VERSION 5.8 ;
BUSBITCHARS "[]" ;
DIVIDERCHAR "/" ;
UNITS
    DATABASE MICRONS 1000 ;
END UNITS

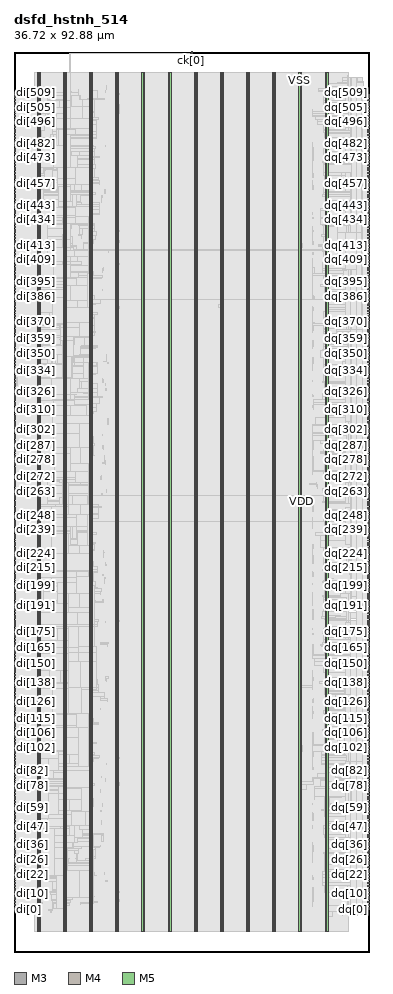
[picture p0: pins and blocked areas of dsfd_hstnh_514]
MACRO dsfd_hstnh_514
  FOREIGN dsfd_hstnh_514 0 0 ;
  CLASS BLOCK ;
  SIZE 36.72 BY 92.88 ;
  PIN ck[0]
    DIRECTION INPUT ;
    USE SIGNAL ;
    PORT
      LAYER M3 ;
        RECT  18.36 92.736 18.378 92.88 ;
    END
    PORT
      LAYER M3 ;
        RECT  18.18 92.713 18.378 92.748 ;
    END
  END ck[0]
  PIN di[0]
    DIRECTION INPUT ;
    USE SIGNAL ;
    PORT
      LAYER M4 ;
        RECT  0 4.416 0.192 4.44 ;
    END
  END di[0]
  PIN di[100]
    DIRECTION INPUT ;
    USE SIGNAL ;
    PORT
      LAYER M4 ;
        RECT  0 20.784 0.192 20.808 ;
    END
  END di[100]
  PIN di[101]
    DIRECTION INPUT ;
    USE SIGNAL ;
    PORT
      LAYER M4 ;
        RECT  0 20.976 0.192 21 ;
    END
  END di[101]
  PIN di[102]
    DIRECTION INPUT ;
    USE SIGNAL ;
    PORT
      LAYER M4 ;
        RECT  0 21.12 0.192 21.144 ;
    END
  END di[102]
  PIN di[103]
    DIRECTION INPUT ;
    USE SIGNAL ;
    PORT
      LAYER M4 ;
        RECT  0 21.312 0.192 21.336 ;
    END
  END di[103]
  PIN di[104]
    DIRECTION INPUT ;
    USE SIGNAL ;
    PORT
      LAYER M4 ;
        RECT  0 21.456 0.192 21.48 ;
    END
  END di[104]
  PIN di[105]
    DIRECTION INPUT ;
    USE SIGNAL ;
    PORT
      LAYER M4 ;
        RECT  0 21.6 0.192 21.624 ;
    END
  END di[105]
  PIN di[106]
    DIRECTION INPUT ;
    USE SIGNAL ;
    PORT
      LAYER M4 ;
        RECT  0 21.792 0.192 21.816 ;
    END
  END di[106]
  PIN di[107]
    DIRECTION INPUT ;
    USE SIGNAL ;
    PORT
      LAYER M4 ;
        RECT  0 21.936 0.192 21.96 ;
    END
  END di[107]
  PIN di[108]
    DIRECTION INPUT ;
    USE SIGNAL ;
    PORT
      LAYER M4 ;
        RECT  0 22.128 0.192 22.152 ;
    END
  END di[108]
  PIN di[109]
    DIRECTION INPUT ;
    USE SIGNAL ;
    PORT
      LAYER M4 ;
        RECT  0 22.272 0.192 22.296 ;
    END
  END di[109]
  PIN di[10]
    DIRECTION INPUT ;
    USE SIGNAL ;
    PORT
      LAYER M4 ;
        RECT  0 6.048 0.192 6.072 ;
    END
  END di[10]
  PIN di[110]
    DIRECTION INPUT ;
    USE SIGNAL ;
    PORT
      LAYER M4 ;
        RECT  0 22.464 0.192 22.488 ;
    END
  END di[110]
  PIN di[111]
    DIRECTION INPUT ;
    USE SIGNAL ;
    PORT
      LAYER M4 ;
        RECT  0 22.608 0.192 22.632 ;
    END
  END di[111]
  PIN di[112]
    DIRECTION INPUT ;
    USE SIGNAL ;
    PORT
      LAYER M4 ;
        RECT  0 22.752 0.192 22.776 ;
    END
  END di[112]
  PIN di[113]
    DIRECTION INPUT ;
    USE SIGNAL ;
    PORT
      LAYER M4 ;
        RECT  0 22.944 0.192 22.968 ;
    END
  END di[113]
  PIN di[114]
    DIRECTION INPUT ;
    USE SIGNAL ;
    PORT
      LAYER M4 ;
        RECT  0 23.088 0.192 23.112 ;
    END
  END di[114]
  PIN di[115]
    DIRECTION INPUT ;
    USE SIGNAL ;
    PORT
      LAYER M4 ;
        RECT  0 23.28 0.192 23.304 ;
    END
  END di[115]
  PIN di[116]
    DIRECTION INPUT ;
    USE SIGNAL ;
    PORT
      LAYER M4 ;
        RECT  0 23.424 0.192 23.448 ;
    END
  END di[116]
  PIN di[117]
    DIRECTION INPUT ;
    USE SIGNAL ;
    PORT
      LAYER M4 ;
        RECT  0 23.568 0.192 23.592 ;
    END
  END di[117]
  PIN di[118]
    DIRECTION INPUT ;
    USE SIGNAL ;
    PORT
      LAYER M4 ;
        RECT  0 23.76 0.192 23.784 ;
    END
  END di[118]
  PIN di[119]
    DIRECTION INPUT ;
    USE SIGNAL ;
    PORT
      LAYER M4 ;
        RECT  0 23.904 0.192 23.928 ;
    END
  END di[119]
  PIN di[11]
    DIRECTION INPUT ;
    USE SIGNAL ;
    PORT
      LAYER M4 ;
        RECT  0 6.24 0.192 6.264 ;
    END
  END di[11]
  PIN di[120]
    DIRECTION INPUT ;
    USE SIGNAL ;
    PORT
      LAYER M4 ;
        RECT  0 24.096 0.192 24.12 ;
    END
  END di[120]
  PIN di[121]
    DIRECTION INPUT ;
    USE SIGNAL ;
    PORT
      LAYER M4 ;
        RECT  0 24.24 0.192 24.264 ;
    END
  END di[121]
  PIN di[122]
    DIRECTION INPUT ;
    USE SIGNAL ;
    PORT
      LAYER M4 ;
        RECT  0 24.432 0.192 24.456 ;
    END
  END di[122]
  PIN di[123]
    DIRECTION INPUT ;
    USE SIGNAL ;
    PORT
      LAYER M4 ;
        RECT  0 24.576 0.192 24.6 ;
    END
  END di[123]
  PIN di[124]
    DIRECTION INPUT ;
    USE SIGNAL ;
    PORT
      LAYER M4 ;
        RECT  0 24.72 0.192 24.744 ;
    END
  END di[124]
  PIN di[125]
    DIRECTION INPUT ;
    USE SIGNAL ;
    PORT
      LAYER M4 ;
        RECT  0 24.912 0.192 24.936 ;
    END
  END di[125]
  PIN di[126]
    DIRECTION INPUT ;
    USE SIGNAL ;
    PORT
      LAYER M4 ;
        RECT  0 25.056 0.192 25.08 ;
    END
  END di[126]
  PIN di[127]
    DIRECTION INPUT ;
    USE SIGNAL ;
    PORT
      LAYER M4 ;
        RECT  0 25.248 0.192 25.272 ;
    END
  END di[127]
  PIN di[128]
    DIRECTION INPUT ;
    USE SIGNAL ;
    PORT
      LAYER M4 ;
        RECT  0 25.392 0.192 25.416 ;
    END
  END di[128]
  PIN di[129]
    DIRECTION INPUT ;
    USE SIGNAL ;
    PORT
      LAYER M4 ;
        RECT  0 25.536 0.192 25.56 ;
    END
  END di[129]
  PIN di[12]
    DIRECTION INPUT ;
    USE SIGNAL ;
    PORT
      LAYER M4 ;
        RECT  0 6.384 0.192 6.408 ;
    END
  END di[12]
  PIN di[130]
    DIRECTION INPUT ;
    USE SIGNAL ;
    PORT
      LAYER M4 ;
        RECT  0 25.728 0.192 25.752 ;
    END
  END di[130]
  PIN di[131]
    DIRECTION INPUT ;
    USE SIGNAL ;
    PORT
      LAYER M4 ;
        RECT  0 25.872 0.192 25.896 ;
    END
  END di[131]
  PIN di[132]
    DIRECTION INPUT ;
    USE SIGNAL ;
    PORT
      LAYER M4 ;
        RECT  0 26.064 0.192 26.088 ;
    END
  END di[132]
  PIN di[133]
    DIRECTION INPUT ;
    USE SIGNAL ;
    PORT
      LAYER M4 ;
        RECT  0 26.208 0.192 26.232 ;
    END
  END di[133]
  PIN di[134]
    DIRECTION INPUT ;
    USE SIGNAL ;
    PORT
      LAYER M4 ;
        RECT  0 26.352 0.192 26.376 ;
    END
  END di[134]
  PIN di[135]
    DIRECTION INPUT ;
    USE SIGNAL ;
    PORT
      LAYER M4 ;
        RECT  0 26.544 0.192 26.568 ;
    END
  END di[135]
  PIN di[136]
    DIRECTION INPUT ;
    USE SIGNAL ;
    PORT
      LAYER M4 ;
        RECT  0 26.688 0.192 26.712 ;
    END
  END di[136]
  PIN di[137]
    DIRECTION INPUT ;
    USE SIGNAL ;
    PORT
      LAYER M4 ;
        RECT  0 26.88 0.192 26.904 ;
    END
  END di[137]
  PIN di[138]
    DIRECTION INPUT ;
    USE SIGNAL ;
    PORT
      LAYER M4 ;
        RECT  0 27.024 0.192 27.048 ;
    END
  END di[138]
  PIN di[139]
    DIRECTION INPUT ;
    USE SIGNAL ;
    PORT
      LAYER M4 ;
        RECT  0 27.216 0.192 27.24 ;
    END
  END di[139]
  PIN di[13]
    DIRECTION INPUT ;
    USE SIGNAL ;
    PORT
      LAYER M4 ;
        RECT  0 6.528 0.192 6.552 ;
    END
  END di[13]
  PIN di[140]
    DIRECTION INPUT ;
    USE SIGNAL ;
    PORT
      LAYER M4 ;
        RECT  0 27.36 0.192 27.384 ;
    END
  END di[140]
  PIN di[141]
    DIRECTION INPUT ;
    USE SIGNAL ;
    PORT
      LAYER M4 ;
        RECT  0 27.504 0.192 27.528 ;
    END
  END di[141]
  PIN di[142]
    DIRECTION INPUT ;
    USE SIGNAL ;
    PORT
      LAYER M4 ;
        RECT  0 27.696 0.192 27.72 ;
    END
  END di[142]
  PIN di[143]
    DIRECTION INPUT ;
    USE SIGNAL ;
    PORT
      LAYER M4 ;
        RECT  0 27.84 0.192 27.864 ;
    END
  END di[143]
  PIN di[144]
    DIRECTION INPUT ;
    USE SIGNAL ;
    PORT
      LAYER M4 ;
        RECT  0 28.032 0.192 28.056 ;
    END
  END di[144]
  PIN di[145]
    DIRECTION INPUT ;
    USE SIGNAL ;
    PORT
      LAYER M4 ;
        RECT  0 28.176 0.192 28.2 ;
    END
  END di[145]
  PIN di[146]
    DIRECTION INPUT ;
    USE SIGNAL ;
    PORT
      LAYER M4 ;
        RECT  0 28.32 0.192 28.344 ;
    END
  END di[146]
  PIN di[147]
    DIRECTION INPUT ;
    USE SIGNAL ;
    PORT
      LAYER M4 ;
        RECT  0 28.512 0.192 28.536 ;
    END
  END di[147]
  PIN di[148]
    DIRECTION INPUT ;
    USE SIGNAL ;
    PORT
      LAYER M4 ;
        RECT  0 28.656 0.192 28.68 ;
    END
  END di[148]
  PIN di[149]
    DIRECTION INPUT ;
    USE SIGNAL ;
    PORT
      LAYER M4 ;
        RECT  0 28.848 0.192 28.872 ;
    END
  END di[149]
  PIN di[14]
    DIRECTION INPUT ;
    USE SIGNAL ;
    PORT
      LAYER M4 ;
        RECT  0 6.72 0.192 6.744 ;
    END
  END di[14]
  PIN di[150]
    DIRECTION INPUT ;
    USE SIGNAL ;
    PORT
      LAYER M4 ;
        RECT  0 28.992 0.192 29.016 ;
    END
  END di[150]
  PIN di[151]
    DIRECTION INPUT ;
    USE SIGNAL ;
    PORT
      LAYER M4 ;
        RECT  0 29.184 0.192 29.208 ;
    END
  END di[151]
  PIN di[152]
    DIRECTION INPUT ;
    USE SIGNAL ;
    PORT
      LAYER M4 ;
        RECT  0 29.328 0.192 29.352 ;
    END
  END di[152]
  PIN di[153]
    DIRECTION INPUT ;
    USE SIGNAL ;
    PORT
      LAYER M4 ;
        RECT  0 29.472 0.192 29.496 ;
    END
  END di[153]
  PIN di[154]
    DIRECTION INPUT ;
    USE SIGNAL ;
    PORT
      LAYER M4 ;
        RECT  0 29.664 0.192 29.688 ;
    END
  END di[154]
  PIN di[155]
    DIRECTION INPUT ;
    USE SIGNAL ;
    PORT
      LAYER M4 ;
        RECT  0 29.808 0.192 29.832 ;
    END
  END di[155]
  PIN di[156]
    DIRECTION INPUT ;
    USE SIGNAL ;
    PORT
      LAYER M4 ;
        RECT  0 30 0.192 30.024 ;
    END
  END di[156]
  PIN di[157]
    DIRECTION INPUT ;
    USE SIGNAL ;
    PORT
      LAYER M4 ;
        RECT  0 30.144 0.192 30.168 ;
    END
  END di[157]
  PIN di[158]
    DIRECTION INPUT ;
    USE SIGNAL ;
    PORT
      LAYER M4 ;
        RECT  0 30.288 0.192 30.312 ;
    END
  END di[158]
  PIN di[159]
    DIRECTION INPUT ;
    USE SIGNAL ;
    PORT
      LAYER M4 ;
        RECT  0 30.48 0.192 30.504 ;
    END
  END di[159]
  PIN di[15]
    DIRECTION INPUT ;
    USE SIGNAL ;
    PORT
      LAYER M4 ;
        RECT  0 6.864 0.192 6.888 ;
    END
  END di[15]
  PIN di[160]
    DIRECTION INPUT ;
    USE SIGNAL ;
    PORT
      LAYER M4 ;
        RECT  0 30.624 0.192 30.648 ;
    END
  END di[160]
  PIN di[161]
    DIRECTION INPUT ;
    USE SIGNAL ;
    PORT
      LAYER M4 ;
        RECT  0 30.816 0.192 30.84 ;
    END
  END di[161]
  PIN di[162]
    DIRECTION INPUT ;
    USE SIGNAL ;
    PORT
      LAYER M4 ;
        RECT  0 30.96 0.192 30.984 ;
    END
  END di[162]
  PIN di[163]
    DIRECTION INPUT ;
    USE SIGNAL ;
    PORT
      LAYER M4 ;
        RECT  0 31.152 0.192 31.176 ;
    END
  END di[163]
  PIN di[164]
    DIRECTION INPUT ;
    USE SIGNAL ;
    PORT
      LAYER M4 ;
        RECT  0 31.296 0.192 31.32 ;
    END
  END di[164]
  PIN di[165]
    DIRECTION INPUT ;
    USE SIGNAL ;
    PORT
      LAYER M4 ;
        RECT  0 31.44 0.192 31.464 ;
    END
  END di[165]
  PIN di[166]
    DIRECTION INPUT ;
    USE SIGNAL ;
    PORT
      LAYER M4 ;
        RECT  0 31.632 0.192 31.656 ;
    END
  END di[166]
  PIN di[167]
    DIRECTION INPUT ;
    USE SIGNAL ;
    PORT
      LAYER M4 ;
        RECT  0 31.776 0.192 31.8 ;
    END
  END di[167]
  PIN di[168]
    DIRECTION INPUT ;
    USE SIGNAL ;
    PORT
      LAYER M4 ;
        RECT  0 31.968 0.192 31.992 ;
    END
  END di[168]
  PIN di[169]
    DIRECTION INPUT ;
    USE SIGNAL ;
    PORT
      LAYER M4 ;
        RECT  0 32.112 0.192 32.136 ;
    END
  END di[169]
  PIN di[16]
    DIRECTION INPUT ;
    USE SIGNAL ;
    PORT
      LAYER M4 ;
        RECT  0 7.056 0.192 7.08 ;
    END
  END di[16]
  PIN di[170]
    DIRECTION INPUT ;
    USE SIGNAL ;
    PORT
      LAYER M4 ;
        RECT  0 32.256 0.192 32.28 ;
    END
  END di[170]
  PIN di[171]
    DIRECTION INPUT ;
    USE SIGNAL ;
    PORT
      LAYER M4 ;
        RECT  0 32.448 0.192 32.472 ;
    END
  END di[171]
  PIN di[172]
    DIRECTION INPUT ;
    USE SIGNAL ;
    PORT
      LAYER M4 ;
        RECT  0 32.592 0.192 32.616 ;
    END
  END di[172]
  PIN di[173]
    DIRECTION INPUT ;
    USE SIGNAL ;
    PORT
      LAYER M4 ;
        RECT  0 32.784 0.192 32.808 ;
    END
  END di[173]
  PIN di[174]
    DIRECTION INPUT ;
    USE SIGNAL ;
    PORT
      LAYER M4 ;
        RECT  0 32.928 0.192 32.952 ;
    END
  END di[174]
  PIN di[175]
    DIRECTION INPUT ;
    USE SIGNAL ;
    PORT
      LAYER M4 ;
        RECT  0 33.072 0.192 33.096 ;
    END
  END di[175]
  PIN di[176]
    DIRECTION INPUT ;
    USE SIGNAL ;
    PORT
      LAYER M4 ;
        RECT  0 33.264 0.192 33.288 ;
    END
  END di[176]
  PIN di[177]
    DIRECTION INPUT ;
    USE SIGNAL ;
    PORT
      LAYER M4 ;
        RECT  0 33.408 0.192 33.432 ;
    END
  END di[177]
  PIN di[178]
    DIRECTION INPUT ;
    USE SIGNAL ;
    PORT
      LAYER M4 ;
        RECT  0 33.6 0.192 33.624 ;
    END
  END di[178]
  PIN di[179]
    DIRECTION INPUT ;
    USE SIGNAL ;
    PORT
      LAYER M4 ;
        RECT  0 33.744 0.192 33.768 ;
    END
  END di[179]
  PIN di[17]
    DIRECTION INPUT ;
    USE SIGNAL ;
    PORT
      LAYER M4 ;
        RECT  0 7.2 0.192 7.224 ;
    END
  END di[17]
  PIN di[180]
    DIRECTION INPUT ;
    USE SIGNAL ;
    PORT
      LAYER M4 ;
        RECT  0 33.936 0.192 33.96 ;
    END
  END di[180]
  PIN di[181]
    DIRECTION INPUT ;
    USE SIGNAL ;
    PORT
      LAYER M4 ;
        RECT  0 34.08 0.192 34.104 ;
    END
  END di[181]
  PIN di[182]
    DIRECTION INPUT ;
    USE SIGNAL ;
    PORT
      LAYER M4 ;
        RECT  0 34.224 0.192 34.248 ;
    END
  END di[182]
  PIN di[183]
    DIRECTION INPUT ;
    USE SIGNAL ;
    PORT
      LAYER M4 ;
        RECT  0 34.416 0.192 34.44 ;
    END
  END di[183]
  PIN di[184]
    DIRECTION INPUT ;
    USE SIGNAL ;
    PORT
      LAYER M4 ;
        RECT  0 34.56 0.192 34.584 ;
    END
  END di[184]
  PIN di[185]
    DIRECTION INPUT ;
    USE SIGNAL ;
    PORT
      LAYER M4 ;
        RECT  0 34.752 0.192 34.776 ;
    END
  END di[185]
  PIN di[186]
    DIRECTION INPUT ;
    USE SIGNAL ;
    PORT
      LAYER M4 ;
        RECT  0 34.896 0.192 34.92 ;
    END
  END di[186]
  PIN di[187]
    DIRECTION INPUT ;
    USE SIGNAL ;
    PORT
      LAYER M4 ;
        RECT  0 35.04 0.192 35.064 ;
    END
  END di[187]
  PIN di[188]
    DIRECTION INPUT ;
    USE SIGNAL ;
    PORT
      LAYER M4 ;
        RECT  0 35.232 0.192 35.256 ;
    END
  END di[188]
  PIN di[189]
    DIRECTION INPUT ;
    USE SIGNAL ;
    PORT
      LAYER M4 ;
        RECT  0 35.376 0.192 35.4 ;
    END
  END di[189]
  PIN di[18]
    DIRECTION INPUT ;
    USE SIGNAL ;
    PORT
      LAYER M4 ;
        RECT  0 7.344 0.192 7.368 ;
    END
  END di[18]
  PIN di[190]
    DIRECTION INPUT ;
    USE SIGNAL ;
    PORT
      LAYER M4 ;
        RECT  0 35.568 0.192 35.592 ;
    END
  END di[190]
  PIN di[191]
    DIRECTION INPUT ;
    USE SIGNAL ;
    PORT
      LAYER M4 ;
        RECT  0 35.712 0.192 35.736 ;
    END
  END di[191]
  PIN di[192]
    DIRECTION INPUT ;
    USE SIGNAL ;
    PORT
      LAYER M4 ;
        RECT  0 35.904 0.192 35.928 ;
    END
  END di[192]
  PIN di[193]
    DIRECTION INPUT ;
    USE SIGNAL ;
    PORT
      LAYER M4 ;
        RECT  0 36.048 0.192 36.072 ;
    END
  END di[193]
  PIN di[194]
    DIRECTION INPUT ;
    USE SIGNAL ;
    PORT
      LAYER M4 ;
        RECT  0 36.192 0.192 36.216 ;
    END
  END di[194]
  PIN di[195]
    DIRECTION INPUT ;
    USE SIGNAL ;
    PORT
      LAYER M4 ;
        RECT  0 36.384 0.192 36.408 ;
    END
  END di[195]
  PIN di[196]
    DIRECTION INPUT ;
    USE SIGNAL ;
    PORT
      LAYER M4 ;
        RECT  0 36.528 0.192 36.552 ;
    END
  END di[196]
  PIN di[197]
    DIRECTION INPUT ;
    USE SIGNAL ;
    PORT
      LAYER M4 ;
        RECT  0 36.72 0.192 36.744 ;
    END
  END di[197]
  PIN di[198]
    DIRECTION INPUT ;
    USE SIGNAL ;
    PORT
      LAYER M4 ;
        RECT  0 36.864 0.192 36.888 ;
    END
  END di[198]
  PIN di[199]
    DIRECTION INPUT ;
    USE SIGNAL ;
    PORT
      LAYER M4 ;
        RECT  0 37.008 0.192 37.032 ;
    END
  END di[199]
  PIN di[19]
    DIRECTION INPUT ;
    USE SIGNAL ;
    PORT
      LAYER M4 ;
        RECT  0 7.536 0.192 7.56 ;
    END
  END di[19]
  PIN di[1]
    DIRECTION INPUT ;
    USE SIGNAL ;
    PORT
      LAYER M4 ;
        RECT  0 4.56 0.192 4.584 ;
    END
  END di[1]
  PIN di[200]
    DIRECTION INPUT ;
    USE SIGNAL ;
    PORT
      LAYER M4 ;
        RECT  0 37.2 0.192 37.224 ;
    END
  END di[200]
  PIN di[201]
    DIRECTION INPUT ;
    USE SIGNAL ;
    PORT
      LAYER M4 ;
        RECT  0 37.344 0.192 37.368 ;
    END
  END di[201]
  PIN di[202]
    DIRECTION INPUT ;
    USE SIGNAL ;
    PORT
      LAYER M4 ;
        RECT  0 37.536 0.192 37.56 ;
    END
  END di[202]
  PIN di[203]
    DIRECTION INPUT ;
    USE SIGNAL ;
    PORT
      LAYER M4 ;
        RECT  0 37.68 0.192 37.704 ;
    END
  END di[203]
  PIN di[204]
    DIRECTION INPUT ;
    USE SIGNAL ;
    PORT
      LAYER M4 ;
        RECT  0 37.824 0.192 37.848 ;
    END
  END di[204]
  PIN di[205]
    DIRECTION INPUT ;
    USE SIGNAL ;
    PORT
      LAYER M4 ;
        RECT  0 38.016 0.192 38.04 ;
    END
  END di[205]
  PIN di[206]
    DIRECTION INPUT ;
    USE SIGNAL ;
    PORT
      LAYER M4 ;
        RECT  0 38.16 0.192 38.184 ;
    END
  END di[206]
  PIN di[207]
    DIRECTION INPUT ;
    USE SIGNAL ;
    PORT
      LAYER M4 ;
        RECT  0 38.352 0.192 38.376 ;
    END
  END di[207]
  PIN di[208]
    DIRECTION INPUT ;
    USE SIGNAL ;
    PORT
      LAYER M4 ;
        RECT  0 38.496 0.192 38.52 ;
    END
  END di[208]
  PIN di[209]
    DIRECTION INPUT ;
    USE SIGNAL ;
    PORT
      LAYER M4 ;
        RECT  0 38.688 0.192 38.712 ;
    END
  END di[209]
  PIN di[20]
    DIRECTION INPUT ;
    USE SIGNAL ;
    PORT
      LAYER M4 ;
        RECT  0 7.68 0.192 7.704 ;
    END
  END di[20]
  PIN di[210]
    DIRECTION INPUT ;
    USE SIGNAL ;
    PORT
      LAYER M4 ;
        RECT  0 38.832 0.192 38.856 ;
    END
  END di[210]
  PIN di[211]
    DIRECTION INPUT ;
    USE SIGNAL ;
    PORT
      LAYER M4 ;
        RECT  0 38.976 0.192 39 ;
    END
  END di[211]
  PIN di[212]
    DIRECTION INPUT ;
    USE SIGNAL ;
    PORT
      LAYER M4 ;
        RECT  0 39.168 0.192 39.192 ;
    END
  END di[212]
  PIN di[213]
    DIRECTION INPUT ;
    USE SIGNAL ;
    PORT
      LAYER M4 ;
        RECT  0 39.312 0.192 39.336 ;
    END
  END di[213]
  PIN di[214]
    DIRECTION INPUT ;
    USE SIGNAL ;
    PORT
      LAYER M4 ;
        RECT  0 39.504 0.192 39.528 ;
    END
  END di[214]
  PIN di[215]
    DIRECTION INPUT ;
    USE SIGNAL ;
    PORT
      LAYER M4 ;
        RECT  0 39.648 0.192 39.672 ;
    END
  END di[215]
  PIN di[216]
    DIRECTION INPUT ;
    USE SIGNAL ;
    PORT
      LAYER M4 ;
        RECT  0 39.792 0.192 39.816 ;
    END
  END di[216]
  PIN di[217]
    DIRECTION INPUT ;
    USE SIGNAL ;
    PORT
      LAYER M4 ;
        RECT  0 39.984 0.192 40.008 ;
    END
  END di[217]
  PIN di[218]
    DIRECTION INPUT ;
    USE SIGNAL ;
    PORT
      LAYER M4 ;
        RECT  0 40.128 0.192 40.152 ;
    END
  END di[218]
  PIN di[219]
    DIRECTION INPUT ;
    USE SIGNAL ;
    PORT
      LAYER M4 ;
        RECT  0 40.32 0.192 40.344 ;
    END
  END di[219]
  PIN di[21]
    DIRECTION INPUT ;
    USE SIGNAL ;
    PORT
      LAYER M4 ;
        RECT  0 7.872 0.192 7.896 ;
    END
  END di[21]
  PIN di[220]
    DIRECTION INPUT ;
    USE SIGNAL ;
    PORT
      LAYER M4 ;
        RECT  0 40.464 0.192 40.488 ;
    END
  END di[220]
  PIN di[221]
    DIRECTION INPUT ;
    USE SIGNAL ;
    PORT
      LAYER M4 ;
        RECT  0 40.656 0.192 40.68 ;
    END
  END di[221]
  PIN di[222]
    DIRECTION INPUT ;
    USE SIGNAL ;
    PORT
      LAYER M4 ;
        RECT  0 40.8 0.192 40.824 ;
    END
  END di[222]
  PIN di[223]
    DIRECTION INPUT ;
    USE SIGNAL ;
    PORT
      LAYER M4 ;
        RECT  0 40.944 0.192 40.968 ;
    END
  END di[223]
  PIN di[224]
    DIRECTION INPUT ;
    USE SIGNAL ;
    PORT
      LAYER M4 ;
        RECT  0 41.136 0.192 41.16 ;
    END
  END di[224]
  PIN di[225]
    DIRECTION INPUT ;
    USE SIGNAL ;
    PORT
      LAYER M4 ;
        RECT  0 41.28 0.192 41.304 ;
    END
  END di[225]
  PIN di[226]
    DIRECTION INPUT ;
    USE SIGNAL ;
    PORT
      LAYER M4 ;
        RECT  0 41.472 0.192 41.496 ;
    END
  END di[226]
  PIN di[227]
    DIRECTION INPUT ;
    USE SIGNAL ;
    PORT
      LAYER M4 ;
        RECT  0 41.616 0.192 41.64 ;
    END
  END di[227]
  PIN di[228]
    DIRECTION INPUT ;
    USE SIGNAL ;
    PORT
      LAYER M4 ;
        RECT  0 41.76 0.192 41.784 ;
    END
  END di[228]
  PIN di[229]
    DIRECTION INPUT ;
    USE SIGNAL ;
    PORT
      LAYER M4 ;
        RECT  0 41.952 0.192 41.976 ;
    END
  END di[229]
  PIN di[22]
    DIRECTION INPUT ;
    USE SIGNAL ;
    PORT
      LAYER M4 ;
        RECT  0 8.016 0.192 8.04 ;
    END
  END di[22]
  PIN di[230]
    DIRECTION INPUT ;
    USE SIGNAL ;
    PORT
      LAYER M4 ;
        RECT  0 42.096 0.192 42.12 ;
    END
  END di[230]
  PIN di[231]
    DIRECTION INPUT ;
    USE SIGNAL ;
    PORT
      LAYER M4 ;
        RECT  0 42.288 0.192 42.312 ;
    END
  END di[231]
  PIN di[232]
    DIRECTION INPUT ;
    USE SIGNAL ;
    PORT
      LAYER M4 ;
        RECT  0 42.432 0.192 42.456 ;
    END
  END di[232]
  PIN di[233]
    DIRECTION INPUT ;
    USE SIGNAL ;
    PORT
      LAYER M4 ;
        RECT  0 42.624 0.192 42.648 ;
    END
  END di[233]
  PIN di[234]
    DIRECTION INPUT ;
    USE SIGNAL ;
    PORT
      LAYER M4 ;
        RECT  0 42.768 0.192 42.792 ;
    END
  END di[234]
  PIN di[235]
    DIRECTION INPUT ;
    USE SIGNAL ;
    PORT
      LAYER M4 ;
        RECT  0 42.912 0.192 42.936 ;
    END
  END di[235]
  PIN di[236]
    DIRECTION INPUT ;
    USE SIGNAL ;
    PORT
      LAYER M4 ;
        RECT  0 43.104 0.192 43.128 ;
    END
  END di[236]
  PIN di[237]
    DIRECTION INPUT ;
    USE SIGNAL ;
    PORT
      LAYER M4 ;
        RECT  0 43.248 0.192 43.272 ;
    END
  END di[237]
  PIN di[238]
    DIRECTION INPUT ;
    USE SIGNAL ;
    PORT
      LAYER M4 ;
        RECT  0 43.44 0.192 43.464 ;
    END
  END di[238]
  PIN di[239]
    DIRECTION INPUT ;
    USE SIGNAL ;
    PORT
      LAYER M4 ;
        RECT  0 43.584 0.192 43.608 ;
    END
  END di[239]
  PIN di[23]
    DIRECTION INPUT ;
    USE SIGNAL ;
    PORT
      LAYER M4 ;
        RECT  0 8.16 0.192 8.184 ;
    END
  END di[23]
  PIN di[240]
    DIRECTION INPUT ;
    USE SIGNAL ;
    PORT
      LAYER M4 ;
        RECT  0 43.728 0.192 43.752 ;
    END
  END di[240]
  PIN di[241]
    DIRECTION INPUT ;
    USE SIGNAL ;
    PORT
      LAYER M4 ;
        RECT  0 43.92 0.192 43.944 ;
    END
  END di[241]
  PIN di[242]
    DIRECTION INPUT ;
    USE SIGNAL ;
    PORT
      LAYER M4 ;
        RECT  0 44.064 0.192 44.088 ;
    END
  END di[242]
  PIN di[243]
    DIRECTION INPUT ;
    USE SIGNAL ;
    PORT
      LAYER M4 ;
        RECT  0 44.256 0.192 44.28 ;
    END
  END di[243]
  PIN di[244]
    DIRECTION INPUT ;
    USE SIGNAL ;
    PORT
      LAYER M4 ;
        RECT  0 44.4 0.192 44.424 ;
    END
  END di[244]
  PIN di[245]
    DIRECTION INPUT ;
    USE SIGNAL ;
    PORT
      LAYER M4 ;
        RECT  0 44.544 0.192 44.568 ;
    END
  END di[245]
  PIN di[246]
    DIRECTION INPUT ;
    USE SIGNAL ;
    PORT
      LAYER M4 ;
        RECT  0 44.736 0.192 44.76 ;
    END
  END di[246]
  PIN di[247]
    DIRECTION INPUT ;
    USE SIGNAL ;
    PORT
      LAYER M4 ;
        RECT  0 44.88 0.192 44.904 ;
    END
  END di[247]
  PIN di[248]
    DIRECTION INPUT ;
    USE SIGNAL ;
    PORT
      LAYER M4 ;
        RECT  0 45.072 0.192 45.096 ;
    END
  END di[248]
  PIN di[249]
    DIRECTION INPUT ;
    USE SIGNAL ;
    PORT
      LAYER M4 ;
        RECT  0 45.216 0.192 45.24 ;
    END
  END di[249]
  PIN di[24]
    DIRECTION INPUT ;
    USE SIGNAL ;
    PORT
      LAYER M4 ;
        RECT  0 8.352 0.192 8.376 ;
    END
  END di[24]
  PIN di[250]
    DIRECTION INPUT ;
    USE SIGNAL ;
    PORT
      LAYER M4 ;
        RECT  0 45.408 0.192 45.432 ;
    END
  END di[250]
  PIN di[251]
    DIRECTION INPUT ;
    USE SIGNAL ;
    PORT
      LAYER M4 ;
        RECT  0 45.552 0.192 45.576 ;
    END
  END di[251]
  PIN di[252]
    DIRECTION INPUT ;
    USE SIGNAL ;
    PORT
      LAYER M4 ;
        RECT  0 45.696 0.192 45.72 ;
    END
  END di[252]
  PIN di[253]
    DIRECTION INPUT ;
    USE SIGNAL ;
    PORT
      LAYER M4 ;
        RECT  0 45.888 0.192 45.912 ;
    END
  END di[253]
  PIN di[254]
    DIRECTION INPUT ;
    USE SIGNAL ;
    PORT
      LAYER M4 ;
        RECT  0 46.032 0.192 46.056 ;
    END
  END di[254]
  PIN di[255]
    DIRECTION INPUT ;
    USE SIGNAL ;
    PORT
      LAYER M4 ;
        RECT  0 46.224 0.192 46.248 ;
    END
  END di[255]
  PIN di[256]
    DIRECTION INPUT ;
    USE SIGNAL ;
    PORT
      LAYER M4 ;
        RECT  0 46.368 0.192 46.392 ;
    END
  END di[256]
  PIN di[257]
    DIRECTION INPUT ;
    USE SIGNAL ;
    PORT
      LAYER M4 ;
        RECT  0 46.512 0.192 46.536 ;
    END
  END di[257]
  PIN di[258]
    DIRECTION INPUT ;
    USE SIGNAL ;
    PORT
      LAYER M4 ;
        RECT  0 46.704 0.192 46.728 ;
    END
  END di[258]
  PIN di[259]
    DIRECTION INPUT ;
    USE SIGNAL ;
    PORT
      LAYER M4 ;
        RECT  0 46.848 0.192 46.872 ;
    END
  END di[259]
  PIN di[25]
    DIRECTION INPUT ;
    USE SIGNAL ;
    PORT
      LAYER M4 ;
        RECT  0 8.496 0.192 8.52 ;
    END
  END di[25]
  PIN di[260]
    DIRECTION INPUT ;
    USE SIGNAL ;
    PORT
      LAYER M4 ;
        RECT  0 47.04 0.192 47.064 ;
    END
  END di[260]
  PIN di[261]
    DIRECTION INPUT ;
    USE SIGNAL ;
    PORT
      LAYER M4 ;
        RECT  0 47.184 0.192 47.208 ;
    END
  END di[261]
  PIN di[262]
    DIRECTION INPUT ;
    USE SIGNAL ;
    PORT
      LAYER M4 ;
        RECT  0 47.376 0.192 47.4 ;
    END
  END di[262]
  PIN di[263]
    DIRECTION INPUT ;
    USE SIGNAL ;
    PORT
      LAYER M4 ;
        RECT  0 47.52 0.192 47.544 ;
    END
  END di[263]
  PIN di[264]
    DIRECTION INPUT ;
    USE SIGNAL ;
    PORT
      LAYER M4 ;
        RECT  0 47.664 0.192 47.688 ;
    END
  END di[264]
  PIN di[265]
    DIRECTION INPUT ;
    USE SIGNAL ;
    PORT
      LAYER M4 ;
        RECT  0 47.856 0.192 47.88 ;
    END
  END di[265]
  PIN di[266]
    DIRECTION INPUT ;
    USE SIGNAL ;
    PORT
      LAYER M4 ;
        RECT  0 48 0.192 48.024 ;
    END
  END di[266]
  PIN di[267]
    DIRECTION INPUT ;
    USE SIGNAL ;
    PORT
      LAYER M4 ;
        RECT  0 48.192 0.192 48.216 ;
    END
  END di[267]
  PIN di[268]
    DIRECTION INPUT ;
    USE SIGNAL ;
    PORT
      LAYER M4 ;
        RECT  0 48.336 0.192 48.36 ;
    END
  END di[268]
  PIN di[269]
    DIRECTION INPUT ;
    USE SIGNAL ;
    PORT
      LAYER M4 ;
        RECT  0 48.48 0.192 48.504 ;
    END
  END di[269]
  PIN di[26]
    DIRECTION INPUT ;
    USE SIGNAL ;
    PORT
      LAYER M4 ;
        RECT  0 8.688 0.192 8.712 ;
    END
  END di[26]
  PIN di[270]
    DIRECTION INPUT ;
    USE SIGNAL ;
    PORT
      LAYER M4 ;
        RECT  0 48.672 0.192 48.696 ;
    END
  END di[270]
  PIN di[271]
    DIRECTION INPUT ;
    USE SIGNAL ;
    PORT
      LAYER M4 ;
        RECT  0 48.816 0.192 48.84 ;
    END
  END di[271]
  PIN di[272]
    DIRECTION INPUT ;
    USE SIGNAL ;
    PORT
      LAYER M4 ;
        RECT  0 49.008 0.192 49.032 ;
    END
  END di[272]
  PIN di[273]
    DIRECTION INPUT ;
    USE SIGNAL ;
    PORT
      LAYER M4 ;
        RECT  0 49.152 0.192 49.176 ;
    END
  END di[273]
  PIN di[274]
    DIRECTION INPUT ;
    USE SIGNAL ;
    PORT
      LAYER M4 ;
        RECT  0 49.344 0.192 49.368 ;
    END
  END di[274]
  PIN di[275]
    DIRECTION INPUT ;
    USE SIGNAL ;
    PORT
      LAYER M4 ;
        RECT  0 49.488 0.192 49.512 ;
    END
  END di[275]
  PIN di[276]
    DIRECTION INPUT ;
    USE SIGNAL ;
    PORT
      LAYER M4 ;
        RECT  0 49.632 0.192 49.656 ;
    END
  END di[276]
  PIN di[277]
    DIRECTION INPUT ;
    USE SIGNAL ;
    PORT
      LAYER M4 ;
        RECT  0 49.824 0.192 49.848 ;
    END
  END di[277]
  PIN di[278]
    DIRECTION INPUT ;
    USE SIGNAL ;
    PORT
      LAYER M4 ;
        RECT  0 49.968 0.192 49.992 ;
    END
  END di[278]
  PIN di[279]
    DIRECTION INPUT ;
    USE SIGNAL ;
    PORT
      LAYER M4 ;
        RECT  0 50.16 0.192 50.184 ;
    END
  END di[279]
  PIN di[27]
    DIRECTION INPUT ;
    USE SIGNAL ;
    PORT
      LAYER M4 ;
        RECT  0 8.832 0.192 8.856 ;
    END
  END di[27]
  PIN di[280]
    DIRECTION INPUT ;
    USE SIGNAL ;
    PORT
      LAYER M4 ;
        RECT  0 50.304 0.192 50.328 ;
    END
  END di[280]
  PIN di[281]
    DIRECTION INPUT ;
    USE SIGNAL ;
    PORT
      LAYER M4 ;
        RECT  0 50.448 0.192 50.472 ;
    END
  END di[281]
  PIN di[282]
    DIRECTION INPUT ;
    USE SIGNAL ;
    PORT
      LAYER M4 ;
        RECT  0 50.64 0.192 50.664 ;
    END
  END di[282]
  PIN di[283]
    DIRECTION INPUT ;
    USE SIGNAL ;
    PORT
      LAYER M4 ;
        RECT  0 50.784 0.192 50.808 ;
    END
  END di[283]
  PIN di[284]
    DIRECTION INPUT ;
    USE SIGNAL ;
    PORT
      LAYER M4 ;
        RECT  0 50.976 0.192 51 ;
    END
  END di[284]
  PIN di[285]
    DIRECTION INPUT ;
    USE SIGNAL ;
    PORT
      LAYER M4 ;
        RECT  0 51.12 0.192 51.144 ;
    END
  END di[285]
  PIN di[286]
    DIRECTION INPUT ;
    USE SIGNAL ;
    PORT
      LAYER M4 ;
        RECT  0 51.264 0.192 51.288 ;
    END
  END di[286]
  PIN di[287]
    DIRECTION INPUT ;
    USE SIGNAL ;
    PORT
      LAYER M4 ;
        RECT  0 51.456 0.192 51.48 ;
    END
  END di[287]
  PIN di[288]
    DIRECTION INPUT ;
    USE SIGNAL ;
    PORT
      LAYER M4 ;
        RECT  0 51.6 0.192 51.624 ;
    END
  END di[288]
  PIN di[289]
    DIRECTION INPUT ;
    USE SIGNAL ;
    PORT
      LAYER M4 ;
        RECT  0 51.792 0.192 51.816 ;
    END
  END di[289]
  PIN di[28]
    DIRECTION INPUT ;
    USE SIGNAL ;
    PORT
      LAYER M4 ;
        RECT  0 9.024 0.192 9.048 ;
    END
  END di[28]
  PIN di[290]
    DIRECTION INPUT ;
    USE SIGNAL ;
    PORT
      LAYER M4 ;
        RECT  0 51.936 0.192 51.96 ;
    END
  END di[290]
  PIN di[291]
    DIRECTION INPUT ;
    USE SIGNAL ;
    PORT
      LAYER M4 ;
        RECT  0 52.128 0.192 52.152 ;
    END
  END di[291]
  PIN di[292]
    DIRECTION INPUT ;
    USE SIGNAL ;
    PORT
      LAYER M4 ;
        RECT  0 52.272 0.192 52.296 ;
    END
  END di[292]
  PIN di[293]
    DIRECTION INPUT ;
    USE SIGNAL ;
    PORT
      LAYER M4 ;
        RECT  0 52.416 0.192 52.44 ;
    END
  END di[293]
  PIN di[294]
    DIRECTION INPUT ;
    USE SIGNAL ;
    PORT
      LAYER M4 ;
        RECT  0 52.608 0.192 52.632 ;
    END
  END di[294]
  PIN di[295]
    DIRECTION INPUT ;
    USE SIGNAL ;
    PORT
      LAYER M4 ;
        RECT  0 52.752 0.192 52.776 ;
    END
  END di[295]
  PIN di[296]
    DIRECTION INPUT ;
    USE SIGNAL ;
    PORT
      LAYER M4 ;
        RECT  0 52.944 0.192 52.968 ;
    END
  END di[296]
  PIN di[297]
    DIRECTION INPUT ;
    USE SIGNAL ;
    PORT
      LAYER M4 ;
        RECT  0 53.088 0.192 53.112 ;
    END
  END di[297]
  PIN di[298]
    DIRECTION INPUT ;
    USE SIGNAL ;
    PORT
      LAYER M4 ;
        RECT  0 53.232 0.192 53.256 ;
    END
  END di[298]
  PIN di[299]
    DIRECTION INPUT ;
    USE SIGNAL ;
    PORT
      LAYER M4 ;
        RECT  0 53.424 0.192 53.448 ;
    END
  END di[299]
  PIN di[29]
    DIRECTION INPUT ;
    USE SIGNAL ;
    PORT
      LAYER M4 ;
        RECT  0 9.168 0.192 9.192 ;
    END
  END di[29]
  PIN di[2]
    DIRECTION INPUT ;
    USE SIGNAL ;
    PORT
      LAYER M4 ;
        RECT  0 4.752 0.192 4.776 ;
    END
  END di[2]
  PIN di[300]
    DIRECTION INPUT ;
    USE SIGNAL ;
    PORT
      LAYER M4 ;
        RECT  0 53.568 0.192 53.592 ;
    END
  END di[300]
  PIN di[301]
    DIRECTION INPUT ;
    USE SIGNAL ;
    PORT
      LAYER M4 ;
        RECT  0 53.76 0.192 53.784 ;
    END
  END di[301]
  PIN di[302]
    DIRECTION INPUT ;
    USE SIGNAL ;
    PORT
      LAYER M4 ;
        RECT  0 53.904 0.192 53.928 ;
    END
  END di[302]
  PIN di[303]
    DIRECTION INPUT ;
    USE SIGNAL ;
    PORT
      LAYER M4 ;
        RECT  0 54.096 0.192 54.12 ;
    END
  END di[303]
  PIN di[304]
    DIRECTION INPUT ;
    USE SIGNAL ;
    PORT
      LAYER M4 ;
        RECT  0 54.24 0.192 54.264 ;
    END
  END di[304]
  PIN di[305]
    DIRECTION INPUT ;
    USE SIGNAL ;
    PORT
      LAYER M4 ;
        RECT  0 54.384 0.192 54.408 ;
    END
  END di[305]
  PIN di[306]
    DIRECTION INPUT ;
    USE SIGNAL ;
    PORT
      LAYER M4 ;
        RECT  0 54.576 0.192 54.6 ;
    END
  END di[306]
  PIN di[307]
    DIRECTION INPUT ;
    USE SIGNAL ;
    PORT
      LAYER M4 ;
        RECT  0 54.72 0.192 54.744 ;
    END
  END di[307]
  PIN di[308]
    DIRECTION INPUT ;
    USE SIGNAL ;
    PORT
      LAYER M4 ;
        RECT  0 54.912 0.192 54.936 ;
    END
  END di[308]
  PIN di[309]
    DIRECTION INPUT ;
    USE SIGNAL ;
    PORT
      LAYER M4 ;
        RECT  0 55.056 0.192 55.08 ;
    END
  END di[309]
  PIN di[30]
    DIRECTION INPUT ;
    USE SIGNAL ;
    PORT
      LAYER M4 ;
        RECT  0 9.312 0.192 9.336 ;
    END
  END di[30]
  PIN di[310]
    DIRECTION INPUT ;
    USE SIGNAL ;
    PORT
      LAYER M4 ;
        RECT  0 55.2 0.192 55.224 ;
    END
  END di[310]
  PIN di[311]
    DIRECTION INPUT ;
    USE SIGNAL ;
    PORT
      LAYER M4 ;
        RECT  0 55.392 0.192 55.416 ;
    END
  END di[311]
  PIN di[312]
    DIRECTION INPUT ;
    USE SIGNAL ;
    PORT
      LAYER M4 ;
        RECT  0 55.536 0.192 55.56 ;
    END
  END di[312]
  PIN di[313]
    DIRECTION INPUT ;
    USE SIGNAL ;
    PORT
      LAYER M4 ;
        RECT  0 55.728 0.192 55.752 ;
    END
  END di[313]
  PIN di[314]
    DIRECTION INPUT ;
    USE SIGNAL ;
    PORT
      LAYER M4 ;
        RECT  0 55.872 0.192 55.896 ;
    END
  END di[314]
  PIN di[315]
    DIRECTION INPUT ;
    USE SIGNAL ;
    PORT
      LAYER M4 ;
        RECT  0 56.016 0.192 56.04 ;
    END
  END di[315]
  PIN di[316]
    DIRECTION INPUT ;
    USE SIGNAL ;
    PORT
      LAYER M4 ;
        RECT  0 56.208 0.192 56.232 ;
    END
  END di[316]
  PIN di[317]
    DIRECTION INPUT ;
    USE SIGNAL ;
    PORT
      LAYER M4 ;
        RECT  0 56.352 0.192 56.376 ;
    END
  END di[317]
  PIN di[318]
    DIRECTION INPUT ;
    USE SIGNAL ;
    PORT
      LAYER M4 ;
        RECT  0 56.544 0.192 56.568 ;
    END
  END di[318]
  PIN di[319]
    DIRECTION INPUT ;
    USE SIGNAL ;
    PORT
      LAYER M4 ;
        RECT  0 56.688 0.192 56.712 ;
    END
  END di[319]
  PIN di[31]
    DIRECTION INPUT ;
    USE SIGNAL ;
    PORT
      LAYER M4 ;
        RECT  0 9.504 0.192 9.528 ;
    END
  END di[31]
  PIN di[320]
    DIRECTION INPUT ;
    USE SIGNAL ;
    PORT
      LAYER M4 ;
        RECT  0 56.88 0.192 56.904 ;
    END
  END di[320]
  PIN di[321]
    DIRECTION INPUT ;
    USE SIGNAL ;
    PORT
      LAYER M4 ;
        RECT  0 57.024 0.192 57.048 ;
    END
  END di[321]
  PIN di[322]
    DIRECTION INPUT ;
    USE SIGNAL ;
    PORT
      LAYER M4 ;
        RECT  0 57.168 0.192 57.192 ;
    END
  END di[322]
  PIN di[323]
    DIRECTION INPUT ;
    USE SIGNAL ;
    PORT
      LAYER M4 ;
        RECT  0 57.36 0.192 57.384 ;
    END
  END di[323]
  PIN di[324]
    DIRECTION INPUT ;
    USE SIGNAL ;
    PORT
      LAYER M4 ;
        RECT  0 57.504 0.192 57.528 ;
    END
  END di[324]
  PIN di[325]
    DIRECTION INPUT ;
    USE SIGNAL ;
    PORT
      LAYER M4 ;
        RECT  0 57.696 0.192 57.72 ;
    END
  END di[325]
  PIN di[326]
    DIRECTION INPUT ;
    USE SIGNAL ;
    PORT
      LAYER M4 ;
        RECT  0 57.84 0.192 57.864 ;
    END
  END di[326]
  PIN di[327]
    DIRECTION INPUT ;
    USE SIGNAL ;
    PORT
      LAYER M4 ;
        RECT  0 57.984 0.192 58.008 ;
    END
  END di[327]
  PIN di[328]
    DIRECTION INPUT ;
    USE SIGNAL ;
    PORT
      LAYER M4 ;
        RECT  0 58.176 0.192 58.2 ;
    END
  END di[328]
  PIN di[329]
    DIRECTION INPUT ;
    USE SIGNAL ;
    PORT
      LAYER M4 ;
        RECT  0 58.32 0.192 58.344 ;
    END
  END di[329]
  PIN di[32]
    DIRECTION INPUT ;
    USE SIGNAL ;
    PORT
      LAYER M4 ;
        RECT  0 9.648 0.192 9.672 ;
    END
  END di[32]
  PIN di[330]
    DIRECTION INPUT ;
    USE SIGNAL ;
    PORT
      LAYER M4 ;
        RECT  0 58.512 0.192 58.536 ;
    END
  END di[330]
  PIN di[331]
    DIRECTION INPUT ;
    USE SIGNAL ;
    PORT
      LAYER M4 ;
        RECT  0 58.656 0.192 58.68 ;
    END
  END di[331]
  PIN di[332]
    DIRECTION INPUT ;
    USE SIGNAL ;
    PORT
      LAYER M4 ;
        RECT  0 58.848 0.192 58.872 ;
    END
  END di[332]
  PIN di[333]
    DIRECTION INPUT ;
    USE SIGNAL ;
    PORT
      LAYER M4 ;
        RECT  0 58.992 0.192 59.016 ;
    END
  END di[333]
  PIN di[334]
    DIRECTION INPUT ;
    USE SIGNAL ;
    PORT
      LAYER M4 ;
        RECT  0 59.136 0.192 59.16 ;
    END
  END di[334]
  PIN di[335]
    DIRECTION INPUT ;
    USE SIGNAL ;
    PORT
      LAYER M4 ;
        RECT  0 59.328 0.192 59.352 ;
    END
  END di[335]
  PIN di[336]
    DIRECTION INPUT ;
    USE SIGNAL ;
    PORT
      LAYER M4 ;
        RECT  0 59.472 0.192 59.496 ;
    END
  END di[336]
  PIN di[337]
    DIRECTION INPUT ;
    USE SIGNAL ;
    PORT
      LAYER M4 ;
        RECT  0 59.664 0.192 59.688 ;
    END
  END di[337]
  PIN di[338]
    DIRECTION INPUT ;
    USE SIGNAL ;
    PORT
      LAYER M4 ;
        RECT  0 59.808 0.192 59.832 ;
    END
  END di[338]
  PIN di[339]
    DIRECTION INPUT ;
    USE SIGNAL ;
    PORT
      LAYER M4 ;
        RECT  0 59.952 0.192 59.976 ;
    END
  END di[339]
  PIN di[33]
    DIRECTION INPUT ;
    USE SIGNAL ;
    PORT
      LAYER M4 ;
        RECT  0 9.84 0.192 9.864 ;
    END
  END di[33]
  PIN di[340]
    DIRECTION INPUT ;
    USE SIGNAL ;
    PORT
      LAYER M4 ;
        RECT  0 60.144 0.192 60.168 ;
    END
  END di[340]
  PIN di[341]
    DIRECTION INPUT ;
    USE SIGNAL ;
    PORT
      LAYER M4 ;
        RECT  0 60.288 0.192 60.312 ;
    END
  END di[341]
  PIN di[342]
    DIRECTION INPUT ;
    USE SIGNAL ;
    PORT
      LAYER M4 ;
        RECT  0 60.48 0.192 60.504 ;
    END
  END di[342]
  PIN di[343]
    DIRECTION INPUT ;
    USE SIGNAL ;
    PORT
      LAYER M4 ;
        RECT  0 60.624 0.192 60.648 ;
    END
  END di[343]
  PIN di[344]
    DIRECTION INPUT ;
    USE SIGNAL ;
    PORT
      LAYER M4 ;
        RECT  0 60.816 0.192 60.84 ;
    END
  END di[344]
  PIN di[345]
    DIRECTION INPUT ;
    USE SIGNAL ;
    PORT
      LAYER M4 ;
        RECT  0 60.96 0.192 60.984 ;
    END
  END di[345]
  PIN di[346]
    DIRECTION INPUT ;
    USE SIGNAL ;
    PORT
      LAYER M4 ;
        RECT  0 61.104 0.192 61.128 ;
    END
  END di[346]
  PIN di[347]
    DIRECTION INPUT ;
    USE SIGNAL ;
    PORT
      LAYER M4 ;
        RECT  0 61.296 0.192 61.32 ;
    END
  END di[347]
  PIN di[348]
    DIRECTION INPUT ;
    USE SIGNAL ;
    PORT
      LAYER M4 ;
        RECT  0 61.44 0.192 61.464 ;
    END
  END di[348]
  PIN di[349]
    DIRECTION INPUT ;
    USE SIGNAL ;
    PORT
      LAYER M4 ;
        RECT  0 61.632 0.192 61.656 ;
    END
  END di[349]
  PIN di[34]
    DIRECTION INPUT ;
    USE SIGNAL ;
    PORT
      LAYER M4 ;
        RECT  0 9.984 0.192 10.008 ;
    END
  END di[34]
  PIN di[350]
    DIRECTION INPUT ;
    USE SIGNAL ;
    PORT
      LAYER M4 ;
        RECT  0 61.776 0.192 61.8 ;
    END
  END di[350]
  PIN di[351]
    DIRECTION INPUT ;
    USE SIGNAL ;
    PORT
      LAYER M4 ;
        RECT  0 61.92 0.192 61.944 ;
    END
  END di[351]
  PIN di[352]
    DIRECTION INPUT ;
    USE SIGNAL ;
    PORT
      LAYER M4 ;
        RECT  0 62.112 0.192 62.136 ;
    END
  END di[352]
  PIN di[353]
    DIRECTION INPUT ;
    USE SIGNAL ;
    PORT
      LAYER M4 ;
        RECT  0 62.256 0.192 62.28 ;
    END
  END di[353]
  PIN di[354]
    DIRECTION INPUT ;
    USE SIGNAL ;
    PORT
      LAYER M4 ;
        RECT  0 62.448 0.192 62.472 ;
    END
  END di[354]
  PIN di[355]
    DIRECTION INPUT ;
    USE SIGNAL ;
    PORT
      LAYER M4 ;
        RECT  0 62.592 0.192 62.616 ;
    END
  END di[355]
  PIN di[356]
    DIRECTION INPUT ;
    USE SIGNAL ;
    PORT
      LAYER M4 ;
        RECT  0 62.736 0.192 62.76 ;
    END
  END di[356]
  PIN di[357]
    DIRECTION INPUT ;
    USE SIGNAL ;
    PORT
      LAYER M4 ;
        RECT  0 62.928 0.192 62.952 ;
    END
  END di[357]
  PIN di[358]
    DIRECTION INPUT ;
    USE SIGNAL ;
    PORT
      LAYER M4 ;
        RECT  0 63.072 0.192 63.096 ;
    END
  END di[358]
  PIN di[359]
    DIRECTION INPUT ;
    USE SIGNAL ;
    PORT
      LAYER M4 ;
        RECT  0 63.264 0.192 63.288 ;
    END
  END di[359]
  PIN di[35]
    DIRECTION INPUT ;
    USE SIGNAL ;
    PORT
      LAYER M4 ;
        RECT  0 10.128 0.192 10.152 ;
    END
  END di[35]
  PIN di[360]
    DIRECTION INPUT ;
    USE SIGNAL ;
    PORT
      LAYER M4 ;
        RECT  0 63.408 0.192 63.432 ;
    END
  END di[360]
  PIN di[361]
    DIRECTION INPUT ;
    USE SIGNAL ;
    PORT
      LAYER M4 ;
        RECT  0 63.6 0.192 63.624 ;
    END
  END di[361]
  PIN di[362]
    DIRECTION INPUT ;
    USE SIGNAL ;
    PORT
      LAYER M4 ;
        RECT  0 63.744 0.192 63.768 ;
    END
  END di[362]
  PIN di[363]
    DIRECTION INPUT ;
    USE SIGNAL ;
    PORT
      LAYER M4 ;
        RECT  0 63.888 0.192 63.912 ;
    END
  END di[363]
  PIN di[364]
    DIRECTION INPUT ;
    USE SIGNAL ;
    PORT
      LAYER M4 ;
        RECT  0 64.08 0.192 64.104 ;
    END
  END di[364]
  PIN di[365]
    DIRECTION INPUT ;
    USE SIGNAL ;
    PORT
      LAYER M4 ;
        RECT  0 64.224 0.192 64.248 ;
    END
  END di[365]
  PIN di[366]
    DIRECTION INPUT ;
    USE SIGNAL ;
    PORT
      LAYER M4 ;
        RECT  0 64.416 0.192 64.44 ;
    END
  END di[366]
  PIN di[367]
    DIRECTION INPUT ;
    USE SIGNAL ;
    PORT
      LAYER M4 ;
        RECT  0 64.56 0.192 64.584 ;
    END
  END di[367]
  PIN di[368]
    DIRECTION INPUT ;
    USE SIGNAL ;
    PORT
      LAYER M4 ;
        RECT  0 64.704 0.192 64.728 ;
    END
  END di[368]
  PIN di[369]
    DIRECTION INPUT ;
    USE SIGNAL ;
    PORT
      LAYER M4 ;
        RECT  0 64.896 0.192 64.92 ;
    END
  END di[369]
  PIN di[36]
    DIRECTION INPUT ;
    USE SIGNAL ;
    PORT
      LAYER M4 ;
        RECT  0 10.32 0.192 10.344 ;
    END
  END di[36]
  PIN di[370]
    DIRECTION INPUT ;
    USE SIGNAL ;
    PORT
      LAYER M4 ;
        RECT  0 65.04 0.192 65.064 ;
    END
  END di[370]
  PIN di[371]
    DIRECTION INPUT ;
    USE SIGNAL ;
    PORT
      LAYER M4 ;
        RECT  0 65.232 0.192 65.256 ;
    END
  END di[371]
  PIN di[372]
    DIRECTION INPUT ;
    USE SIGNAL ;
    PORT
      LAYER M4 ;
        RECT  0 65.376 0.192 65.4 ;
    END
  END di[372]
  PIN di[373]
    DIRECTION INPUT ;
    USE SIGNAL ;
    PORT
      LAYER M4 ;
        RECT  0 65.568 0.192 65.592 ;
    END
  END di[373]
  PIN di[374]
    DIRECTION INPUT ;
    USE SIGNAL ;
    PORT
      LAYER M4 ;
        RECT  0 65.712 0.192 65.736 ;
    END
  END di[374]
  PIN di[375]
    DIRECTION INPUT ;
    USE SIGNAL ;
    PORT
      LAYER M4 ;
        RECT  0 65.856 0.192 65.88 ;
    END
  END di[375]
  PIN di[376]
    DIRECTION INPUT ;
    USE SIGNAL ;
    PORT
      LAYER M4 ;
        RECT  0 66.048 0.192 66.072 ;
    END
  END di[376]
  PIN di[377]
    DIRECTION INPUT ;
    USE SIGNAL ;
    PORT
      LAYER M4 ;
        RECT  0 66.192 0.192 66.216 ;
    END
  END di[377]
  PIN di[378]
    DIRECTION INPUT ;
    USE SIGNAL ;
    PORT
      LAYER M4 ;
        RECT  0 66.384 0.192 66.408 ;
    END
  END di[378]
  PIN di[379]
    DIRECTION INPUT ;
    USE SIGNAL ;
    PORT
      LAYER M4 ;
        RECT  0 66.528 0.192 66.552 ;
    END
  END di[379]
  PIN di[37]
    DIRECTION INPUT ;
    USE SIGNAL ;
    PORT
      LAYER M4 ;
        RECT  0 10.464 0.192 10.488 ;
    END
  END di[37]
  PIN di[380]
    DIRECTION INPUT ;
    USE SIGNAL ;
    PORT
      LAYER M4 ;
        RECT  0 66.672 0.192 66.696 ;
    END
  END di[380]
  PIN di[381]
    DIRECTION INPUT ;
    USE SIGNAL ;
    PORT
      LAYER M4 ;
        RECT  0 66.864 0.192 66.888 ;
    END
  END di[381]
  PIN di[382]
    DIRECTION INPUT ;
    USE SIGNAL ;
    PORT
      LAYER M4 ;
        RECT  0 67.008 0.192 67.032 ;
    END
  END di[382]
  PIN di[383]
    DIRECTION INPUT ;
    USE SIGNAL ;
    PORT
      LAYER M4 ;
        RECT  0 67.2 0.192 67.224 ;
    END
  END di[383]
  PIN di[384]
    DIRECTION INPUT ;
    USE SIGNAL ;
    PORT
      LAYER M4 ;
        RECT  0 67.344 0.192 67.368 ;
    END
  END di[384]
  PIN di[385]
    DIRECTION INPUT ;
    USE SIGNAL ;
    PORT
      LAYER M4 ;
        RECT  0 67.536 0.192 67.56 ;
    END
  END di[385]
  PIN di[386]
    DIRECTION INPUT ;
    USE SIGNAL ;
    PORT
      LAYER M4 ;
        RECT  0 67.68 0.192 67.704 ;
    END
  END di[386]
  PIN di[387]
    DIRECTION INPUT ;
    USE SIGNAL ;
    PORT
      LAYER M4 ;
        RECT  0 67.824 0.192 67.848 ;
    END
  END di[387]
  PIN di[388]
    DIRECTION INPUT ;
    USE SIGNAL ;
    PORT
      LAYER M4 ;
        RECT  0 68.016 0.192 68.04 ;
    END
  END di[388]
  PIN di[389]
    DIRECTION INPUT ;
    USE SIGNAL ;
    PORT
      LAYER M4 ;
        RECT  0 68.16 0.192 68.184 ;
    END
  END di[389]
  PIN di[38]
    DIRECTION INPUT ;
    USE SIGNAL ;
    PORT
      LAYER M4 ;
        RECT  0 10.656 0.192 10.68 ;
    END
  END di[38]
  PIN di[390]
    DIRECTION INPUT ;
    USE SIGNAL ;
    PORT
      LAYER M4 ;
        RECT  0 68.352 0.192 68.376 ;
    END
  END di[390]
  PIN di[391]
    DIRECTION INPUT ;
    USE SIGNAL ;
    PORT
      LAYER M4 ;
        RECT  0 68.496 0.192 68.52 ;
    END
  END di[391]
  PIN di[392]
    DIRECTION INPUT ;
    USE SIGNAL ;
    PORT
      LAYER M4 ;
        RECT  0 68.64 0.192 68.664 ;
    END
  END di[392]
  PIN di[393]
    DIRECTION INPUT ;
    USE SIGNAL ;
    PORT
      LAYER M4 ;
        RECT  0 68.832 0.192 68.856 ;
    END
  END di[393]
  PIN di[394]
    DIRECTION INPUT ;
    USE SIGNAL ;
    PORT
      LAYER M4 ;
        RECT  0 68.976 0.192 69 ;
    END
  END di[394]
  PIN di[395]
    DIRECTION INPUT ;
    USE SIGNAL ;
    PORT
      LAYER M4 ;
        RECT  0 69.168 0.192 69.192 ;
    END
  END di[395]
  PIN di[396]
    DIRECTION INPUT ;
    USE SIGNAL ;
    PORT
      LAYER M4 ;
        RECT  0 69.312 0.192 69.336 ;
    END
  END di[396]
  PIN di[397]
    DIRECTION INPUT ;
    USE SIGNAL ;
    PORT
      LAYER M4 ;
        RECT  0 69.456 0.192 69.48 ;
    END
  END di[397]
  PIN di[398]
    DIRECTION INPUT ;
    USE SIGNAL ;
    PORT
      LAYER M4 ;
        RECT  0 69.648 0.192 69.672 ;
    END
  END di[398]
  PIN di[399]
    DIRECTION INPUT ;
    USE SIGNAL ;
    PORT
      LAYER M4 ;
        RECT  0 69.792 0.192 69.816 ;
    END
  END di[399]
  PIN di[39]
    DIRECTION INPUT ;
    USE SIGNAL ;
    PORT
      LAYER M4 ;
        RECT  0 10.8 0.192 10.824 ;
    END
  END di[39]
  PIN di[3]
    DIRECTION INPUT ;
    USE SIGNAL ;
    PORT
      LAYER M4 ;
        RECT  0 4.896 0.192 4.92 ;
    END
  END di[3]
  PIN di[400]
    DIRECTION INPUT ;
    USE SIGNAL ;
    PORT
      LAYER M4 ;
        RECT  0 69.984 0.192 70.008 ;
    END
  END di[400]
  PIN di[401]
    DIRECTION INPUT ;
    USE SIGNAL ;
    PORT
      LAYER M4 ;
        RECT  0 70.128 0.192 70.152 ;
    END
  END di[401]
  PIN di[402]
    DIRECTION INPUT ;
    USE SIGNAL ;
    PORT
      LAYER M4 ;
        RECT  0 70.32 0.192 70.344 ;
    END
  END di[402]
  PIN di[403]
    DIRECTION INPUT ;
    USE SIGNAL ;
    PORT
      LAYER M4 ;
        RECT  0 70.464 0.192 70.488 ;
    END
  END di[403]
  PIN di[404]
    DIRECTION INPUT ;
    USE SIGNAL ;
    PORT
      LAYER M4 ;
        RECT  0 70.608 0.192 70.632 ;
    END
  END di[404]
  PIN di[405]
    DIRECTION INPUT ;
    USE SIGNAL ;
    PORT
      LAYER M4 ;
        RECT  0 70.8 0.192 70.824 ;
    END
  END di[405]
  PIN di[406]
    DIRECTION INPUT ;
    USE SIGNAL ;
    PORT
      LAYER M4 ;
        RECT  0 70.944 0.192 70.968 ;
    END
  END di[406]
  PIN di[407]
    DIRECTION INPUT ;
    USE SIGNAL ;
    PORT
      LAYER M4 ;
        RECT  0 71.136 0.192 71.16 ;
    END
  END di[407]
  PIN di[408]
    DIRECTION INPUT ;
    USE SIGNAL ;
    PORT
      LAYER M4 ;
        RECT  0 71.28 0.192 71.304 ;
    END
  END di[408]
  PIN di[409]
    DIRECTION INPUT ;
    USE SIGNAL ;
    PORT
      LAYER M4 ;
        RECT  0 71.424 0.192 71.448 ;
    END
  END di[409]
  PIN di[40]
    DIRECTION INPUT ;
    USE SIGNAL ;
    PORT
      LAYER M4 ;
        RECT  0 10.992 0.192 11.016 ;
    END
  END di[40]
  PIN di[410]
    DIRECTION INPUT ;
    USE SIGNAL ;
    PORT
      LAYER M4 ;
        RECT  0 71.616 0.192 71.64 ;
    END
  END di[410]
  PIN di[411]
    DIRECTION INPUT ;
    USE SIGNAL ;
    PORT
      LAYER M4 ;
        RECT  0 71.76 0.192 71.784 ;
    END
  END di[411]
  PIN di[412]
    DIRECTION INPUT ;
    USE SIGNAL ;
    PORT
      LAYER M4 ;
        RECT  0 71.952 0.192 71.976 ;
    END
  END di[412]
  PIN di[413]
    DIRECTION INPUT ;
    USE SIGNAL ;
    PORT
      LAYER M4 ;
        RECT  0 72.096 0.192 72.12 ;
    END
  END di[413]
  PIN di[414]
    DIRECTION INPUT ;
    USE SIGNAL ;
    PORT
      LAYER M4 ;
        RECT  0 72.288 0.192 72.312 ;
    END
  END di[414]
  PIN di[415]
    DIRECTION INPUT ;
    USE SIGNAL ;
    PORT
      LAYER M4 ;
        RECT  0 72.432 0.192 72.456 ;
    END
  END di[415]
  PIN di[416]
    DIRECTION INPUT ;
    USE SIGNAL ;
    PORT
      LAYER M4 ;
        RECT  0 72.576 0.192 72.6 ;
    END
  END di[416]
  PIN di[417]
    DIRECTION INPUT ;
    USE SIGNAL ;
    PORT
      LAYER M4 ;
        RECT  0 72.768 0.192 72.792 ;
    END
  END di[417]
  PIN di[418]
    DIRECTION INPUT ;
    USE SIGNAL ;
    PORT
      LAYER M4 ;
        RECT  0 72.912 0.192 72.936 ;
    END
  END di[418]
  PIN di[419]
    DIRECTION INPUT ;
    USE SIGNAL ;
    PORT
      LAYER M4 ;
        RECT  0 73.104 0.192 73.128 ;
    END
  END di[419]
  PIN di[41]
    DIRECTION INPUT ;
    USE SIGNAL ;
    PORT
      LAYER M4 ;
        RECT  0 11.136 0.192 11.16 ;
    END
  END di[41]
  PIN di[420]
    DIRECTION INPUT ;
    USE SIGNAL ;
    PORT
      LAYER M4 ;
        RECT  0 73.248 0.192 73.272 ;
    END
  END di[420]
  PIN di[421]
    DIRECTION INPUT ;
    USE SIGNAL ;
    PORT
      LAYER M4 ;
        RECT  0 73.392 0.192 73.416 ;
    END
  END di[421]
  PIN di[422]
    DIRECTION INPUT ;
    USE SIGNAL ;
    PORT
      LAYER M4 ;
        RECT  0 73.584 0.192 73.608 ;
    END
  END di[422]
  PIN di[423]
    DIRECTION INPUT ;
    USE SIGNAL ;
    PORT
      LAYER M4 ;
        RECT  0 73.728 0.192 73.752 ;
    END
  END di[423]
  PIN di[424]
    DIRECTION INPUT ;
    USE SIGNAL ;
    PORT
      LAYER M4 ;
        RECT  0 73.92 0.192 73.944 ;
    END
  END di[424]
  PIN di[425]
    DIRECTION INPUT ;
    USE SIGNAL ;
    PORT
      LAYER M4 ;
        RECT  0 74.064 0.192 74.088 ;
    END
  END di[425]
  PIN di[426]
    DIRECTION INPUT ;
    USE SIGNAL ;
    PORT
      LAYER M4 ;
        RECT  0 74.208 0.192 74.232 ;
    END
  END di[426]
  PIN di[427]
    DIRECTION INPUT ;
    USE SIGNAL ;
    PORT
      LAYER M4 ;
        RECT  0 74.4 0.192 74.424 ;
    END
  END di[427]
  PIN di[428]
    DIRECTION INPUT ;
    USE SIGNAL ;
    PORT
      LAYER M4 ;
        RECT  0 74.544 0.192 74.568 ;
    END
  END di[428]
  PIN di[429]
    DIRECTION INPUT ;
    USE SIGNAL ;
    PORT
      LAYER M4 ;
        RECT  0 74.736 0.192 74.76 ;
    END
  END di[429]
  PIN di[42]
    DIRECTION INPUT ;
    USE SIGNAL ;
    PORT
      LAYER M4 ;
        RECT  0 11.28 0.192 11.304 ;
    END
  END di[42]
  PIN di[430]
    DIRECTION INPUT ;
    USE SIGNAL ;
    PORT
      LAYER M4 ;
        RECT  0 74.88 0.192 74.904 ;
    END
  END di[430]
  PIN di[431]
    DIRECTION INPUT ;
    USE SIGNAL ;
    PORT
      LAYER M4 ;
        RECT  0 75.072 0.192 75.096 ;
    END
  END di[431]
  PIN di[432]
    DIRECTION INPUT ;
    USE SIGNAL ;
    PORT
      LAYER M4 ;
        RECT  0 75.216 0.192 75.24 ;
    END
  END di[432]
  PIN di[433]
    DIRECTION INPUT ;
    USE SIGNAL ;
    PORT
      LAYER M4 ;
        RECT  0 75.36 0.192 75.384 ;
    END
  END di[433]
  PIN di[434]
    DIRECTION INPUT ;
    USE SIGNAL ;
    PORT
      LAYER M4 ;
        RECT  0 75.552 0.192 75.576 ;
    END
  END di[434]
  PIN di[435]
    DIRECTION INPUT ;
    USE SIGNAL ;
    PORT
      LAYER M4 ;
        RECT  0 75.696 0.192 75.72 ;
    END
  END di[435]
  PIN di[436]
    DIRECTION INPUT ;
    USE SIGNAL ;
    PORT
      LAYER M4 ;
        RECT  0 75.888 0.192 75.912 ;
    END
  END di[436]
  PIN di[437]
    DIRECTION INPUT ;
    USE SIGNAL ;
    PORT
      LAYER M4 ;
        RECT  0 76.032 0.192 76.056 ;
    END
  END di[437]
  PIN di[438]
    DIRECTION INPUT ;
    USE SIGNAL ;
    PORT
      LAYER M4 ;
        RECT  0 76.176 0.192 76.2 ;
    END
  END di[438]
  PIN di[439]
    DIRECTION INPUT ;
    USE SIGNAL ;
    PORT
      LAYER M4 ;
        RECT  0 76.368 0.192 76.392 ;
    END
  END di[439]
  PIN di[43]
    DIRECTION INPUT ;
    USE SIGNAL ;
    PORT
      LAYER M4 ;
        RECT  0 11.472 0.192 11.496 ;
    END
  END di[43]
  PIN di[440]
    DIRECTION INPUT ;
    USE SIGNAL ;
    PORT
      LAYER M4 ;
        RECT  0 76.512 0.192 76.536 ;
    END
  END di[440]
  PIN di[441]
    DIRECTION INPUT ;
    USE SIGNAL ;
    PORT
      LAYER M4 ;
        RECT  0 76.704 0.192 76.728 ;
    END
  END di[441]
  PIN di[442]
    DIRECTION INPUT ;
    USE SIGNAL ;
    PORT
      LAYER M4 ;
        RECT  0 76.848 0.192 76.872 ;
    END
  END di[442]
  PIN di[443]
    DIRECTION INPUT ;
    USE SIGNAL ;
    PORT
      LAYER M4 ;
        RECT  0 77.04 0.192 77.064 ;
    END
  END di[443]
  PIN di[444]
    DIRECTION INPUT ;
    USE SIGNAL ;
    PORT
      LAYER M4 ;
        RECT  0 77.184 0.192 77.208 ;
    END
  END di[444]
  PIN di[445]
    DIRECTION INPUT ;
    USE SIGNAL ;
    PORT
      LAYER M4 ;
        RECT  0 77.328 0.192 77.352 ;
    END
  END di[445]
  PIN di[446]
    DIRECTION INPUT ;
    USE SIGNAL ;
    PORT
      LAYER M4 ;
        RECT  0 77.52 0.192 77.544 ;
    END
  END di[446]
  PIN di[447]
    DIRECTION INPUT ;
    USE SIGNAL ;
    PORT
      LAYER M4 ;
        RECT  0 77.664 0.192 77.688 ;
    END
  END di[447]
  PIN di[448]
    DIRECTION INPUT ;
    USE SIGNAL ;
    PORT
      LAYER M4 ;
        RECT  0 77.856 0.192 77.88 ;
    END
  END di[448]
  PIN di[449]
    DIRECTION INPUT ;
    USE SIGNAL ;
    PORT
      LAYER M4 ;
        RECT  0 78 0.192 78.024 ;
    END
  END di[449]
  PIN di[44]
    DIRECTION INPUT ;
    USE SIGNAL ;
    PORT
      LAYER M4 ;
        RECT  0 11.616 0.192 11.64 ;
    END
  END di[44]
  PIN di[450]
    DIRECTION INPUT ;
    USE SIGNAL ;
    PORT
      LAYER M4 ;
        RECT  0 78.144 0.192 78.168 ;
    END
  END di[450]
  PIN di[451]
    DIRECTION INPUT ;
    USE SIGNAL ;
    PORT
      LAYER M4 ;
        RECT  0 78.336 0.192 78.36 ;
    END
  END di[451]
  PIN di[452]
    DIRECTION INPUT ;
    USE SIGNAL ;
    PORT
      LAYER M4 ;
        RECT  0 78.48 0.192 78.504 ;
    END
  END di[452]
  PIN di[453]
    DIRECTION INPUT ;
    USE SIGNAL ;
    PORT
      LAYER M4 ;
        RECT  0 78.672 0.192 78.696 ;
    END
  END di[453]
  PIN di[454]
    DIRECTION INPUT ;
    USE SIGNAL ;
    PORT
      LAYER M4 ;
        RECT  0 78.816 0.192 78.84 ;
    END
  END di[454]
  PIN di[455]
    DIRECTION INPUT ;
    USE SIGNAL ;
    PORT
      LAYER M4 ;
        RECT  0 79.008 0.192 79.032 ;
    END
  END di[455]
  PIN di[456]
    DIRECTION INPUT ;
    USE SIGNAL ;
    PORT
      LAYER M4 ;
        RECT  0 79.152 0.192 79.176 ;
    END
  END di[456]
  PIN di[457]
    DIRECTION INPUT ;
    USE SIGNAL ;
    PORT
      LAYER M4 ;
        RECT  0 79.296 0.192 79.32 ;
    END
  END di[457]
  PIN di[458]
    DIRECTION INPUT ;
    USE SIGNAL ;
    PORT
      LAYER M4 ;
        RECT  0 79.488 0.192 79.512 ;
    END
  END di[458]
  PIN di[459]
    DIRECTION INPUT ;
    USE SIGNAL ;
    PORT
      LAYER M4 ;
        RECT  0 79.632 0.192 79.656 ;
    END
  END di[459]
  PIN di[45]
    DIRECTION INPUT ;
    USE SIGNAL ;
    PORT
      LAYER M4 ;
        RECT  0 11.808 0.192 11.832 ;
    END
  END di[45]
  PIN di[460]
    DIRECTION INPUT ;
    USE SIGNAL ;
    PORT
      LAYER M4 ;
        RECT  0 79.824 0.192 79.848 ;
    END
  END di[460]
  PIN di[461]
    DIRECTION INPUT ;
    USE SIGNAL ;
    PORT
      LAYER M4 ;
        RECT  0 79.968 0.192 79.992 ;
    END
  END di[461]
  PIN di[462]
    DIRECTION INPUT ;
    USE SIGNAL ;
    PORT
      LAYER M4 ;
        RECT  0 80.112 0.192 80.136 ;
    END
  END di[462]
  PIN di[463]
    DIRECTION INPUT ;
    USE SIGNAL ;
    PORT
      LAYER M4 ;
        RECT  0 80.304 0.192 80.328 ;
    END
  END di[463]
  PIN di[464]
    DIRECTION INPUT ;
    USE SIGNAL ;
    PORT
      LAYER M4 ;
        RECT  0 80.448 0.192 80.472 ;
    END
  END di[464]
  PIN di[465]
    DIRECTION INPUT ;
    USE SIGNAL ;
    PORT
      LAYER M4 ;
        RECT  0 80.64 0.192 80.664 ;
    END
  END di[465]
  PIN di[466]
    DIRECTION INPUT ;
    USE SIGNAL ;
    PORT
      LAYER M4 ;
        RECT  0 80.784 0.192 80.808 ;
    END
  END di[466]
  PIN di[467]
    DIRECTION INPUT ;
    USE SIGNAL ;
    PORT
      LAYER M4 ;
        RECT  0 80.928 0.192 80.952 ;
    END
  END di[467]
  PIN di[468]
    DIRECTION INPUT ;
    USE SIGNAL ;
    PORT
      LAYER M4 ;
        RECT  0 81.12 0.192 81.144 ;
    END
  END di[468]
  PIN di[469]
    DIRECTION INPUT ;
    USE SIGNAL ;
    PORT
      LAYER M4 ;
        RECT  0 81.264 0.192 81.288 ;
    END
  END di[469]
  PIN di[46]
    DIRECTION INPUT ;
    USE SIGNAL ;
    PORT
      LAYER M4 ;
        RECT  0 11.952 0.192 11.976 ;
    END
  END di[46]
  PIN di[470]
    DIRECTION INPUT ;
    USE SIGNAL ;
    PORT
      LAYER M4 ;
        RECT  0 81.456 0.192 81.48 ;
    END
  END di[470]
  PIN di[471]
    DIRECTION INPUT ;
    USE SIGNAL ;
    PORT
      LAYER M4 ;
        RECT  0 81.6 0.192 81.624 ;
    END
  END di[471]
  PIN di[472]
    DIRECTION INPUT ;
    USE SIGNAL ;
    PORT
      LAYER M4 ;
        RECT  0 81.792 0.192 81.816 ;
    END
  END di[472]
  PIN di[473]
    DIRECTION INPUT ;
    USE SIGNAL ;
    PORT
      LAYER M4 ;
        RECT  0 81.936 0.192 81.96 ;
    END
  END di[473]
  PIN di[474]
    DIRECTION INPUT ;
    USE SIGNAL ;
    PORT
      LAYER M4 ;
        RECT  0 82.08 0.192 82.104 ;
    END
  END di[474]
  PIN di[475]
    DIRECTION INPUT ;
    USE SIGNAL ;
    PORT
      LAYER M4 ;
        RECT  0 82.272 0.192 82.296 ;
    END
  END di[475]
  PIN di[476]
    DIRECTION INPUT ;
    USE SIGNAL ;
    PORT
      LAYER M4 ;
        RECT  0 82.416 0.192 82.44 ;
    END
  END di[476]
  PIN di[477]
    DIRECTION INPUT ;
    USE SIGNAL ;
    PORT
      LAYER M4 ;
        RECT  0 82.608 0.192 82.632 ;
    END
  END di[477]
  PIN di[478]
    DIRECTION INPUT ;
    USE SIGNAL ;
    PORT
      LAYER M4 ;
        RECT  0 82.752 0.192 82.776 ;
    END
  END di[478]
  PIN di[479]
    DIRECTION INPUT ;
    USE SIGNAL ;
    PORT
      LAYER M4 ;
        RECT  0 82.896 0.192 82.92 ;
    END
  END di[479]
  PIN di[47]
    DIRECTION INPUT ;
    USE SIGNAL ;
    PORT
      LAYER M4 ;
        RECT  0 12.096 0.192 12.12 ;
    END
  END di[47]
  PIN di[480]
    DIRECTION INPUT ;
    USE SIGNAL ;
    PORT
      LAYER M4 ;
        RECT  0 83.088 0.192 83.112 ;
    END
  END di[480]
  PIN di[481]
    DIRECTION INPUT ;
    USE SIGNAL ;
    PORT
      LAYER M4 ;
        RECT  0 83.232 0.192 83.256 ;
    END
  END di[481]
  PIN di[482]
    DIRECTION INPUT ;
    USE SIGNAL ;
    PORT
      LAYER M4 ;
        RECT  0 83.424 0.192 83.448 ;
    END
  END di[482]
  PIN di[483]
    DIRECTION INPUT ;
    USE SIGNAL ;
    PORT
      LAYER M4 ;
        RECT  0 83.568 0.192 83.592 ;
    END
  END di[483]
  PIN di[484]
    DIRECTION INPUT ;
    USE SIGNAL ;
    PORT
      LAYER M4 ;
        RECT  0 83.76 0.192 83.784 ;
    END
  END di[484]
  PIN di[485]
    DIRECTION INPUT ;
    USE SIGNAL ;
    PORT
      LAYER M4 ;
        RECT  0 83.904 0.192 83.928 ;
    END
  END di[485]
  PIN di[486]
    DIRECTION INPUT ;
    USE SIGNAL ;
    PORT
      LAYER M4 ;
        RECT  0 84.048 0.192 84.072 ;
    END
  END di[486]
  PIN di[487]
    DIRECTION INPUT ;
    USE SIGNAL ;
    PORT
      LAYER M4 ;
        RECT  0 84.24 0.192 84.264 ;
    END
  END di[487]
  PIN di[488]
    DIRECTION INPUT ;
    USE SIGNAL ;
    PORT
      LAYER M4 ;
        RECT  0 84.384 0.192 84.408 ;
    END
  END di[488]
  PIN di[489]
    DIRECTION INPUT ;
    USE SIGNAL ;
    PORT
      LAYER M4 ;
        RECT  0 84.576 0.192 84.6 ;
    END
  END di[489]
  PIN di[48]
    DIRECTION INPUT ;
    USE SIGNAL ;
    PORT
      LAYER M4 ;
        RECT  0 12.288 0.192 12.312 ;
    END
  END di[48]
  PIN di[490]
    DIRECTION INPUT ;
    USE SIGNAL ;
    PORT
      LAYER M4 ;
        RECT  0 84.72 0.192 84.744 ;
    END
  END di[490]
  PIN di[491]
    DIRECTION INPUT ;
    USE SIGNAL ;
    PORT
      LAYER M4 ;
        RECT  0 84.864 0.192 84.888 ;
    END
  END di[491]
  PIN di[492]
    DIRECTION INPUT ;
    USE SIGNAL ;
    PORT
      LAYER M4 ;
        RECT  0 85.056 0.192 85.08 ;
    END
  END di[492]
  PIN di[493]
    DIRECTION INPUT ;
    USE SIGNAL ;
    PORT
      LAYER M4 ;
        RECT  0 85.2 0.192 85.224 ;
    END
  END di[493]
  PIN di[494]
    DIRECTION INPUT ;
    USE SIGNAL ;
    PORT
      LAYER M4 ;
        RECT  0 85.392 0.192 85.416 ;
    END
  END di[494]
  PIN di[495]
    DIRECTION INPUT ;
    USE SIGNAL ;
    PORT
      LAYER M4 ;
        RECT  0 85.536 0.192 85.56 ;
    END
  END di[495]
  PIN di[496]
    DIRECTION INPUT ;
    USE SIGNAL ;
    PORT
      LAYER M4 ;
        RECT  0 85.68 0.192 85.704 ;
    END
  END di[496]
  PIN di[497]
    DIRECTION INPUT ;
    USE SIGNAL ;
    PORT
      LAYER M4 ;
        RECT  0 85.872 0.192 85.896 ;
    END
  END di[497]
  PIN di[498]
    DIRECTION INPUT ;
    USE SIGNAL ;
    PORT
      LAYER M4 ;
        RECT  0 86.016 0.192 86.04 ;
    END
  END di[498]
  PIN di[499]
    DIRECTION INPUT ;
    USE SIGNAL ;
    PORT
      LAYER M4 ;
        RECT  0 86.208 0.192 86.232 ;
    END
  END di[499]
  PIN di[49]
    DIRECTION INPUT ;
    USE SIGNAL ;
    PORT
      LAYER M4 ;
        RECT  0 12.432 0.192 12.456 ;
    END
  END di[49]
  PIN di[4]
    DIRECTION INPUT ;
    USE SIGNAL ;
    PORT
      LAYER M4 ;
        RECT  0 5.088 0.192 5.112 ;
    END
  END di[4]
  PIN di[500]
    DIRECTION INPUT ;
    USE SIGNAL ;
    PORT
      LAYER M4 ;
        RECT  0 86.352 0.192 86.376 ;
    END
  END di[500]
  PIN di[501]
    DIRECTION INPUT ;
    USE SIGNAL ;
    PORT
      LAYER M4 ;
        RECT  0 86.544 0.192 86.568 ;
    END
  END di[501]
  PIN di[502]
    DIRECTION INPUT ;
    USE SIGNAL ;
    PORT
      LAYER M4 ;
        RECT  0 86.688 0.192 86.712 ;
    END
  END di[502]
  PIN di[503]
    DIRECTION INPUT ;
    USE SIGNAL ;
    PORT
      LAYER M4 ;
        RECT  0 86.832 0.192 86.856 ;
    END
  END di[503]
  PIN di[504]
    DIRECTION INPUT ;
    USE SIGNAL ;
    PORT
      LAYER M4 ;
        RECT  0 87.024 0.192 87.048 ;
    END
  END di[504]
  PIN di[505]
    DIRECTION INPUT ;
    USE SIGNAL ;
    PORT
      LAYER M4 ;
        RECT  0 87.168 0.192 87.192 ;
    END
  END di[505]
  PIN di[506]
    DIRECTION INPUT ;
    USE SIGNAL ;
    PORT
      LAYER M4 ;
        RECT  0 87.36 0.192 87.384 ;
    END
  END di[506]
  PIN di[507]
    DIRECTION INPUT ;
    USE SIGNAL ;
    PORT
      LAYER M4 ;
        RECT  0 87.504 0.192 87.528 ;
    END
  END di[507]
  PIN di[508]
    DIRECTION INPUT ;
    USE SIGNAL ;
    PORT
      LAYER M4 ;
        RECT  0 87.648 0.192 87.672 ;
    END
  END di[508]
  PIN di[509]
    DIRECTION INPUT ;
    USE SIGNAL ;
    PORT
      LAYER M4 ;
        RECT  0 87.84 0.192 87.864 ;
    END
  END di[509]
  PIN di[50]
    DIRECTION INPUT ;
    USE SIGNAL ;
    PORT
      LAYER M4 ;
        RECT  0 12.624 0.192 12.648 ;
    END
  END di[50]
  PIN di[510]
    DIRECTION INPUT ;
    USE SIGNAL ;
    PORT
      LAYER M4 ;
        RECT  0 87.984 0.192 88.008 ;
    END
  END di[510]
  PIN di[511]
    DIRECTION INPUT ;
    USE SIGNAL ;
    PORT
      LAYER M4 ;
        RECT  0 88.176 0.192 88.2 ;
    END
  END di[511]
  PIN di[512]
    DIRECTION INPUT ;
    USE SIGNAL ;
    PORT
      LAYER M4 ;
        RECT  0 88.32 0.192 88.344 ;
    END
  END di[512]
  PIN di[513]
    DIRECTION INPUT ;
    USE SIGNAL ;
    PORT
      LAYER M4 ;
        RECT  0 88.512 0.192 88.536 ;
    END
  END di[513]
  PIN di[51]
    DIRECTION INPUT ;
    USE SIGNAL ;
    PORT
      LAYER M4 ;
        RECT  0 12.768 0.192 12.792 ;
    END
  END di[51]
  PIN di[52]
    DIRECTION INPUT ;
    USE SIGNAL ;
    PORT
      LAYER M4 ;
        RECT  0 12.96 0.192 12.984 ;
    END
  END di[52]
  PIN di[53]
    DIRECTION INPUT ;
    USE SIGNAL ;
    PORT
      LAYER M4 ;
        RECT  0 13.104 0.192 13.128 ;
    END
  END di[53]
  PIN di[54]
    DIRECTION INPUT ;
    USE SIGNAL ;
    PORT
      LAYER M4 ;
        RECT  0 13.248 0.192 13.272 ;
    END
  END di[54]
  PIN di[55]
    DIRECTION INPUT ;
    USE SIGNAL ;
    PORT
      LAYER M4 ;
        RECT  0 13.44 0.192 13.464 ;
    END
  END di[55]
  PIN di[56]
    DIRECTION INPUT ;
    USE SIGNAL ;
    PORT
      LAYER M4 ;
        RECT  0 13.584 0.192 13.608 ;
    END
  END di[56]
  PIN di[57]
    DIRECTION INPUT ;
    USE SIGNAL ;
    PORT
      LAYER M4 ;
        RECT  0 13.776 0.192 13.8 ;
    END
  END di[57]
  PIN di[58]
    DIRECTION INPUT ;
    USE SIGNAL ;
    PORT
      LAYER M4 ;
        RECT  0 13.92 0.192 13.944 ;
    END
  END di[58]
  PIN di[59]
    DIRECTION INPUT ;
    USE SIGNAL ;
    PORT
      LAYER M4 ;
        RECT  0 14.064 0.192 14.088 ;
    END
  END di[59]
  PIN di[5]
    DIRECTION INPUT ;
    USE SIGNAL ;
    PORT
      LAYER M4 ;
        RECT  0 5.232 0.192 5.256 ;
    END
  END di[5]
  PIN di[60]
    DIRECTION INPUT ;
    USE SIGNAL ;
    PORT
      LAYER M4 ;
        RECT  0 14.256 0.192 14.28 ;
    END
  END di[60]
  PIN di[61]
    DIRECTION INPUT ;
    USE SIGNAL ;
    PORT
      LAYER M4 ;
        RECT  0 14.4 0.192 14.424 ;
    END
  END di[61]
  PIN di[62]
    DIRECTION INPUT ;
    USE SIGNAL ;
    PORT
      LAYER M4 ;
        RECT  0 14.592 0.192 14.616 ;
    END
  END di[62]
  PIN di[63]
    DIRECTION INPUT ;
    USE SIGNAL ;
    PORT
      LAYER M4 ;
        RECT  0 14.736 0.192 14.76 ;
    END
  END di[63]
  PIN di[64]
    DIRECTION INPUT ;
    USE SIGNAL ;
    PORT
      LAYER M4 ;
        RECT  0 14.88 0.192 14.904 ;
    END
  END di[64]
  PIN di[65]
    DIRECTION INPUT ;
    USE SIGNAL ;
    PORT
      LAYER M4 ;
        RECT  0 15.072 0.192 15.096 ;
    END
  END di[65]
  PIN di[66]
    DIRECTION INPUT ;
    USE SIGNAL ;
    PORT
      LAYER M4 ;
        RECT  0 15.216 0.192 15.24 ;
    END
  END di[66]
  PIN di[67]
    DIRECTION INPUT ;
    USE SIGNAL ;
    PORT
      LAYER M4 ;
        RECT  0 15.408 0.192 15.432 ;
    END
  END di[67]
  PIN di[68]
    DIRECTION INPUT ;
    USE SIGNAL ;
    PORT
      LAYER M4 ;
        RECT  0 15.552 0.192 15.576 ;
    END
  END di[68]
  PIN di[69]
    DIRECTION INPUT ;
    USE SIGNAL ;
    PORT
      LAYER M4 ;
        RECT  0 15.744 0.192 15.768 ;
    END
  END di[69]
  PIN di[6]
    DIRECTION INPUT ;
    USE SIGNAL ;
    PORT
      LAYER M4 ;
        RECT  0 5.376 0.192 5.4 ;
    END
  END di[6]
  PIN di[70]
    DIRECTION INPUT ;
    USE SIGNAL ;
    PORT
      LAYER M4 ;
        RECT  0 15.888 0.192 15.912 ;
    END
  END di[70]
  PIN di[71]
    DIRECTION INPUT ;
    USE SIGNAL ;
    PORT
      LAYER M4 ;
        RECT  0 16.032 0.192 16.056 ;
    END
  END di[71]
  PIN di[72]
    DIRECTION INPUT ;
    USE SIGNAL ;
    PORT
      LAYER M4 ;
        RECT  0 16.224 0.192 16.248 ;
    END
  END di[72]
  PIN di[73]
    DIRECTION INPUT ;
    USE SIGNAL ;
    PORT
      LAYER M4 ;
        RECT  0 16.368 0.192 16.392 ;
    END
  END di[73]
  PIN di[74]
    DIRECTION INPUT ;
    USE SIGNAL ;
    PORT
      LAYER M4 ;
        RECT  0 16.56 0.192 16.584 ;
    END
  END di[74]
  PIN di[75]
    DIRECTION INPUT ;
    USE SIGNAL ;
    PORT
      LAYER M4 ;
        RECT  0 16.704 0.192 16.728 ;
    END
  END di[75]
  PIN di[76]
    DIRECTION INPUT ;
    USE SIGNAL ;
    PORT
      LAYER M4 ;
        RECT  0 16.848 0.192 16.872 ;
    END
  END di[76]
  PIN di[77]
    DIRECTION INPUT ;
    USE SIGNAL ;
    PORT
      LAYER M4 ;
        RECT  0 17.04 0.192 17.064 ;
    END
  END di[77]
  PIN di[78]
    DIRECTION INPUT ;
    USE SIGNAL ;
    PORT
      LAYER M4 ;
        RECT  0 17.184 0.192 17.208 ;
    END
  END di[78]
  PIN di[79]
    DIRECTION INPUT ;
    USE SIGNAL ;
    PORT
      LAYER M4 ;
        RECT  0 17.376 0.192 17.4 ;
    END
  END di[79]
  PIN di[7]
    DIRECTION INPUT ;
    USE SIGNAL ;
    PORT
      LAYER M4 ;
        RECT  0 5.568 0.192 5.592 ;
    END
  END di[7]
  PIN di[80]
    DIRECTION INPUT ;
    USE SIGNAL ;
    PORT
      LAYER M4 ;
        RECT  0 17.52 0.192 17.544 ;
    END
  END di[80]
  PIN di[81]
    DIRECTION INPUT ;
    USE SIGNAL ;
    PORT
      LAYER M4 ;
        RECT  0 17.712 0.192 17.736 ;
    END
  END di[81]
  PIN di[82]
    DIRECTION INPUT ;
    USE SIGNAL ;
    PORT
      LAYER M4 ;
        RECT  0 17.856 0.192 17.88 ;
    END
  END di[82]
  PIN di[83]
    DIRECTION INPUT ;
    USE SIGNAL ;
    PORT
      LAYER M4 ;
        RECT  0 18 0.192 18.024 ;
    END
  END di[83]
  PIN di[84]
    DIRECTION INPUT ;
    USE SIGNAL ;
    PORT
      LAYER M4 ;
        RECT  0 18.192 0.192 18.216 ;
    END
  END di[84]
  PIN di[85]
    DIRECTION INPUT ;
    USE SIGNAL ;
    PORT
      LAYER M4 ;
        RECT  0 18.336 0.192 18.36 ;
    END
  END di[85]
  PIN di[86]
    DIRECTION INPUT ;
    USE SIGNAL ;
    PORT
      LAYER M4 ;
        RECT  0 18.528 0.192 18.552 ;
    END
  END di[86]
  PIN di[87]
    DIRECTION INPUT ;
    USE SIGNAL ;
    PORT
      LAYER M4 ;
        RECT  0 18.672 0.192 18.696 ;
    END
  END di[87]
  PIN di[88]
    DIRECTION INPUT ;
    USE SIGNAL ;
    PORT
      LAYER M4 ;
        RECT  0 18.816 0.192 18.84 ;
    END
  END di[88]
  PIN di[89]
    DIRECTION INPUT ;
    USE SIGNAL ;
    PORT
      LAYER M4 ;
        RECT  0 19.008 0.192 19.032 ;
    END
  END di[89]
  PIN di[8]
    DIRECTION INPUT ;
    USE SIGNAL ;
    PORT
      LAYER M4 ;
        RECT  0 5.712 0.192 5.736 ;
    END
  END di[8]
  PIN di[90]
    DIRECTION INPUT ;
    USE SIGNAL ;
    PORT
      LAYER M4 ;
        RECT  0 19.152 0.192 19.176 ;
    END
  END di[90]
  PIN di[91]
    DIRECTION INPUT ;
    USE SIGNAL ;
    PORT
      LAYER M4 ;
        RECT  0 19.344 0.192 19.368 ;
    END
  END di[91]
  PIN di[92]
    DIRECTION INPUT ;
    USE SIGNAL ;
    PORT
      LAYER M4 ;
        RECT  0 19.488 0.192 19.512 ;
    END
  END di[92]
  PIN di[93]
    DIRECTION INPUT ;
    USE SIGNAL ;
    PORT
      LAYER M4 ;
        RECT  0 19.632 0.192 19.656 ;
    END
  END di[93]
  PIN di[94]
    DIRECTION INPUT ;
    USE SIGNAL ;
    PORT
      LAYER M4 ;
        RECT  0 19.824 0.192 19.848 ;
    END
  END di[94]
  PIN di[95]
    DIRECTION INPUT ;
    USE SIGNAL ;
    PORT
      LAYER M4 ;
        RECT  0 19.968 0.192 19.992 ;
    END
  END di[95]
  PIN di[96]
    DIRECTION INPUT ;
    USE SIGNAL ;
    PORT
      LAYER M4 ;
        RECT  0 20.16 0.192 20.184 ;
    END
  END di[96]
  PIN di[97]
    DIRECTION INPUT ;
    USE SIGNAL ;
    PORT
      LAYER M4 ;
        RECT  0 20.304 0.192 20.328 ;
    END
  END di[97]
  PIN di[98]
    DIRECTION INPUT ;
    USE SIGNAL ;
    PORT
      LAYER M4 ;
        RECT  0 20.496 0.192 20.52 ;
    END
  END di[98]
  PIN di[99]
    DIRECTION INPUT ;
    USE SIGNAL ;
    PORT
      LAYER M4 ;
        RECT  0 20.64 0.192 20.664 ;
    END
  END di[99]
  PIN di[9]
    DIRECTION INPUT ;
    USE SIGNAL ;
    PORT
      LAYER M4 ;
        RECT  0 5.904 0.192 5.928 ;
    END
  END di[9]
  PIN dq[0]
    DIRECTION OUTPUT ;
    USE SIGNAL ;
    PORT
      LAYER M4 ;
        RECT  36.528 4.416 36.72 4.44 ;
    END
  END dq[0]
  PIN dq[100]
    DIRECTION OUTPUT ;
    USE SIGNAL ;
    PORT
      LAYER M4 ;
        RECT  36.528 20.784 36.72 20.808 ;
    END
  END dq[100]
  PIN dq[101]
    DIRECTION OUTPUT ;
    USE SIGNAL ;
    PORT
      LAYER M4 ;
        RECT  36.528 20.976 36.72 21 ;
    END
  END dq[101]
  PIN dq[102]
    DIRECTION OUTPUT ;
    USE SIGNAL ;
    PORT
      LAYER M4 ;
        RECT  36.528 21.12 36.72 21.144 ;
    END
  END dq[102]
  PIN dq[103]
    DIRECTION OUTPUT ;
    USE SIGNAL ;
    PORT
      LAYER M4 ;
        RECT  36.528 21.312 36.72 21.336 ;
    END
  END dq[103]
  PIN dq[104]
    DIRECTION OUTPUT ;
    USE SIGNAL ;
    PORT
      LAYER M4 ;
        RECT  36.528 21.456 36.72 21.48 ;
    END
  END dq[104]
  PIN dq[105]
    DIRECTION OUTPUT ;
    USE SIGNAL ;
    PORT
      LAYER M4 ;
        RECT  36.528 21.6 36.72 21.624 ;
    END
  END dq[105]
  PIN dq[106]
    DIRECTION OUTPUT ;
    USE SIGNAL ;
    PORT
      LAYER M4 ;
        RECT  36.528 21.792 36.72 21.816 ;
    END
  END dq[106]
  PIN dq[107]
    DIRECTION OUTPUT ;
    USE SIGNAL ;
    PORT
      LAYER M4 ;
        RECT  36.528 21.936 36.72 21.96 ;
    END
  END dq[107]
  PIN dq[108]
    DIRECTION OUTPUT ;
    USE SIGNAL ;
    PORT
      LAYER M4 ;
        RECT  36.528 22.128 36.72 22.152 ;
    END
  END dq[108]
  PIN dq[109]
    DIRECTION OUTPUT ;
    USE SIGNAL ;
    PORT
      LAYER M4 ;
        RECT  36.528 22.272 36.72 22.296 ;
    END
  END dq[109]
  PIN dq[10]
    DIRECTION OUTPUT ;
    USE SIGNAL ;
    PORT
      LAYER M4 ;
        RECT  36.528 6.048 36.72 6.072 ;
    END
  END dq[10]
  PIN dq[110]
    DIRECTION OUTPUT ;
    USE SIGNAL ;
    PORT
      LAYER M4 ;
        RECT  36.528 22.464 36.72 22.488 ;
    END
  END dq[110]
  PIN dq[111]
    DIRECTION OUTPUT ;
    USE SIGNAL ;
    PORT
      LAYER M4 ;
        RECT  36.528 22.608 36.72 22.632 ;
    END
  END dq[111]
  PIN dq[112]
    DIRECTION OUTPUT ;
    USE SIGNAL ;
    PORT
      LAYER M4 ;
        RECT  36.528 22.752 36.72 22.776 ;
    END
  END dq[112]
  PIN dq[113]
    DIRECTION OUTPUT ;
    USE SIGNAL ;
    PORT
      LAYER M4 ;
        RECT  36.528 22.944 36.72 22.968 ;
    END
  END dq[113]
  PIN dq[114]
    DIRECTION OUTPUT ;
    USE SIGNAL ;
    PORT
      LAYER M4 ;
        RECT  36.528 23.088 36.72 23.112 ;
    END
  END dq[114]
  PIN dq[115]
    DIRECTION OUTPUT ;
    USE SIGNAL ;
    PORT
      LAYER M4 ;
        RECT  36.528 23.28 36.72 23.304 ;
    END
  END dq[115]
  PIN dq[116]
    DIRECTION OUTPUT ;
    USE SIGNAL ;
    PORT
      LAYER M4 ;
        RECT  36.528 23.424 36.72 23.448 ;
    END
  END dq[116]
  PIN dq[117]
    DIRECTION OUTPUT ;
    USE SIGNAL ;
    PORT
      LAYER M4 ;
        RECT  36.528 23.568 36.72 23.592 ;
    END
  END dq[117]
  PIN dq[118]
    DIRECTION OUTPUT ;
    USE SIGNAL ;
    PORT
      LAYER M4 ;
        RECT  36.528 23.76 36.72 23.784 ;
    END
  END dq[118]
  PIN dq[119]
    DIRECTION OUTPUT ;
    USE SIGNAL ;
    PORT
      LAYER M4 ;
        RECT  36.528 23.904 36.72 23.928 ;
    END
  END dq[119]
  PIN dq[11]
    DIRECTION OUTPUT ;
    USE SIGNAL ;
    PORT
      LAYER M4 ;
        RECT  36.528 6.24 36.72 6.264 ;
    END
  END dq[11]
  PIN dq[120]
    DIRECTION OUTPUT ;
    USE SIGNAL ;
    PORT
      LAYER M4 ;
        RECT  36.528 24.096 36.72 24.12 ;
    END
  END dq[120]
  PIN dq[121]
    DIRECTION OUTPUT ;
    USE SIGNAL ;
    PORT
      LAYER M4 ;
        RECT  36.528 24.24 36.72 24.264 ;
    END
  END dq[121]
  PIN dq[122]
    DIRECTION OUTPUT ;
    USE SIGNAL ;
    PORT
      LAYER M4 ;
        RECT  36.528 24.432 36.72 24.456 ;
    END
  END dq[122]
  PIN dq[123]
    DIRECTION OUTPUT ;
    USE SIGNAL ;
    PORT
      LAYER M4 ;
        RECT  36.528 24.576 36.72 24.6 ;
    END
  END dq[123]
  PIN dq[124]
    DIRECTION OUTPUT ;
    USE SIGNAL ;
    PORT
      LAYER M4 ;
        RECT  36.528 24.72 36.72 24.744 ;
    END
  END dq[124]
  PIN dq[125]
    DIRECTION OUTPUT ;
    USE SIGNAL ;
    PORT
      LAYER M4 ;
        RECT  36.528 24.912 36.72 24.936 ;
    END
  END dq[125]
  PIN dq[126]
    DIRECTION OUTPUT ;
    USE SIGNAL ;
    PORT
      LAYER M4 ;
        RECT  36.528 25.056 36.72 25.08 ;
    END
  END dq[126]
  PIN dq[127]
    DIRECTION OUTPUT ;
    USE SIGNAL ;
    PORT
      LAYER M4 ;
        RECT  36.528 25.248 36.72 25.272 ;
    END
  END dq[127]
  PIN dq[128]
    DIRECTION OUTPUT ;
    USE SIGNAL ;
    PORT
      LAYER M4 ;
        RECT  36.528 25.392 36.72 25.416 ;
    END
  END dq[128]
  PIN dq[129]
    DIRECTION OUTPUT ;
    USE SIGNAL ;
    PORT
      LAYER M4 ;
        RECT  36.528 25.536 36.72 25.56 ;
    END
  END dq[129]
  PIN dq[12]
    DIRECTION OUTPUT ;
    USE SIGNAL ;
    PORT
      LAYER M4 ;
        RECT  36.528 6.384 36.72 6.408 ;
    END
  END dq[12]
  PIN dq[130]
    DIRECTION OUTPUT ;
    USE SIGNAL ;
    PORT
      LAYER M4 ;
        RECT  36.528 25.728 36.72 25.752 ;
    END
  END dq[130]
  PIN dq[131]
    DIRECTION OUTPUT ;
    USE SIGNAL ;
    PORT
      LAYER M4 ;
        RECT  36.528 25.872 36.72 25.896 ;
    END
  END dq[131]
  PIN dq[132]
    DIRECTION OUTPUT ;
    USE SIGNAL ;
    PORT
      LAYER M4 ;
        RECT  36.528 26.064 36.72 26.088 ;
    END
  END dq[132]
  PIN dq[133]
    DIRECTION OUTPUT ;
    USE SIGNAL ;
    PORT
      LAYER M4 ;
        RECT  36.528 26.208 36.72 26.232 ;
    END
  END dq[133]
  PIN dq[134]
    DIRECTION OUTPUT ;
    USE SIGNAL ;
    PORT
      LAYER M4 ;
        RECT  36.528 26.352 36.72 26.376 ;
    END
  END dq[134]
  PIN dq[135]
    DIRECTION OUTPUT ;
    USE SIGNAL ;
    PORT
      LAYER M4 ;
        RECT  36.528 26.544 36.72 26.568 ;
    END
  END dq[135]
  PIN dq[136]
    DIRECTION OUTPUT ;
    USE SIGNAL ;
    PORT
      LAYER M4 ;
        RECT  36.528 26.688 36.72 26.712 ;
    END
  END dq[136]
  PIN dq[137]
    DIRECTION OUTPUT ;
    USE SIGNAL ;
    PORT
      LAYER M4 ;
        RECT  36.528 26.88 36.72 26.904 ;
    END
  END dq[137]
  PIN dq[138]
    DIRECTION OUTPUT ;
    USE SIGNAL ;
    PORT
      LAYER M4 ;
        RECT  36.528 27.024 36.72 27.048 ;
    END
  END dq[138]
  PIN dq[139]
    DIRECTION OUTPUT ;
    USE SIGNAL ;
    PORT
      LAYER M4 ;
        RECT  36.528 27.216 36.72 27.24 ;
    END
  END dq[139]
  PIN dq[13]
    DIRECTION OUTPUT ;
    USE SIGNAL ;
    PORT
      LAYER M4 ;
        RECT  36.528 6.528 36.72 6.552 ;
    END
  END dq[13]
  PIN dq[140]
    DIRECTION OUTPUT ;
    USE SIGNAL ;
    PORT
      LAYER M4 ;
        RECT  36.528 27.36 36.72 27.384 ;
    END
  END dq[140]
  PIN dq[141]
    DIRECTION OUTPUT ;
    USE SIGNAL ;
    PORT
      LAYER M4 ;
        RECT  36.528 27.504 36.72 27.528 ;
    END
  END dq[141]
  PIN dq[142]
    DIRECTION OUTPUT ;
    USE SIGNAL ;
    PORT
      LAYER M4 ;
        RECT  36.528 27.696 36.72 27.72 ;
    END
  END dq[142]
  PIN dq[143]
    DIRECTION OUTPUT ;
    USE SIGNAL ;
    PORT
      LAYER M4 ;
        RECT  36.528 27.84 36.72 27.864 ;
    END
  END dq[143]
  PIN dq[144]
    DIRECTION OUTPUT ;
    USE SIGNAL ;
    PORT
      LAYER M4 ;
        RECT  36.528 28.032 36.72 28.056 ;
    END
  END dq[144]
  PIN dq[145]
    DIRECTION OUTPUT ;
    USE SIGNAL ;
    PORT
      LAYER M4 ;
        RECT  36.528 28.176 36.72 28.2 ;
    END
  END dq[145]
  PIN dq[146]
    DIRECTION OUTPUT ;
    USE SIGNAL ;
    PORT
      LAYER M4 ;
        RECT  36.528 28.32 36.72 28.344 ;
    END
  END dq[146]
  PIN dq[147]
    DIRECTION OUTPUT ;
    USE SIGNAL ;
    PORT
      LAYER M4 ;
        RECT  36.528 28.512 36.72 28.536 ;
    END
  END dq[147]
  PIN dq[148]
    DIRECTION OUTPUT ;
    USE SIGNAL ;
    PORT
      LAYER M4 ;
        RECT  36.528 28.656 36.72 28.68 ;
    END
  END dq[148]
  PIN dq[149]
    DIRECTION OUTPUT ;
    USE SIGNAL ;
    PORT
      LAYER M4 ;
        RECT  36.528 28.848 36.72 28.872 ;
    END
  END dq[149]
  PIN dq[14]
    DIRECTION OUTPUT ;
    USE SIGNAL ;
    PORT
      LAYER M4 ;
        RECT  36.528 6.72 36.72 6.744 ;
    END
  END dq[14]
  PIN dq[150]
    DIRECTION OUTPUT ;
    USE SIGNAL ;
    PORT
      LAYER M4 ;
        RECT  36.528 28.992 36.72 29.016 ;
    END
  END dq[150]
  PIN dq[151]
    DIRECTION OUTPUT ;
    USE SIGNAL ;
    PORT
      LAYER M4 ;
        RECT  36.528 29.184 36.72 29.208 ;
    END
  END dq[151]
  PIN dq[152]
    DIRECTION OUTPUT ;
    USE SIGNAL ;
    PORT
      LAYER M4 ;
        RECT  36.528 29.328 36.72 29.352 ;
    END
  END dq[152]
  PIN dq[153]
    DIRECTION OUTPUT ;
    USE SIGNAL ;
    PORT
      LAYER M4 ;
        RECT  36.528 29.472 36.72 29.496 ;
    END
  END dq[153]
  PIN dq[154]
    DIRECTION OUTPUT ;
    USE SIGNAL ;
    PORT
      LAYER M4 ;
        RECT  36.528 29.664 36.72 29.688 ;
    END
  END dq[154]
  PIN dq[155]
    DIRECTION OUTPUT ;
    USE SIGNAL ;
    PORT
      LAYER M4 ;
        RECT  36.528 29.808 36.72 29.832 ;
    END
  END dq[155]
  PIN dq[156]
    DIRECTION OUTPUT ;
    USE SIGNAL ;
    PORT
      LAYER M4 ;
        RECT  36.528 30 36.72 30.024 ;
    END
  END dq[156]
  PIN dq[157]
    DIRECTION OUTPUT ;
    USE SIGNAL ;
    PORT
      LAYER M4 ;
        RECT  36.528 30.144 36.72 30.168 ;
    END
  END dq[157]
  PIN dq[158]
    DIRECTION OUTPUT ;
    USE SIGNAL ;
    PORT
      LAYER M4 ;
        RECT  36.528 30.288 36.72 30.312 ;
    END
  END dq[158]
  PIN dq[159]
    DIRECTION OUTPUT ;
    USE SIGNAL ;
    PORT
      LAYER M4 ;
        RECT  36.528 30.48 36.72 30.504 ;
    END
  END dq[159]
  PIN dq[15]
    DIRECTION OUTPUT ;
    USE SIGNAL ;
    PORT
      LAYER M4 ;
        RECT  36.528 6.864 36.72 6.888 ;
    END
  END dq[15]
  PIN dq[160]
    DIRECTION OUTPUT ;
    USE SIGNAL ;
    PORT
      LAYER M4 ;
        RECT  36.528 30.624 36.72 30.648 ;
    END
  END dq[160]
  PIN dq[161]
    DIRECTION OUTPUT ;
    USE SIGNAL ;
    PORT
      LAYER M4 ;
        RECT  36.528 30.816 36.72 30.84 ;
    END
  END dq[161]
  PIN dq[162]
    DIRECTION OUTPUT ;
    USE SIGNAL ;
    PORT
      LAYER M4 ;
        RECT  36.528 30.96 36.72 30.984 ;
    END
  END dq[162]
  PIN dq[163]
    DIRECTION OUTPUT ;
    USE SIGNAL ;
    PORT
      LAYER M4 ;
        RECT  36.528 31.152 36.72 31.176 ;
    END
  END dq[163]
  PIN dq[164]
    DIRECTION OUTPUT ;
    USE SIGNAL ;
    PORT
      LAYER M4 ;
        RECT  36.528 31.296 36.72 31.32 ;
    END
  END dq[164]
  PIN dq[165]
    DIRECTION OUTPUT ;
    USE SIGNAL ;
    PORT
      LAYER M4 ;
        RECT  36.528 31.44 36.72 31.464 ;
    END
  END dq[165]
  PIN dq[166]
    DIRECTION OUTPUT ;
    USE SIGNAL ;
    PORT
      LAYER M4 ;
        RECT  36.528 31.632 36.72 31.656 ;
    END
  END dq[166]
  PIN dq[167]
    DIRECTION OUTPUT ;
    USE SIGNAL ;
    PORT
      LAYER M4 ;
        RECT  36.528 31.776 36.72 31.8 ;
    END
  END dq[167]
  PIN dq[168]
    DIRECTION OUTPUT ;
    USE SIGNAL ;
    PORT
      LAYER M4 ;
        RECT  36.528 31.968 36.72 31.992 ;
    END
  END dq[168]
  PIN dq[169]
    DIRECTION OUTPUT ;
    USE SIGNAL ;
    PORT
      LAYER M4 ;
        RECT  36.528 32.112 36.72 32.136 ;
    END
  END dq[169]
  PIN dq[16]
    DIRECTION OUTPUT ;
    USE SIGNAL ;
    PORT
      LAYER M4 ;
        RECT  36.528 7.056 36.72 7.08 ;
    END
  END dq[16]
  PIN dq[170]
    DIRECTION OUTPUT ;
    USE SIGNAL ;
    PORT
      LAYER M4 ;
        RECT  36.528 32.256 36.72 32.28 ;
    END
  END dq[170]
  PIN dq[171]
    DIRECTION OUTPUT ;
    USE SIGNAL ;
    PORT
      LAYER M4 ;
        RECT  36.528 32.448 36.72 32.472 ;
    END
  END dq[171]
  PIN dq[172]
    DIRECTION OUTPUT ;
    USE SIGNAL ;
    PORT
      LAYER M4 ;
        RECT  36.528 32.592 36.72 32.616 ;
    END
  END dq[172]
  PIN dq[173]
    DIRECTION OUTPUT ;
    USE SIGNAL ;
    PORT
      LAYER M4 ;
        RECT  36.528 32.784 36.72 32.808 ;
    END
  END dq[173]
  PIN dq[174]
    DIRECTION OUTPUT ;
    USE SIGNAL ;
    PORT
      LAYER M4 ;
        RECT  36.528 32.928 36.72 32.952 ;
    END
  END dq[174]
  PIN dq[175]
    DIRECTION OUTPUT ;
    USE SIGNAL ;
    PORT
      LAYER M4 ;
        RECT  36.528 33.072 36.72 33.096 ;
    END
  END dq[175]
  PIN dq[176]
    DIRECTION OUTPUT ;
    USE SIGNAL ;
    PORT
      LAYER M4 ;
        RECT  36.528 33.264 36.72 33.288 ;
    END
  END dq[176]
  PIN dq[177]
    DIRECTION OUTPUT ;
    USE SIGNAL ;
    PORT
      LAYER M4 ;
        RECT  36.528 33.408 36.72 33.432 ;
    END
  END dq[177]
  PIN dq[178]
    DIRECTION OUTPUT ;
    USE SIGNAL ;
    PORT
      LAYER M4 ;
        RECT  36.528 33.6 36.72 33.624 ;
    END
  END dq[178]
  PIN dq[179]
    DIRECTION OUTPUT ;
    USE SIGNAL ;
    PORT
      LAYER M4 ;
        RECT  36.528 33.744 36.72 33.768 ;
    END
  END dq[179]
  PIN dq[17]
    DIRECTION OUTPUT ;
    USE SIGNAL ;
    PORT
      LAYER M4 ;
        RECT  36.528 7.2 36.72 7.224 ;
    END
  END dq[17]
  PIN dq[180]
    DIRECTION OUTPUT ;
    USE SIGNAL ;
    PORT
      LAYER M4 ;
        RECT  36.528 33.936 36.72 33.96 ;
    END
  END dq[180]
  PIN dq[181]
    DIRECTION OUTPUT ;
    USE SIGNAL ;
    PORT
      LAYER M4 ;
        RECT  36.528 34.08 36.72 34.104 ;
    END
  END dq[181]
  PIN dq[182]
    DIRECTION OUTPUT ;
    USE SIGNAL ;
    PORT
      LAYER M4 ;
        RECT  36.528 34.224 36.72 34.248 ;
    END
  END dq[182]
  PIN dq[183]
    DIRECTION OUTPUT ;
    USE SIGNAL ;
    PORT
      LAYER M4 ;
        RECT  36.528 34.416 36.72 34.44 ;
    END
  END dq[183]
  PIN dq[184]
    DIRECTION OUTPUT ;
    USE SIGNAL ;
    PORT
      LAYER M4 ;
        RECT  36.528 34.56 36.72 34.584 ;
    END
  END dq[184]
  PIN dq[185]
    DIRECTION OUTPUT ;
    USE SIGNAL ;
    PORT
      LAYER M4 ;
        RECT  36.528 34.752 36.72 34.776 ;
    END
  END dq[185]
  PIN dq[186]
    DIRECTION OUTPUT ;
    USE SIGNAL ;
    PORT
      LAYER M4 ;
        RECT  36.528 34.896 36.72 34.92 ;
    END
  END dq[186]
  PIN dq[187]
    DIRECTION OUTPUT ;
    USE SIGNAL ;
    PORT
      LAYER M4 ;
        RECT  36.528 35.04 36.72 35.064 ;
    END
  END dq[187]
  PIN dq[188]
    DIRECTION OUTPUT ;
    USE SIGNAL ;
    PORT
      LAYER M4 ;
        RECT  36.528 35.232 36.72 35.256 ;
    END
  END dq[188]
  PIN dq[189]
    DIRECTION OUTPUT ;
    USE SIGNAL ;
    PORT
      LAYER M4 ;
        RECT  36.528 35.376 36.72 35.4 ;
    END
  END dq[189]
  PIN dq[18]
    DIRECTION OUTPUT ;
    USE SIGNAL ;
    PORT
      LAYER M4 ;
        RECT  36.528 7.344 36.72 7.368 ;
    END
  END dq[18]
  PIN dq[190]
    DIRECTION OUTPUT ;
    USE SIGNAL ;
    PORT
      LAYER M4 ;
        RECT  36.528 35.568 36.72 35.592 ;
    END
  END dq[190]
  PIN dq[191]
    DIRECTION OUTPUT ;
    USE SIGNAL ;
    PORT
      LAYER M4 ;
        RECT  36.528 35.712 36.72 35.736 ;
    END
  END dq[191]
  PIN dq[192]
    DIRECTION OUTPUT ;
    USE SIGNAL ;
    PORT
      LAYER M4 ;
        RECT  36.528 35.904 36.72 35.928 ;
    END
  END dq[192]
  PIN dq[193]
    DIRECTION OUTPUT ;
    USE SIGNAL ;
    PORT
      LAYER M4 ;
        RECT  36.528 36.048 36.72 36.072 ;
    END
  END dq[193]
  PIN dq[194]
    DIRECTION OUTPUT ;
    USE SIGNAL ;
    PORT
      LAYER M4 ;
        RECT  36.528 36.192 36.72 36.216 ;
    END
  END dq[194]
  PIN dq[195]
    DIRECTION OUTPUT ;
    USE SIGNAL ;
    PORT
      LAYER M4 ;
        RECT  36.528 36.384 36.72 36.408 ;
    END
  END dq[195]
  PIN dq[196]
    DIRECTION OUTPUT ;
    USE SIGNAL ;
    PORT
      LAYER M4 ;
        RECT  36.528 36.528 36.72 36.552 ;
    END
  END dq[196]
  PIN dq[197]
    DIRECTION OUTPUT ;
    USE SIGNAL ;
    PORT
      LAYER M4 ;
        RECT  36.528 36.72 36.72 36.744 ;
    END
  END dq[197]
  PIN dq[198]
    DIRECTION OUTPUT ;
    USE SIGNAL ;
    PORT
      LAYER M4 ;
        RECT  36.528 36.864 36.72 36.888 ;
    END
  END dq[198]
  PIN dq[199]
    DIRECTION OUTPUT ;
    USE SIGNAL ;
    PORT
      LAYER M4 ;
        RECT  36.528 37.008 36.72 37.032 ;
    END
  END dq[199]
  PIN dq[19]
    DIRECTION OUTPUT ;
    USE SIGNAL ;
    PORT
      LAYER M4 ;
        RECT  36.528 7.536 36.72 7.56 ;
    END
  END dq[19]
  PIN dq[1]
    DIRECTION OUTPUT ;
    USE SIGNAL ;
    PORT
      LAYER M4 ;
        RECT  36.528 4.56 36.72 4.584 ;
    END
  END dq[1]
  PIN dq[200]
    DIRECTION OUTPUT ;
    USE SIGNAL ;
    PORT
      LAYER M4 ;
        RECT  36.528 37.2 36.72 37.224 ;
    END
  END dq[200]
  PIN dq[201]
    DIRECTION OUTPUT ;
    USE SIGNAL ;
    PORT
      LAYER M4 ;
        RECT  36.528 37.344 36.72 37.368 ;
    END
  END dq[201]
  PIN dq[202]
    DIRECTION OUTPUT ;
    USE SIGNAL ;
    PORT
      LAYER M4 ;
        RECT  36.528 37.536 36.72 37.56 ;
    END
  END dq[202]
  PIN dq[203]
    DIRECTION OUTPUT ;
    USE SIGNAL ;
    PORT
      LAYER M4 ;
        RECT  36.528 37.68 36.72 37.704 ;
    END
  END dq[203]
  PIN dq[204]
    DIRECTION OUTPUT ;
    USE SIGNAL ;
    PORT
      LAYER M4 ;
        RECT  36.528 37.824 36.72 37.848 ;
    END
  END dq[204]
  PIN dq[205]
    DIRECTION OUTPUT ;
    USE SIGNAL ;
    PORT
      LAYER M4 ;
        RECT  36.528 38.016 36.72 38.04 ;
    END
  END dq[205]
  PIN dq[206]
    DIRECTION OUTPUT ;
    USE SIGNAL ;
    PORT
      LAYER M4 ;
        RECT  36.528 38.16 36.72 38.184 ;
    END
  END dq[206]
  PIN dq[207]
    DIRECTION OUTPUT ;
    USE SIGNAL ;
    PORT
      LAYER M4 ;
        RECT  36.528 38.352 36.72 38.376 ;
    END
  END dq[207]
  PIN dq[208]
    DIRECTION OUTPUT ;
    USE SIGNAL ;
    PORT
      LAYER M4 ;
        RECT  36.528 38.496 36.72 38.52 ;
    END
  END dq[208]
  PIN dq[209]
    DIRECTION OUTPUT ;
    USE SIGNAL ;
    PORT
      LAYER M4 ;
        RECT  36.528 38.688 36.72 38.712 ;
    END
  END dq[209]
  PIN dq[20]
    DIRECTION OUTPUT ;
    USE SIGNAL ;
    PORT
      LAYER M4 ;
        RECT  36.528 7.68 36.72 7.704 ;
    END
  END dq[20]
  PIN dq[210]
    DIRECTION OUTPUT ;
    USE SIGNAL ;
    PORT
      LAYER M4 ;
        RECT  36.528 38.832 36.72 38.856 ;
    END
  END dq[210]
  PIN dq[211]
    DIRECTION OUTPUT ;
    USE SIGNAL ;
    PORT
      LAYER M4 ;
        RECT  36.528 38.976 36.72 39 ;
    END
  END dq[211]
  PIN dq[212]
    DIRECTION OUTPUT ;
    USE SIGNAL ;
    PORT
      LAYER M4 ;
        RECT  36.528 39.168 36.72 39.192 ;
    END
  END dq[212]
  PIN dq[213]
    DIRECTION OUTPUT ;
    USE SIGNAL ;
    PORT
      LAYER M4 ;
        RECT  36.528 39.312 36.72 39.336 ;
    END
  END dq[213]
  PIN dq[214]
    DIRECTION OUTPUT ;
    USE SIGNAL ;
    PORT
      LAYER M4 ;
        RECT  36.528 39.504 36.72 39.528 ;
    END
  END dq[214]
  PIN dq[215]
    DIRECTION OUTPUT ;
    USE SIGNAL ;
    PORT
      LAYER M4 ;
        RECT  36.528 39.648 36.72 39.672 ;
    END
  END dq[215]
  PIN dq[216]
    DIRECTION OUTPUT ;
    USE SIGNAL ;
    PORT
      LAYER M4 ;
        RECT  36.528 39.792 36.72 39.816 ;
    END
  END dq[216]
  PIN dq[217]
    DIRECTION OUTPUT ;
    USE SIGNAL ;
    PORT
      LAYER M4 ;
        RECT  36.528 39.984 36.72 40.008 ;
    END
  END dq[217]
  PIN dq[218]
    DIRECTION OUTPUT ;
    USE SIGNAL ;
    PORT
      LAYER M4 ;
        RECT  36.528 40.128 36.72 40.152 ;
    END
  END dq[218]
  PIN dq[219]
    DIRECTION OUTPUT ;
    USE SIGNAL ;
    PORT
      LAYER M4 ;
        RECT  36.528 40.32 36.72 40.344 ;
    END
  END dq[219]
  PIN dq[21]
    DIRECTION OUTPUT ;
    USE SIGNAL ;
    PORT
      LAYER M4 ;
        RECT  36.528 7.872 36.72 7.896 ;
    END
  END dq[21]
  PIN dq[220]
    DIRECTION OUTPUT ;
    USE SIGNAL ;
    PORT
      LAYER M4 ;
        RECT  36.528 40.464 36.72 40.488 ;
    END
  END dq[220]
  PIN dq[221]
    DIRECTION OUTPUT ;
    USE SIGNAL ;
    PORT
      LAYER M4 ;
        RECT  36.528 40.656 36.72 40.68 ;
    END
  END dq[221]
  PIN dq[222]
    DIRECTION OUTPUT ;
    USE SIGNAL ;
    PORT
      LAYER M4 ;
        RECT  36.528 40.8 36.72 40.824 ;
    END
  END dq[222]
  PIN dq[223]
    DIRECTION OUTPUT ;
    USE SIGNAL ;
    PORT
      LAYER M4 ;
        RECT  36.528 40.944 36.72 40.968 ;
    END
  END dq[223]
  PIN dq[224]
    DIRECTION OUTPUT ;
    USE SIGNAL ;
    PORT
      LAYER M4 ;
        RECT  36.528 41.136 36.72 41.16 ;
    END
  END dq[224]
  PIN dq[225]
    DIRECTION OUTPUT ;
    USE SIGNAL ;
    PORT
      LAYER M4 ;
        RECT  36.528 41.28 36.72 41.304 ;
    END
  END dq[225]
  PIN dq[226]
    DIRECTION OUTPUT ;
    USE SIGNAL ;
    PORT
      LAYER M4 ;
        RECT  36.528 41.472 36.72 41.496 ;
    END
  END dq[226]
  PIN dq[227]
    DIRECTION OUTPUT ;
    USE SIGNAL ;
    PORT
      LAYER M4 ;
        RECT  36.528 41.616 36.72 41.64 ;
    END
  END dq[227]
  PIN dq[228]
    DIRECTION OUTPUT ;
    USE SIGNAL ;
    PORT
      LAYER M4 ;
        RECT  36.528 41.76 36.72 41.784 ;
    END
  END dq[228]
  PIN dq[229]
    DIRECTION OUTPUT ;
    USE SIGNAL ;
    PORT
      LAYER M4 ;
        RECT  36.528 41.952 36.72 41.976 ;
    END
  END dq[229]
  PIN dq[22]
    DIRECTION OUTPUT ;
    USE SIGNAL ;
    PORT
      LAYER M4 ;
        RECT  36.528 8.016 36.72 8.04 ;
    END
  END dq[22]
  PIN dq[230]
    DIRECTION OUTPUT ;
    USE SIGNAL ;
    PORT
      LAYER M4 ;
        RECT  36.528 42.096 36.72 42.12 ;
    END
  END dq[230]
  PIN dq[231]
    DIRECTION OUTPUT ;
    USE SIGNAL ;
    PORT
      LAYER M4 ;
        RECT  36.528 42.288 36.72 42.312 ;
    END
  END dq[231]
  PIN dq[232]
    DIRECTION OUTPUT ;
    USE SIGNAL ;
    PORT
      LAYER M4 ;
        RECT  36.528 42.432 36.72 42.456 ;
    END
  END dq[232]
  PIN dq[233]
    DIRECTION OUTPUT ;
    USE SIGNAL ;
    PORT
      LAYER M4 ;
        RECT  36.528 42.624 36.72 42.648 ;
    END
  END dq[233]
  PIN dq[234]
    DIRECTION OUTPUT ;
    USE SIGNAL ;
    PORT
      LAYER M4 ;
        RECT  36.528 42.768 36.72 42.792 ;
    END
  END dq[234]
  PIN dq[235]
    DIRECTION OUTPUT ;
    USE SIGNAL ;
    PORT
      LAYER M4 ;
        RECT  36.528 42.912 36.72 42.936 ;
    END
  END dq[235]
  PIN dq[236]
    DIRECTION OUTPUT ;
    USE SIGNAL ;
    PORT
      LAYER M4 ;
        RECT  36.528 43.104 36.72 43.128 ;
    END
  END dq[236]
  PIN dq[237]
    DIRECTION OUTPUT ;
    USE SIGNAL ;
    PORT
      LAYER M4 ;
        RECT  36.528 43.248 36.72 43.272 ;
    END
  END dq[237]
  PIN dq[238]
    DIRECTION OUTPUT ;
    USE SIGNAL ;
    PORT
      LAYER M4 ;
        RECT  36.528 43.44 36.72 43.464 ;
    END
  END dq[238]
  PIN dq[239]
    DIRECTION OUTPUT ;
    USE SIGNAL ;
    PORT
      LAYER M4 ;
        RECT  36.528 43.584 36.72 43.608 ;
    END
  END dq[239]
  PIN dq[23]
    DIRECTION OUTPUT ;
    USE SIGNAL ;
    PORT
      LAYER M4 ;
        RECT  36.528 8.16 36.72 8.184 ;
    END
  END dq[23]
  PIN dq[240]
    DIRECTION OUTPUT ;
    USE SIGNAL ;
    PORT
      LAYER M4 ;
        RECT  36.528 43.728 36.72 43.752 ;
    END
  END dq[240]
  PIN dq[241]
    DIRECTION OUTPUT ;
    USE SIGNAL ;
    PORT
      LAYER M4 ;
        RECT  36.528 43.92 36.72 43.944 ;
    END
  END dq[241]
  PIN dq[242]
    DIRECTION OUTPUT ;
    USE SIGNAL ;
    PORT
      LAYER M4 ;
        RECT  36.528 44.064 36.72 44.088 ;
    END
  END dq[242]
  PIN dq[243]
    DIRECTION OUTPUT ;
    USE SIGNAL ;
    PORT
      LAYER M4 ;
        RECT  36.528 44.256 36.72 44.28 ;
    END
  END dq[243]
  PIN dq[244]
    DIRECTION OUTPUT ;
    USE SIGNAL ;
    PORT
      LAYER M4 ;
        RECT  36.528 44.4 36.72 44.424 ;
    END
  END dq[244]
  PIN dq[245]
    DIRECTION OUTPUT ;
    USE SIGNAL ;
    PORT
      LAYER M4 ;
        RECT  36.528 44.544 36.72 44.568 ;
    END
  END dq[245]
  PIN dq[246]
    DIRECTION OUTPUT ;
    USE SIGNAL ;
    PORT
      LAYER M4 ;
        RECT  36.528 44.736 36.72 44.76 ;
    END
  END dq[246]
  PIN dq[247]
    DIRECTION OUTPUT ;
    USE SIGNAL ;
    PORT
      LAYER M4 ;
        RECT  36.528 44.88 36.72 44.904 ;
    END
  END dq[247]
  PIN dq[248]
    DIRECTION OUTPUT ;
    USE SIGNAL ;
    PORT
      LAYER M4 ;
        RECT  36.528 45.072 36.72 45.096 ;
    END
  END dq[248]
  PIN dq[249]
    DIRECTION OUTPUT ;
    USE SIGNAL ;
    PORT
      LAYER M4 ;
        RECT  36.528 45.216 36.72 45.24 ;
    END
  END dq[249]
  PIN dq[24]
    DIRECTION OUTPUT ;
    USE SIGNAL ;
    PORT
      LAYER M4 ;
        RECT  36.528 8.352 36.72 8.376 ;
    END
  END dq[24]
  PIN dq[250]
    DIRECTION OUTPUT ;
    USE SIGNAL ;
    PORT
      LAYER M4 ;
        RECT  36.528 45.408 36.72 45.432 ;
    END
  END dq[250]
  PIN dq[251]
    DIRECTION OUTPUT ;
    USE SIGNAL ;
    PORT
      LAYER M4 ;
        RECT  36.528 45.552 36.72 45.576 ;
    END
  END dq[251]
  PIN dq[252]
    DIRECTION OUTPUT ;
    USE SIGNAL ;
    PORT
      LAYER M4 ;
        RECT  36.528 45.696 36.72 45.72 ;
    END
  END dq[252]
  PIN dq[253]
    DIRECTION OUTPUT ;
    USE SIGNAL ;
    PORT
      LAYER M4 ;
        RECT  36.528 45.888 36.72 45.912 ;
    END
  END dq[253]
  PIN dq[254]
    DIRECTION OUTPUT ;
    USE SIGNAL ;
    PORT
      LAYER M4 ;
        RECT  36.528 46.032 36.72 46.056 ;
    END
  END dq[254]
  PIN dq[255]
    DIRECTION OUTPUT ;
    USE SIGNAL ;
    PORT
      LAYER M4 ;
        RECT  36.528 46.224 36.72 46.248 ;
    END
  END dq[255]
  PIN dq[256]
    DIRECTION OUTPUT ;
    USE SIGNAL ;
    PORT
      LAYER M4 ;
        RECT  36.528 46.368 36.72 46.392 ;
    END
  END dq[256]
  PIN dq[257]
    DIRECTION OUTPUT ;
    USE SIGNAL ;
    PORT
      LAYER M4 ;
        RECT  36.528 46.512 36.72 46.536 ;
    END
  END dq[257]
  PIN dq[258]
    DIRECTION OUTPUT ;
    USE SIGNAL ;
    PORT
      LAYER M4 ;
        RECT  36.528 46.704 36.72 46.728 ;
    END
  END dq[258]
  PIN dq[259]
    DIRECTION OUTPUT ;
    USE SIGNAL ;
    PORT
      LAYER M4 ;
        RECT  36.528 46.848 36.72 46.872 ;
    END
  END dq[259]
  PIN dq[25]
    DIRECTION OUTPUT ;
    USE SIGNAL ;
    PORT
      LAYER M4 ;
        RECT  36.528 8.496 36.72 8.52 ;
    END
  END dq[25]
  PIN dq[260]
    DIRECTION OUTPUT ;
    USE SIGNAL ;
    PORT
      LAYER M4 ;
        RECT  36.528 47.04 36.72 47.064 ;
    END
  END dq[260]
  PIN dq[261]
    DIRECTION OUTPUT ;
    USE SIGNAL ;
    PORT
      LAYER M4 ;
        RECT  36.528 47.184 36.72 47.208 ;
    END
  END dq[261]
  PIN dq[262]
    DIRECTION OUTPUT ;
    USE SIGNAL ;
    PORT
      LAYER M4 ;
        RECT  36.528 47.376 36.72 47.4 ;
    END
  END dq[262]
  PIN dq[263]
    DIRECTION OUTPUT ;
    USE SIGNAL ;
    PORT
      LAYER M4 ;
        RECT  36.528 47.52 36.72 47.544 ;
    END
  END dq[263]
  PIN dq[264]
    DIRECTION OUTPUT ;
    USE SIGNAL ;
    PORT
      LAYER M4 ;
        RECT  36.528 47.664 36.72 47.688 ;
    END
  END dq[264]
  PIN dq[265]
    DIRECTION OUTPUT ;
    USE SIGNAL ;
    PORT
      LAYER M4 ;
        RECT  36.528 47.856 36.72 47.88 ;
    END
  END dq[265]
  PIN dq[266]
    DIRECTION OUTPUT ;
    USE SIGNAL ;
    PORT
      LAYER M4 ;
        RECT  36.528 48 36.72 48.024 ;
    END
  END dq[266]
  PIN dq[267]
    DIRECTION OUTPUT ;
    USE SIGNAL ;
    PORT
      LAYER M4 ;
        RECT  36.528 48.192 36.72 48.216 ;
    END
  END dq[267]
  PIN dq[268]
    DIRECTION OUTPUT ;
    USE SIGNAL ;
    PORT
      LAYER M4 ;
        RECT  36.528 48.336 36.72 48.36 ;
    END
  END dq[268]
  PIN dq[269]
    DIRECTION OUTPUT ;
    USE SIGNAL ;
    PORT
      LAYER M4 ;
        RECT  36.528 48.48 36.72 48.504 ;
    END
  END dq[269]
  PIN dq[26]
    DIRECTION OUTPUT ;
    USE SIGNAL ;
    PORT
      LAYER M4 ;
        RECT  36.528 8.688 36.72 8.712 ;
    END
  END dq[26]
  PIN dq[270]
    DIRECTION OUTPUT ;
    USE SIGNAL ;
    PORT
      LAYER M4 ;
        RECT  36.528 48.672 36.72 48.696 ;
    END
  END dq[270]
  PIN dq[271]
    DIRECTION OUTPUT ;
    USE SIGNAL ;
    PORT
      LAYER M4 ;
        RECT  36.528 48.816 36.72 48.84 ;
    END
  END dq[271]
  PIN dq[272]
    DIRECTION OUTPUT ;
    USE SIGNAL ;
    PORT
      LAYER M4 ;
        RECT  36.528 49.008 36.72 49.032 ;
    END
  END dq[272]
  PIN dq[273]
    DIRECTION OUTPUT ;
    USE SIGNAL ;
    PORT
      LAYER M4 ;
        RECT  36.528 49.152 36.72 49.176 ;
    END
  END dq[273]
  PIN dq[274]
    DIRECTION OUTPUT ;
    USE SIGNAL ;
    PORT
      LAYER M4 ;
        RECT  36.528 49.344 36.72 49.368 ;
    END
  END dq[274]
  PIN dq[275]
    DIRECTION OUTPUT ;
    USE SIGNAL ;
    PORT
      LAYER M4 ;
        RECT  36.528 49.488 36.72 49.512 ;
    END
  END dq[275]
  PIN dq[276]
    DIRECTION OUTPUT ;
    USE SIGNAL ;
    PORT
      LAYER M4 ;
        RECT  36.528 49.632 36.72 49.656 ;
    END
  END dq[276]
  PIN dq[277]
    DIRECTION OUTPUT ;
    USE SIGNAL ;
    PORT
      LAYER M4 ;
        RECT  36.528 49.824 36.72 49.848 ;
    END
  END dq[277]
  PIN dq[278]
    DIRECTION OUTPUT ;
    USE SIGNAL ;
    PORT
      LAYER M4 ;
        RECT  36.528 49.968 36.72 49.992 ;
    END
  END dq[278]
  PIN dq[279]
    DIRECTION OUTPUT ;
    USE SIGNAL ;
    PORT
      LAYER M4 ;
        RECT  36.528 50.16 36.72 50.184 ;
    END
  END dq[279]
  PIN dq[27]
    DIRECTION OUTPUT ;
    USE SIGNAL ;
    PORT
      LAYER M4 ;
        RECT  36.528 8.832 36.72 8.856 ;
    END
  END dq[27]
  PIN dq[280]
    DIRECTION OUTPUT ;
    USE SIGNAL ;
    PORT
      LAYER M4 ;
        RECT  36.528 50.304 36.72 50.328 ;
    END
  END dq[280]
  PIN dq[281]
    DIRECTION OUTPUT ;
    USE SIGNAL ;
    PORT
      LAYER M4 ;
        RECT  36.528 50.448 36.72 50.472 ;
    END
  END dq[281]
  PIN dq[282]
    DIRECTION OUTPUT ;
    USE SIGNAL ;
    PORT
      LAYER M4 ;
        RECT  36.528 50.64 36.72 50.664 ;
    END
  END dq[282]
  PIN dq[283]
    DIRECTION OUTPUT ;
    USE SIGNAL ;
    PORT
      LAYER M4 ;
        RECT  36.528 50.784 36.72 50.808 ;
    END
  END dq[283]
  PIN dq[284]
    DIRECTION OUTPUT ;
    USE SIGNAL ;
    PORT
      LAYER M4 ;
        RECT  36.528 50.976 36.72 51 ;
    END
  END dq[284]
  PIN dq[285]
    DIRECTION OUTPUT ;
    USE SIGNAL ;
    PORT
      LAYER M4 ;
        RECT  36.528 51.12 36.72 51.144 ;
    END
  END dq[285]
  PIN dq[286]
    DIRECTION OUTPUT ;
    USE SIGNAL ;
    PORT
      LAYER M4 ;
        RECT  36.528 51.264 36.72 51.288 ;
    END
  END dq[286]
  PIN dq[287]
    DIRECTION OUTPUT ;
    USE SIGNAL ;
    PORT
      LAYER M4 ;
        RECT  36.528 51.456 36.72 51.48 ;
    END
  END dq[287]
  PIN dq[288]
    DIRECTION OUTPUT ;
    USE SIGNAL ;
    PORT
      LAYER M4 ;
        RECT  36.528 51.6 36.72 51.624 ;
    END
  END dq[288]
  PIN dq[289]
    DIRECTION OUTPUT ;
    USE SIGNAL ;
    PORT
      LAYER M4 ;
        RECT  36.528 51.792 36.72 51.816 ;
    END
  END dq[289]
  PIN dq[28]
    DIRECTION OUTPUT ;
    USE SIGNAL ;
    PORT
      LAYER M4 ;
        RECT  36.528 9.024 36.72 9.048 ;
    END
  END dq[28]
  PIN dq[290]
    DIRECTION OUTPUT ;
    USE SIGNAL ;
    PORT
      LAYER M4 ;
        RECT  36.528 51.936 36.72 51.96 ;
    END
  END dq[290]
  PIN dq[291]
    DIRECTION OUTPUT ;
    USE SIGNAL ;
    PORT
      LAYER M4 ;
        RECT  36.528 52.128 36.72 52.152 ;
    END
  END dq[291]
  PIN dq[292]
    DIRECTION OUTPUT ;
    USE SIGNAL ;
    PORT
      LAYER M4 ;
        RECT  36.528 52.272 36.72 52.296 ;
    END
  END dq[292]
  PIN dq[293]
    DIRECTION OUTPUT ;
    USE SIGNAL ;
    PORT
      LAYER M4 ;
        RECT  36.528 52.416 36.72 52.44 ;
    END
  END dq[293]
  PIN dq[294]
    DIRECTION OUTPUT ;
    USE SIGNAL ;
    PORT
      LAYER M4 ;
        RECT  36.528 52.608 36.72 52.632 ;
    END
  END dq[294]
  PIN dq[295]
    DIRECTION OUTPUT ;
    USE SIGNAL ;
    PORT
      LAYER M4 ;
        RECT  36.528 52.752 36.72 52.776 ;
    END
  END dq[295]
  PIN dq[296]
    DIRECTION OUTPUT ;
    USE SIGNAL ;
    PORT
      LAYER M4 ;
        RECT  36.528 52.944 36.72 52.968 ;
    END
  END dq[296]
  PIN dq[297]
    DIRECTION OUTPUT ;
    USE SIGNAL ;
    PORT
      LAYER M4 ;
        RECT  36.528 53.088 36.72 53.112 ;
    END
  END dq[297]
  PIN dq[298]
    DIRECTION OUTPUT ;
    USE SIGNAL ;
    PORT
      LAYER M4 ;
        RECT  36.528 53.232 36.72 53.256 ;
    END
  END dq[298]
  PIN dq[299]
    DIRECTION OUTPUT ;
    USE SIGNAL ;
    PORT
      LAYER M4 ;
        RECT  36.528 53.424 36.72 53.448 ;
    END
  END dq[299]
  PIN dq[29]
    DIRECTION OUTPUT ;
    USE SIGNAL ;
    PORT
      LAYER M4 ;
        RECT  36.528 9.168 36.72 9.192 ;
    END
  END dq[29]
  PIN dq[2]
    DIRECTION OUTPUT ;
    USE SIGNAL ;
    PORT
      LAYER M4 ;
        RECT  36.528 4.752 36.72 4.776 ;
    END
  END dq[2]
  PIN dq[300]
    DIRECTION OUTPUT ;
    USE SIGNAL ;
    PORT
      LAYER M4 ;
        RECT  36.528 53.568 36.72 53.592 ;
    END
  END dq[300]
  PIN dq[301]
    DIRECTION OUTPUT ;
    USE SIGNAL ;
    PORT
      LAYER M4 ;
        RECT  36.528 53.76 36.72 53.784 ;
    END
  END dq[301]
  PIN dq[302]
    DIRECTION OUTPUT ;
    USE SIGNAL ;
    PORT
      LAYER M4 ;
        RECT  36.528 53.904 36.72 53.928 ;
    END
  END dq[302]
  PIN dq[303]
    DIRECTION OUTPUT ;
    USE SIGNAL ;
    PORT
      LAYER M4 ;
        RECT  36.528 54.096 36.72 54.12 ;
    END
  END dq[303]
  PIN dq[304]
    DIRECTION OUTPUT ;
    USE SIGNAL ;
    PORT
      LAYER M4 ;
        RECT  36.528 54.24 36.72 54.264 ;
    END
  END dq[304]
  PIN dq[305]
    DIRECTION OUTPUT ;
    USE SIGNAL ;
    PORT
      LAYER M4 ;
        RECT  36.528 54.384 36.72 54.408 ;
    END
  END dq[305]
  PIN dq[306]
    DIRECTION OUTPUT ;
    USE SIGNAL ;
    PORT
      LAYER M4 ;
        RECT  36.528 54.576 36.72 54.6 ;
    END
  END dq[306]
  PIN dq[307]
    DIRECTION OUTPUT ;
    USE SIGNAL ;
    PORT
      LAYER M4 ;
        RECT  36.528 54.72 36.72 54.744 ;
    END
  END dq[307]
  PIN dq[308]
    DIRECTION OUTPUT ;
    USE SIGNAL ;
    PORT
      LAYER M4 ;
        RECT  36.528 54.912 36.72 54.936 ;
    END
  END dq[308]
  PIN dq[309]
    DIRECTION OUTPUT ;
    USE SIGNAL ;
    PORT
      LAYER M4 ;
        RECT  36.528 55.056 36.72 55.08 ;
    END
  END dq[309]
  PIN dq[30]
    DIRECTION OUTPUT ;
    USE SIGNAL ;
    PORT
      LAYER M4 ;
        RECT  36.528 9.312 36.72 9.336 ;
    END
  END dq[30]
  PIN dq[310]
    DIRECTION OUTPUT ;
    USE SIGNAL ;
    PORT
      LAYER M4 ;
        RECT  36.528 55.2 36.72 55.224 ;
    END
  END dq[310]
  PIN dq[311]
    DIRECTION OUTPUT ;
    USE SIGNAL ;
    PORT
      LAYER M4 ;
        RECT  36.528 55.392 36.72 55.416 ;
    END
  END dq[311]
  PIN dq[312]
    DIRECTION OUTPUT ;
    USE SIGNAL ;
    PORT
      LAYER M4 ;
        RECT  36.528 55.536 36.72 55.56 ;
    END
  END dq[312]
  PIN dq[313]
    DIRECTION OUTPUT ;
    USE SIGNAL ;
    PORT
      LAYER M4 ;
        RECT  36.528 55.728 36.72 55.752 ;
    END
  END dq[313]
  PIN dq[314]
    DIRECTION OUTPUT ;
    USE SIGNAL ;
    PORT
      LAYER M4 ;
        RECT  36.528 55.872 36.72 55.896 ;
    END
  END dq[314]
  PIN dq[315]
    DIRECTION OUTPUT ;
    USE SIGNAL ;
    PORT
      LAYER M4 ;
        RECT  36.528 56.016 36.72 56.04 ;
    END
  END dq[315]
  PIN dq[316]
    DIRECTION OUTPUT ;
    USE SIGNAL ;
    PORT
      LAYER M4 ;
        RECT  36.528 56.208 36.72 56.232 ;
    END
  END dq[316]
  PIN dq[317]
    DIRECTION OUTPUT ;
    USE SIGNAL ;
    PORT
      LAYER M4 ;
        RECT  36.528 56.352 36.72 56.376 ;
    END
  END dq[317]
  PIN dq[318]
    DIRECTION OUTPUT ;
    USE SIGNAL ;
    PORT
      LAYER M4 ;
        RECT  36.528 56.544 36.72 56.568 ;
    END
  END dq[318]
  PIN dq[319]
    DIRECTION OUTPUT ;
    USE SIGNAL ;
    PORT
      LAYER M4 ;
        RECT  36.528 56.688 36.72 56.712 ;
    END
  END dq[319]
  PIN dq[31]
    DIRECTION OUTPUT ;
    USE SIGNAL ;
    PORT
      LAYER M4 ;
        RECT  36.528 9.504 36.72 9.528 ;
    END
  END dq[31]
  PIN dq[320]
    DIRECTION OUTPUT ;
    USE SIGNAL ;
    PORT
      LAYER M4 ;
        RECT  36.528 56.88 36.72 56.904 ;
    END
  END dq[320]
  PIN dq[321]
    DIRECTION OUTPUT ;
    USE SIGNAL ;
    PORT
      LAYER M4 ;
        RECT  36.528 57.024 36.72 57.048 ;
    END
  END dq[321]
  PIN dq[322]
    DIRECTION OUTPUT ;
    USE SIGNAL ;
    PORT
      LAYER M4 ;
        RECT  36.528 57.168 36.72 57.192 ;
    END
  END dq[322]
  PIN dq[323]
    DIRECTION OUTPUT ;
    USE SIGNAL ;
    PORT
      LAYER M4 ;
        RECT  36.528 57.36 36.72 57.384 ;
    END
  END dq[323]
  PIN dq[324]
    DIRECTION OUTPUT ;
    USE SIGNAL ;
    PORT
      LAYER M4 ;
        RECT  36.528 57.504 36.72 57.528 ;
    END
  END dq[324]
  PIN dq[325]
    DIRECTION OUTPUT ;
    USE SIGNAL ;
    PORT
      LAYER M4 ;
        RECT  36.528 57.696 36.72 57.72 ;
    END
  END dq[325]
  PIN dq[326]
    DIRECTION OUTPUT ;
    USE SIGNAL ;
    PORT
      LAYER M4 ;
        RECT  36.528 57.84 36.72 57.864 ;
    END
  END dq[326]
  PIN dq[327]
    DIRECTION OUTPUT ;
    USE SIGNAL ;
    PORT
      LAYER M4 ;
        RECT  36.528 57.984 36.72 58.008 ;
    END
  END dq[327]
  PIN dq[328]
    DIRECTION OUTPUT ;
    USE SIGNAL ;
    PORT
      LAYER M4 ;
        RECT  36.528 58.176 36.72 58.2 ;
    END
  END dq[328]
  PIN dq[329]
    DIRECTION OUTPUT ;
    USE SIGNAL ;
    PORT
      LAYER M4 ;
        RECT  36.528 58.32 36.72 58.344 ;
    END
  END dq[329]
  PIN dq[32]
    DIRECTION OUTPUT ;
    USE SIGNAL ;
    PORT
      LAYER M4 ;
        RECT  36.528 9.648 36.72 9.672 ;
    END
  END dq[32]
  PIN dq[330]
    DIRECTION OUTPUT ;
    USE SIGNAL ;
    PORT
      LAYER M4 ;
        RECT  36.528 58.512 36.72 58.536 ;
    END
  END dq[330]
  PIN dq[331]
    DIRECTION OUTPUT ;
    USE SIGNAL ;
    PORT
      LAYER M4 ;
        RECT  36.528 58.656 36.72 58.68 ;
    END
  END dq[331]
  PIN dq[332]
    DIRECTION OUTPUT ;
    USE SIGNAL ;
    PORT
      LAYER M4 ;
        RECT  36.528 58.848 36.72 58.872 ;
    END
  END dq[332]
  PIN dq[333]
    DIRECTION OUTPUT ;
    USE SIGNAL ;
    PORT
      LAYER M4 ;
        RECT  36.528 58.992 36.72 59.016 ;
    END
  END dq[333]
  PIN dq[334]
    DIRECTION OUTPUT ;
    USE SIGNAL ;
    PORT
      LAYER M4 ;
        RECT  36.528 59.136 36.72 59.16 ;
    END
  END dq[334]
  PIN dq[335]
    DIRECTION OUTPUT ;
    USE SIGNAL ;
    PORT
      LAYER M4 ;
        RECT  36.528 59.328 36.72 59.352 ;
    END
  END dq[335]
  PIN dq[336]
    DIRECTION OUTPUT ;
    USE SIGNAL ;
    PORT
      LAYER M4 ;
        RECT  36.528 59.472 36.72 59.496 ;
    END
  END dq[336]
  PIN dq[337]
    DIRECTION OUTPUT ;
    USE SIGNAL ;
    PORT
      LAYER M4 ;
        RECT  36.528 59.664 36.72 59.688 ;
    END
  END dq[337]
  PIN dq[338]
    DIRECTION OUTPUT ;
    USE SIGNAL ;
    PORT
      LAYER M4 ;
        RECT  36.528 59.808 36.72 59.832 ;
    END
  END dq[338]
  PIN dq[339]
    DIRECTION OUTPUT ;
    USE SIGNAL ;
    PORT
      LAYER M4 ;
        RECT  36.528 59.952 36.72 59.976 ;
    END
  END dq[339]
  PIN dq[33]
    DIRECTION OUTPUT ;
    USE SIGNAL ;
    PORT
      LAYER M4 ;
        RECT  36.528 9.84 36.72 9.864 ;
    END
  END dq[33]
  PIN dq[340]
    DIRECTION OUTPUT ;
    USE SIGNAL ;
    PORT
      LAYER M4 ;
        RECT  36.528 60.144 36.72 60.168 ;
    END
  END dq[340]
  PIN dq[341]
    DIRECTION OUTPUT ;
    USE SIGNAL ;
    PORT
      LAYER M4 ;
        RECT  36.528 60.288 36.72 60.312 ;
    END
  END dq[341]
  PIN dq[342]
    DIRECTION OUTPUT ;
    USE SIGNAL ;
    PORT
      LAYER M4 ;
        RECT  36.528 60.48 36.72 60.504 ;
    END
  END dq[342]
  PIN dq[343]
    DIRECTION OUTPUT ;
    USE SIGNAL ;
    PORT
      LAYER M4 ;
        RECT  36.528 60.624 36.72 60.648 ;
    END
  END dq[343]
  PIN dq[344]
    DIRECTION OUTPUT ;
    USE SIGNAL ;
    PORT
      LAYER M4 ;
        RECT  36.528 60.816 36.72 60.84 ;
    END
  END dq[344]
  PIN dq[345]
    DIRECTION OUTPUT ;
    USE SIGNAL ;
    PORT
      LAYER M4 ;
        RECT  36.528 60.96 36.72 60.984 ;
    END
  END dq[345]
  PIN dq[346]
    DIRECTION OUTPUT ;
    USE SIGNAL ;
    PORT
      LAYER M4 ;
        RECT  36.528 61.104 36.72 61.128 ;
    END
  END dq[346]
  PIN dq[347]
    DIRECTION OUTPUT ;
    USE SIGNAL ;
    PORT
      LAYER M4 ;
        RECT  36.528 61.296 36.72 61.32 ;
    END
  END dq[347]
  PIN dq[348]
    DIRECTION OUTPUT ;
    USE SIGNAL ;
    PORT
      LAYER M4 ;
        RECT  36.528 61.44 36.72 61.464 ;
    END
  END dq[348]
  PIN dq[349]
    DIRECTION OUTPUT ;
    USE SIGNAL ;
    PORT
      LAYER M4 ;
        RECT  36.528 61.632 36.72 61.656 ;
    END
  END dq[349]
  PIN dq[34]
    DIRECTION OUTPUT ;
    USE SIGNAL ;
    PORT
      LAYER M4 ;
        RECT  36.528 9.984 36.72 10.008 ;
    END
  END dq[34]
  PIN dq[350]
    DIRECTION OUTPUT ;
    USE SIGNAL ;
    PORT
      LAYER M4 ;
        RECT  36.528 61.776 36.72 61.8 ;
    END
  END dq[350]
  PIN dq[351]
    DIRECTION OUTPUT ;
    USE SIGNAL ;
    PORT
      LAYER M4 ;
        RECT  36.528 61.92 36.72 61.944 ;
    END
  END dq[351]
  PIN dq[352]
    DIRECTION OUTPUT ;
    USE SIGNAL ;
    PORT
      LAYER M4 ;
        RECT  36.528 62.112 36.72 62.136 ;
    END
  END dq[352]
  PIN dq[353]
    DIRECTION OUTPUT ;
    USE SIGNAL ;
    PORT
      LAYER M4 ;
        RECT  36.528 62.256 36.72 62.28 ;
    END
  END dq[353]
  PIN dq[354]
    DIRECTION OUTPUT ;
    USE SIGNAL ;
    PORT
      LAYER M4 ;
        RECT  36.528 62.448 36.72 62.472 ;
    END
  END dq[354]
  PIN dq[355]
    DIRECTION OUTPUT ;
    USE SIGNAL ;
    PORT
      LAYER M4 ;
        RECT  36.528 62.592 36.72 62.616 ;
    END
  END dq[355]
  PIN dq[356]
    DIRECTION OUTPUT ;
    USE SIGNAL ;
    PORT
      LAYER M4 ;
        RECT  36.528 62.736 36.72 62.76 ;
    END
  END dq[356]
  PIN dq[357]
    DIRECTION OUTPUT ;
    USE SIGNAL ;
    PORT
      LAYER M4 ;
        RECT  36.528 62.928 36.72 62.952 ;
    END
  END dq[357]
  PIN dq[358]
    DIRECTION OUTPUT ;
    USE SIGNAL ;
    PORT
      LAYER M4 ;
        RECT  36.528 63.072 36.72 63.096 ;
    END
  END dq[358]
  PIN dq[359]
    DIRECTION OUTPUT ;
    USE SIGNAL ;
    PORT
      LAYER M4 ;
        RECT  36.528 63.264 36.72 63.288 ;
    END
  END dq[359]
  PIN dq[35]
    DIRECTION OUTPUT ;
    USE SIGNAL ;
    PORT
      LAYER M4 ;
        RECT  36.528 10.128 36.72 10.152 ;
    END
  END dq[35]
  PIN dq[360]
    DIRECTION OUTPUT ;
    USE SIGNAL ;
    PORT
      LAYER M4 ;
        RECT  36.528 63.408 36.72 63.432 ;
    END
  END dq[360]
  PIN dq[361]
    DIRECTION OUTPUT ;
    USE SIGNAL ;
    PORT
      LAYER M4 ;
        RECT  36.528 63.6 36.72 63.624 ;
    END
  END dq[361]
  PIN dq[362]
    DIRECTION OUTPUT ;
    USE SIGNAL ;
    PORT
      LAYER M4 ;
        RECT  36.528 63.744 36.72 63.768 ;
    END
  END dq[362]
  PIN dq[363]
    DIRECTION OUTPUT ;
    USE SIGNAL ;
    PORT
      LAYER M4 ;
        RECT  36.528 63.888 36.72 63.912 ;
    END
  END dq[363]
  PIN dq[364]
    DIRECTION OUTPUT ;
    USE SIGNAL ;
    PORT
      LAYER M4 ;
        RECT  36.528 64.08 36.72 64.104 ;
    END
  END dq[364]
  PIN dq[365]
    DIRECTION OUTPUT ;
    USE SIGNAL ;
    PORT
      LAYER M4 ;
        RECT  36.528 64.224 36.72 64.248 ;
    END
  END dq[365]
  PIN dq[366]
    DIRECTION OUTPUT ;
    USE SIGNAL ;
    PORT
      LAYER M4 ;
        RECT  36.528 64.416 36.72 64.44 ;
    END
  END dq[366]
  PIN dq[367]
    DIRECTION OUTPUT ;
    USE SIGNAL ;
    PORT
      LAYER M4 ;
        RECT  36.528 64.56 36.72 64.584 ;
    END
  END dq[367]
  PIN dq[368]
    DIRECTION OUTPUT ;
    USE SIGNAL ;
    PORT
      LAYER M4 ;
        RECT  36.528 64.704 36.72 64.728 ;
    END
  END dq[368]
  PIN dq[369]
    DIRECTION OUTPUT ;
    USE SIGNAL ;
    PORT
      LAYER M4 ;
        RECT  36.528 64.896 36.72 64.92 ;
    END
  END dq[369]
  PIN dq[36]
    DIRECTION OUTPUT ;
    USE SIGNAL ;
    PORT
      LAYER M4 ;
        RECT  36.528 10.32 36.72 10.344 ;
    END
  END dq[36]
  PIN dq[370]
    DIRECTION OUTPUT ;
    USE SIGNAL ;
    PORT
      LAYER M4 ;
        RECT  36.528 65.04 36.72 65.064 ;
    END
  END dq[370]
  PIN dq[371]
    DIRECTION OUTPUT ;
    USE SIGNAL ;
    PORT
      LAYER M4 ;
        RECT  36.528 65.232 36.72 65.256 ;
    END
  END dq[371]
  PIN dq[372]
    DIRECTION OUTPUT ;
    USE SIGNAL ;
    PORT
      LAYER M4 ;
        RECT  36.528 65.376 36.72 65.4 ;
    END
  END dq[372]
  PIN dq[373]
    DIRECTION OUTPUT ;
    USE SIGNAL ;
    PORT
      LAYER M4 ;
        RECT  36.528 65.568 36.72 65.592 ;
    END
  END dq[373]
  PIN dq[374]
    DIRECTION OUTPUT ;
    USE SIGNAL ;
    PORT
      LAYER M4 ;
        RECT  36.528 65.712 36.72 65.736 ;
    END
  END dq[374]
  PIN dq[375]
    DIRECTION OUTPUT ;
    USE SIGNAL ;
    PORT
      LAYER M4 ;
        RECT  36.528 65.856 36.72 65.88 ;
    END
  END dq[375]
  PIN dq[376]
    DIRECTION OUTPUT ;
    USE SIGNAL ;
    PORT
      LAYER M4 ;
        RECT  36.528 66.048 36.72 66.072 ;
    END
  END dq[376]
  PIN dq[377]
    DIRECTION OUTPUT ;
    USE SIGNAL ;
    PORT
      LAYER M4 ;
        RECT  36.528 66.192 36.72 66.216 ;
    END
  END dq[377]
  PIN dq[378]
    DIRECTION OUTPUT ;
    USE SIGNAL ;
    PORT
      LAYER M4 ;
        RECT  36.528 66.384 36.72 66.408 ;
    END
  END dq[378]
  PIN dq[379]
    DIRECTION OUTPUT ;
    USE SIGNAL ;
    PORT
      LAYER M4 ;
        RECT  36.528 66.528 36.72 66.552 ;
    END
  END dq[379]
  PIN dq[37]
    DIRECTION OUTPUT ;
    USE SIGNAL ;
    PORT
      LAYER M4 ;
        RECT  36.528 10.464 36.72 10.488 ;
    END
  END dq[37]
  PIN dq[380]
    DIRECTION OUTPUT ;
    USE SIGNAL ;
    PORT
      LAYER M4 ;
        RECT  36.528 66.672 36.72 66.696 ;
    END
  END dq[380]
  PIN dq[381]
    DIRECTION OUTPUT ;
    USE SIGNAL ;
    PORT
      LAYER M4 ;
        RECT  36.528 66.864 36.72 66.888 ;
    END
  END dq[381]
  PIN dq[382]
    DIRECTION OUTPUT ;
    USE SIGNAL ;
    PORT
      LAYER M4 ;
        RECT  36.528 67.008 36.72 67.032 ;
    END
  END dq[382]
  PIN dq[383]
    DIRECTION OUTPUT ;
    USE SIGNAL ;
    PORT
      LAYER M4 ;
        RECT  36.528 67.2 36.72 67.224 ;
    END
  END dq[383]
  PIN dq[384]
    DIRECTION OUTPUT ;
    USE SIGNAL ;
    PORT
      LAYER M4 ;
        RECT  36.528 67.344 36.72 67.368 ;
    END
  END dq[384]
  PIN dq[385]
    DIRECTION OUTPUT ;
    USE SIGNAL ;
    PORT
      LAYER M4 ;
        RECT  36.528 67.536 36.72 67.56 ;
    END
  END dq[385]
  PIN dq[386]
    DIRECTION OUTPUT ;
    USE SIGNAL ;
    PORT
      LAYER M4 ;
        RECT  36.528 67.68 36.72 67.704 ;
    END
  END dq[386]
  PIN dq[387]
    DIRECTION OUTPUT ;
    USE SIGNAL ;
    PORT
      LAYER M4 ;
        RECT  36.528 67.824 36.72 67.848 ;
    END
  END dq[387]
  PIN dq[388]
    DIRECTION OUTPUT ;
    USE SIGNAL ;
    PORT
      LAYER M4 ;
        RECT  36.528 68.016 36.72 68.04 ;
    END
  END dq[388]
  PIN dq[389]
    DIRECTION OUTPUT ;
    USE SIGNAL ;
    PORT
      LAYER M4 ;
        RECT  36.528 68.16 36.72 68.184 ;
    END
  END dq[389]
  PIN dq[38]
    DIRECTION OUTPUT ;
    USE SIGNAL ;
    PORT
      LAYER M4 ;
        RECT  36.528 10.656 36.72 10.68 ;
    END
  END dq[38]
  PIN dq[390]
    DIRECTION OUTPUT ;
    USE SIGNAL ;
    PORT
      LAYER M4 ;
        RECT  36.528 68.352 36.72 68.376 ;
    END
  END dq[390]
  PIN dq[391]
    DIRECTION OUTPUT ;
    USE SIGNAL ;
    PORT
      LAYER M4 ;
        RECT  36.528 68.496 36.72 68.52 ;
    END
  END dq[391]
  PIN dq[392]
    DIRECTION OUTPUT ;
    USE SIGNAL ;
    PORT
      LAYER M4 ;
        RECT  36.528 68.64 36.72 68.664 ;
    END
  END dq[392]
  PIN dq[393]
    DIRECTION OUTPUT ;
    USE SIGNAL ;
    PORT
      LAYER M4 ;
        RECT  36.528 68.832 36.72 68.856 ;
    END
  END dq[393]
  PIN dq[394]
    DIRECTION OUTPUT ;
    USE SIGNAL ;
    PORT
      LAYER M4 ;
        RECT  36.528 68.976 36.72 69 ;
    END
  END dq[394]
  PIN dq[395]
    DIRECTION OUTPUT ;
    USE SIGNAL ;
    PORT
      LAYER M4 ;
        RECT  36.528 69.168 36.72 69.192 ;
    END
  END dq[395]
  PIN dq[396]
    DIRECTION OUTPUT ;
    USE SIGNAL ;
    PORT
      LAYER M4 ;
        RECT  36.528 69.312 36.72 69.336 ;
    END
  END dq[396]
  PIN dq[397]
    DIRECTION OUTPUT ;
    USE SIGNAL ;
    PORT
      LAYER M4 ;
        RECT  36.528 69.456 36.72 69.48 ;
    END
  END dq[397]
  PIN dq[398]
    DIRECTION OUTPUT ;
    USE SIGNAL ;
    PORT
      LAYER M4 ;
        RECT  36.528 69.648 36.72 69.672 ;
    END
  END dq[398]
  PIN dq[399]
    DIRECTION OUTPUT ;
    USE SIGNAL ;
    PORT
      LAYER M4 ;
        RECT  36.528 69.792 36.72 69.816 ;
    END
  END dq[399]
  PIN dq[39]
    DIRECTION OUTPUT ;
    USE SIGNAL ;
    PORT
      LAYER M4 ;
        RECT  36.528 10.8 36.72 10.824 ;
    END
  END dq[39]
  PIN dq[3]
    DIRECTION OUTPUT ;
    USE SIGNAL ;
    PORT
      LAYER M4 ;
        RECT  36.528 4.896 36.72 4.92 ;
    END
  END dq[3]
  PIN dq[400]
    DIRECTION OUTPUT ;
    USE SIGNAL ;
    PORT
      LAYER M4 ;
        RECT  36.528 69.984 36.72 70.008 ;
    END
  END dq[400]
  PIN dq[401]
    DIRECTION OUTPUT ;
    USE SIGNAL ;
    PORT
      LAYER M4 ;
        RECT  36.528 70.128 36.72 70.152 ;
    END
  END dq[401]
  PIN dq[402]
    DIRECTION OUTPUT ;
    USE SIGNAL ;
    PORT
      LAYER M4 ;
        RECT  36.528 70.32 36.72 70.344 ;
    END
  END dq[402]
  PIN dq[403]
    DIRECTION OUTPUT ;
    USE SIGNAL ;
    PORT
      LAYER M4 ;
        RECT  36.528 70.464 36.72 70.488 ;
    END
  END dq[403]
  PIN dq[404]
    DIRECTION OUTPUT ;
    USE SIGNAL ;
    PORT
      LAYER M4 ;
        RECT  36.528 70.608 36.72 70.632 ;
    END
  END dq[404]
  PIN dq[405]
    DIRECTION OUTPUT ;
    USE SIGNAL ;
    PORT
      LAYER M4 ;
        RECT  36.528 70.8 36.72 70.824 ;
    END
  END dq[405]
  PIN dq[406]
    DIRECTION OUTPUT ;
    USE SIGNAL ;
    PORT
      LAYER M4 ;
        RECT  36.528 70.944 36.72 70.968 ;
    END
  END dq[406]
  PIN dq[407]
    DIRECTION OUTPUT ;
    USE SIGNAL ;
    PORT
      LAYER M4 ;
        RECT  36.528 71.136 36.72 71.16 ;
    END
  END dq[407]
  PIN dq[408]
    DIRECTION OUTPUT ;
    USE SIGNAL ;
    PORT
      LAYER M4 ;
        RECT  36.528 71.28 36.72 71.304 ;
    END
  END dq[408]
  PIN dq[409]
    DIRECTION OUTPUT ;
    USE SIGNAL ;
    PORT
      LAYER M4 ;
        RECT  36.528 71.424 36.72 71.448 ;
    END
  END dq[409]
  PIN dq[40]
    DIRECTION OUTPUT ;
    USE SIGNAL ;
    PORT
      LAYER M4 ;
        RECT  36.528 10.992 36.72 11.016 ;
    END
  END dq[40]
  PIN dq[410]
    DIRECTION OUTPUT ;
    USE SIGNAL ;
    PORT
      LAYER M4 ;
        RECT  36.528 71.616 36.72 71.64 ;
    END
  END dq[410]
  PIN dq[411]
    DIRECTION OUTPUT ;
    USE SIGNAL ;
    PORT
      LAYER M4 ;
        RECT  36.528 71.76 36.72 71.784 ;
    END
  END dq[411]
  PIN dq[412]
    DIRECTION OUTPUT ;
    USE SIGNAL ;
    PORT
      LAYER M4 ;
        RECT  36.528 71.952 36.72 71.976 ;
    END
  END dq[412]
  PIN dq[413]
    DIRECTION OUTPUT ;
    USE SIGNAL ;
    PORT
      LAYER M4 ;
        RECT  36.528 72.096 36.72 72.12 ;
    END
  END dq[413]
  PIN dq[414]
    DIRECTION OUTPUT ;
    USE SIGNAL ;
    PORT
      LAYER M4 ;
        RECT  36.528 72.288 36.72 72.312 ;
    END
  END dq[414]
  PIN dq[415]
    DIRECTION OUTPUT ;
    USE SIGNAL ;
    PORT
      LAYER M4 ;
        RECT  36.528 72.432 36.72 72.456 ;
    END
  END dq[415]
  PIN dq[416]
    DIRECTION OUTPUT ;
    USE SIGNAL ;
    PORT
      LAYER M4 ;
        RECT  36.528 72.576 36.72 72.6 ;
    END
  END dq[416]
  PIN dq[417]
    DIRECTION OUTPUT ;
    USE SIGNAL ;
    PORT
      LAYER M4 ;
        RECT  36.528 72.768 36.72 72.792 ;
    END
  END dq[417]
  PIN dq[418]
    DIRECTION OUTPUT ;
    USE SIGNAL ;
    PORT
      LAYER M4 ;
        RECT  36.528 72.912 36.72 72.936 ;
    END
  END dq[418]
  PIN dq[419]
    DIRECTION OUTPUT ;
    USE SIGNAL ;
    PORT
      LAYER M4 ;
        RECT  36.528 73.104 36.72 73.128 ;
    END
  END dq[419]
  PIN dq[41]
    DIRECTION OUTPUT ;
    USE SIGNAL ;
    PORT
      LAYER M4 ;
        RECT  36.528 11.136 36.72 11.16 ;
    END
  END dq[41]
  PIN dq[420]
    DIRECTION OUTPUT ;
    USE SIGNAL ;
    PORT
      LAYER M4 ;
        RECT  36.528 73.248 36.72 73.272 ;
    END
  END dq[420]
  PIN dq[421]
    DIRECTION OUTPUT ;
    USE SIGNAL ;
    PORT
      LAYER M4 ;
        RECT  36.528 73.392 36.72 73.416 ;
    END
  END dq[421]
  PIN dq[422]
    DIRECTION OUTPUT ;
    USE SIGNAL ;
    PORT
      LAYER M4 ;
        RECT  36.528 73.584 36.72 73.608 ;
    END
  END dq[422]
  PIN dq[423]
    DIRECTION OUTPUT ;
    USE SIGNAL ;
    PORT
      LAYER M4 ;
        RECT  36.528 73.728 36.72 73.752 ;
    END
  END dq[423]
  PIN dq[424]
    DIRECTION OUTPUT ;
    USE SIGNAL ;
    PORT
      LAYER M4 ;
        RECT  36.528 73.92 36.72 73.944 ;
    END
  END dq[424]
  PIN dq[425]
    DIRECTION OUTPUT ;
    USE SIGNAL ;
    PORT
      LAYER M4 ;
        RECT  36.528 74.064 36.72 74.088 ;
    END
  END dq[425]
  PIN dq[426]
    DIRECTION OUTPUT ;
    USE SIGNAL ;
    PORT
      LAYER M4 ;
        RECT  36.528 74.208 36.72 74.232 ;
    END
  END dq[426]
  PIN dq[427]
    DIRECTION OUTPUT ;
    USE SIGNAL ;
    PORT
      LAYER M4 ;
        RECT  36.528 74.4 36.72 74.424 ;
    END
  END dq[427]
  PIN dq[428]
    DIRECTION OUTPUT ;
    USE SIGNAL ;
    PORT
      LAYER M4 ;
        RECT  36.528 74.544 36.72 74.568 ;
    END
  END dq[428]
  PIN dq[429]
    DIRECTION OUTPUT ;
    USE SIGNAL ;
    PORT
      LAYER M4 ;
        RECT  36.528 74.736 36.72 74.76 ;
    END
  END dq[429]
  PIN dq[42]
    DIRECTION OUTPUT ;
    USE SIGNAL ;
    PORT
      LAYER M4 ;
        RECT  36.528 11.28 36.72 11.304 ;
    END
  END dq[42]
  PIN dq[430]
    DIRECTION OUTPUT ;
    USE SIGNAL ;
    PORT
      LAYER M4 ;
        RECT  36.528 74.88 36.72 74.904 ;
    END
  END dq[430]
  PIN dq[431]
    DIRECTION OUTPUT ;
    USE SIGNAL ;
    PORT
      LAYER M4 ;
        RECT  36.528 75.072 36.72 75.096 ;
    END
  END dq[431]
  PIN dq[432]
    DIRECTION OUTPUT ;
    USE SIGNAL ;
    PORT
      LAYER M4 ;
        RECT  36.528 75.216 36.72 75.24 ;
    END
  END dq[432]
  PIN dq[433]
    DIRECTION OUTPUT ;
    USE SIGNAL ;
    PORT
      LAYER M4 ;
        RECT  36.528 75.36 36.72 75.384 ;
    END
  END dq[433]
  PIN dq[434]
    DIRECTION OUTPUT ;
    USE SIGNAL ;
    PORT
      LAYER M4 ;
        RECT  36.528 75.552 36.72 75.576 ;
    END
  END dq[434]
  PIN dq[435]
    DIRECTION OUTPUT ;
    USE SIGNAL ;
    PORT
      LAYER M4 ;
        RECT  36.528 75.696 36.72 75.72 ;
    END
  END dq[435]
  PIN dq[436]
    DIRECTION OUTPUT ;
    USE SIGNAL ;
    PORT
      LAYER M4 ;
        RECT  36.528 75.888 36.72 75.912 ;
    END
  END dq[436]
  PIN dq[437]
    DIRECTION OUTPUT ;
    USE SIGNAL ;
    PORT
      LAYER M4 ;
        RECT  36.528 76.032 36.72 76.056 ;
    END
  END dq[437]
  PIN dq[438]
    DIRECTION OUTPUT ;
    USE SIGNAL ;
    PORT
      LAYER M4 ;
        RECT  36.528 76.176 36.72 76.2 ;
    END
  END dq[438]
  PIN dq[439]
    DIRECTION OUTPUT ;
    USE SIGNAL ;
    PORT
      LAYER M4 ;
        RECT  36.528 76.368 36.72 76.392 ;
    END
  END dq[439]
  PIN dq[43]
    DIRECTION OUTPUT ;
    USE SIGNAL ;
    PORT
      LAYER M4 ;
        RECT  36.528 11.472 36.72 11.496 ;
    END
  END dq[43]
  PIN dq[440]
    DIRECTION OUTPUT ;
    USE SIGNAL ;
    PORT
      LAYER M4 ;
        RECT  36.528 76.512 36.72 76.536 ;
    END
  END dq[440]
  PIN dq[441]
    DIRECTION OUTPUT ;
    USE SIGNAL ;
    PORT
      LAYER M4 ;
        RECT  36.528 76.704 36.72 76.728 ;
    END
  END dq[441]
  PIN dq[442]
    DIRECTION OUTPUT ;
    USE SIGNAL ;
    PORT
      LAYER M4 ;
        RECT  36.528 76.848 36.72 76.872 ;
    END
  END dq[442]
  PIN dq[443]
    DIRECTION OUTPUT ;
    USE SIGNAL ;
    PORT
      LAYER M4 ;
        RECT  36.528 77.04 36.72 77.064 ;
    END
  END dq[443]
  PIN dq[444]
    DIRECTION OUTPUT ;
    USE SIGNAL ;
    PORT
      LAYER M4 ;
        RECT  36.528 77.184 36.72 77.208 ;
    END
  END dq[444]
  PIN dq[445]
    DIRECTION OUTPUT ;
    USE SIGNAL ;
    PORT
      LAYER M4 ;
        RECT  36.528 77.328 36.72 77.352 ;
    END
  END dq[445]
  PIN dq[446]
    DIRECTION OUTPUT ;
    USE SIGNAL ;
    PORT
      LAYER M4 ;
        RECT  36.528 77.52 36.72 77.544 ;
    END
  END dq[446]
  PIN dq[447]
    DIRECTION OUTPUT ;
    USE SIGNAL ;
    PORT
      LAYER M4 ;
        RECT  36.528 77.664 36.72 77.688 ;
    END
  END dq[447]
  PIN dq[448]
    DIRECTION OUTPUT ;
    USE SIGNAL ;
    PORT
      LAYER M4 ;
        RECT  36.528 77.856 36.72 77.88 ;
    END
  END dq[448]
  PIN dq[449]
    DIRECTION OUTPUT ;
    USE SIGNAL ;
    PORT
      LAYER M4 ;
        RECT  36.528 78 36.72 78.024 ;
    END
  END dq[449]
  PIN dq[44]
    DIRECTION OUTPUT ;
    USE SIGNAL ;
    PORT
      LAYER M4 ;
        RECT  36.528 11.616 36.72 11.64 ;
    END
  END dq[44]
  PIN dq[450]
    DIRECTION OUTPUT ;
    USE SIGNAL ;
    PORT
      LAYER M4 ;
        RECT  36.528 78.144 36.72 78.168 ;
    END
  END dq[450]
  PIN dq[451]
    DIRECTION OUTPUT ;
    USE SIGNAL ;
    PORT
      LAYER M4 ;
        RECT  36.528 78.336 36.72 78.36 ;
    END
  END dq[451]
  PIN dq[452]
    DIRECTION OUTPUT ;
    USE SIGNAL ;
    PORT
      LAYER M4 ;
        RECT  36.528 78.48 36.72 78.504 ;
    END
  END dq[452]
  PIN dq[453]
    DIRECTION OUTPUT ;
    USE SIGNAL ;
    PORT
      LAYER M4 ;
        RECT  36.528 78.672 36.72 78.696 ;
    END
  END dq[453]
  PIN dq[454]
    DIRECTION OUTPUT ;
    USE SIGNAL ;
    PORT
      LAYER M4 ;
        RECT  36.528 78.816 36.72 78.84 ;
    END
  END dq[454]
  PIN dq[455]
    DIRECTION OUTPUT ;
    USE SIGNAL ;
    PORT
      LAYER M4 ;
        RECT  36.528 79.008 36.72 79.032 ;
    END
  END dq[455]
  PIN dq[456]
    DIRECTION OUTPUT ;
    USE SIGNAL ;
    PORT
      LAYER M4 ;
        RECT  36.528 79.152 36.72 79.176 ;
    END
  END dq[456]
  PIN dq[457]
    DIRECTION OUTPUT ;
    USE SIGNAL ;
    PORT
      LAYER M4 ;
        RECT  36.528 79.296 36.72 79.32 ;
    END
  END dq[457]
  PIN dq[458]
    DIRECTION OUTPUT ;
    USE SIGNAL ;
    PORT
      LAYER M4 ;
        RECT  36.528 79.488 36.72 79.512 ;
    END
  END dq[458]
  PIN dq[459]
    DIRECTION OUTPUT ;
    USE SIGNAL ;
    PORT
      LAYER M4 ;
        RECT  36.528 79.632 36.72 79.656 ;
    END
  END dq[459]
  PIN dq[45]
    DIRECTION OUTPUT ;
    USE SIGNAL ;
    PORT
      LAYER M4 ;
        RECT  36.528 11.808 36.72 11.832 ;
    END
  END dq[45]
  PIN dq[460]
    DIRECTION OUTPUT ;
    USE SIGNAL ;
    PORT
      LAYER M4 ;
        RECT  36.528 79.824 36.72 79.848 ;
    END
  END dq[460]
  PIN dq[461]
    DIRECTION OUTPUT ;
    USE SIGNAL ;
    PORT
      LAYER M4 ;
        RECT  36.528 79.968 36.72 79.992 ;
    END
  END dq[461]
  PIN dq[462]
    DIRECTION OUTPUT ;
    USE SIGNAL ;
    PORT
      LAYER M4 ;
        RECT  36.528 80.112 36.72 80.136 ;
    END
  END dq[462]
  PIN dq[463]
    DIRECTION OUTPUT ;
    USE SIGNAL ;
    PORT
      LAYER M4 ;
        RECT  36.528 80.304 36.72 80.328 ;
    END
  END dq[463]
  PIN dq[464]
    DIRECTION OUTPUT ;
    USE SIGNAL ;
    PORT
      LAYER M4 ;
        RECT  36.528 80.448 36.72 80.472 ;
    END
  END dq[464]
  PIN dq[465]
    DIRECTION OUTPUT ;
    USE SIGNAL ;
    PORT
      LAYER M4 ;
        RECT  36.528 80.64 36.72 80.664 ;
    END
  END dq[465]
  PIN dq[466]
    DIRECTION OUTPUT ;
    USE SIGNAL ;
    PORT
      LAYER M4 ;
        RECT  36.528 80.784 36.72 80.808 ;
    END
  END dq[466]
  PIN dq[467]
    DIRECTION OUTPUT ;
    USE SIGNAL ;
    PORT
      LAYER M4 ;
        RECT  36.528 80.928 36.72 80.952 ;
    END
  END dq[467]
  PIN dq[468]
    DIRECTION OUTPUT ;
    USE SIGNAL ;
    PORT
      LAYER M4 ;
        RECT  36.528 81.12 36.72 81.144 ;
    END
  END dq[468]
  PIN dq[469]
    DIRECTION OUTPUT ;
    USE SIGNAL ;
    PORT
      LAYER M4 ;
        RECT  36.528 81.264 36.72 81.288 ;
    END
  END dq[469]
  PIN dq[46]
    DIRECTION OUTPUT ;
    USE SIGNAL ;
    PORT
      LAYER M4 ;
        RECT  36.528 11.952 36.72 11.976 ;
    END
  END dq[46]
  PIN dq[470]
    DIRECTION OUTPUT ;
    USE SIGNAL ;
    PORT
      LAYER M4 ;
        RECT  36.528 81.456 36.72 81.48 ;
    END
  END dq[470]
  PIN dq[471]
    DIRECTION OUTPUT ;
    USE SIGNAL ;
    PORT
      LAYER M4 ;
        RECT  36.528 81.6 36.72 81.624 ;
    END
  END dq[471]
  PIN dq[472]
    DIRECTION OUTPUT ;
    USE SIGNAL ;
    PORT
      LAYER M4 ;
        RECT  36.528 81.792 36.72 81.816 ;
    END
  END dq[472]
  PIN dq[473]
    DIRECTION OUTPUT ;
    USE SIGNAL ;
    PORT
      LAYER M4 ;
        RECT  36.528 81.936 36.72 81.96 ;
    END
  END dq[473]
  PIN dq[474]
    DIRECTION OUTPUT ;
    USE SIGNAL ;
    PORT
      LAYER M4 ;
        RECT  36.528 82.08 36.72 82.104 ;
    END
  END dq[474]
  PIN dq[475]
    DIRECTION OUTPUT ;
    USE SIGNAL ;
    PORT
      LAYER M4 ;
        RECT  36.528 82.272 36.72 82.296 ;
    END
  END dq[475]
  PIN dq[476]
    DIRECTION OUTPUT ;
    USE SIGNAL ;
    PORT
      LAYER M4 ;
        RECT  36.528 82.416 36.72 82.44 ;
    END
  END dq[476]
  PIN dq[477]
    DIRECTION OUTPUT ;
    USE SIGNAL ;
    PORT
      LAYER M4 ;
        RECT  36.528 82.608 36.72 82.632 ;
    END
  END dq[477]
  PIN dq[478]
    DIRECTION OUTPUT ;
    USE SIGNAL ;
    PORT
      LAYER M4 ;
        RECT  36.528 82.752 36.72 82.776 ;
    END
  END dq[478]
  PIN dq[479]
    DIRECTION OUTPUT ;
    USE SIGNAL ;
    PORT
      LAYER M4 ;
        RECT  36.528 82.896 36.72 82.92 ;
    END
  END dq[479]
  PIN dq[47]
    DIRECTION OUTPUT ;
    USE SIGNAL ;
    PORT
      LAYER M4 ;
        RECT  36.528 12.096 36.72 12.12 ;
    END
  END dq[47]
  PIN dq[480]
    DIRECTION OUTPUT ;
    USE SIGNAL ;
    PORT
      LAYER M4 ;
        RECT  36.528 83.088 36.72 83.112 ;
    END
  END dq[480]
  PIN dq[481]
    DIRECTION OUTPUT ;
    USE SIGNAL ;
    PORT
      LAYER M4 ;
        RECT  36.528 83.232 36.72 83.256 ;
    END
  END dq[481]
  PIN dq[482]
    DIRECTION OUTPUT ;
    USE SIGNAL ;
    PORT
      LAYER M4 ;
        RECT  36.528 83.424 36.72 83.448 ;
    END
  END dq[482]
  PIN dq[483]
    DIRECTION OUTPUT ;
    USE SIGNAL ;
    PORT
      LAYER M4 ;
        RECT  36.528 83.568 36.72 83.592 ;
    END
  END dq[483]
  PIN dq[484]
    DIRECTION OUTPUT ;
    USE SIGNAL ;
    PORT
      LAYER M4 ;
        RECT  36.528 83.76 36.72 83.784 ;
    END
  END dq[484]
  PIN dq[485]
    DIRECTION OUTPUT ;
    USE SIGNAL ;
    PORT
      LAYER M4 ;
        RECT  36.528 83.904 36.72 83.928 ;
    END
  END dq[485]
  PIN dq[486]
    DIRECTION OUTPUT ;
    USE SIGNAL ;
    PORT
      LAYER M4 ;
        RECT  36.528 84.048 36.72 84.072 ;
    END
  END dq[486]
  PIN dq[487]
    DIRECTION OUTPUT ;
    USE SIGNAL ;
    PORT
      LAYER M4 ;
        RECT  36.528 84.24 36.72 84.264 ;
    END
  END dq[487]
  PIN dq[488]
    DIRECTION OUTPUT ;
    USE SIGNAL ;
    PORT
      LAYER M4 ;
        RECT  36.528 84.384 36.72 84.408 ;
    END
  END dq[488]
  PIN dq[489]
    DIRECTION OUTPUT ;
    USE SIGNAL ;
    PORT
      LAYER M4 ;
        RECT  36.528 84.576 36.72 84.6 ;
    END
  END dq[489]
  PIN dq[48]
    DIRECTION OUTPUT ;
    USE SIGNAL ;
    PORT
      LAYER M4 ;
        RECT  36.528 12.288 36.72 12.312 ;
    END
  END dq[48]
  PIN dq[490]
    DIRECTION OUTPUT ;
    USE SIGNAL ;
    PORT
      LAYER M4 ;
        RECT  36.528 84.72 36.72 84.744 ;
    END
  END dq[490]
  PIN dq[491]
    DIRECTION OUTPUT ;
    USE SIGNAL ;
    PORT
      LAYER M4 ;
        RECT  36.528 84.864 36.72 84.888 ;
    END
  END dq[491]
  PIN dq[492]
    DIRECTION OUTPUT ;
    USE SIGNAL ;
    PORT
      LAYER M4 ;
        RECT  36.528 85.056 36.72 85.08 ;
    END
  END dq[492]
  PIN dq[493]
    DIRECTION OUTPUT ;
    USE SIGNAL ;
    PORT
      LAYER M4 ;
        RECT  36.528 85.2 36.72 85.224 ;
    END
  END dq[493]
  PIN dq[494]
    DIRECTION OUTPUT ;
    USE SIGNAL ;
    PORT
      LAYER M4 ;
        RECT  36.528 85.392 36.72 85.416 ;
    END
  END dq[494]
  PIN dq[495]
    DIRECTION OUTPUT ;
    USE SIGNAL ;
    PORT
      LAYER M4 ;
        RECT  36.528 85.536 36.72 85.56 ;
    END
  END dq[495]
  PIN dq[496]
    DIRECTION OUTPUT ;
    USE SIGNAL ;
    PORT
      LAYER M4 ;
        RECT  36.528 85.68 36.72 85.704 ;
    END
  END dq[496]
  PIN dq[497]
    DIRECTION OUTPUT ;
    USE SIGNAL ;
    PORT
      LAYER M4 ;
        RECT  36.528 85.872 36.72 85.896 ;
    END
  END dq[497]
  PIN dq[498]
    DIRECTION OUTPUT ;
    USE SIGNAL ;
    PORT
      LAYER M4 ;
        RECT  36.528 86.016 36.72 86.04 ;
    END
  END dq[498]
  PIN dq[499]
    DIRECTION OUTPUT ;
    USE SIGNAL ;
    PORT
      LAYER M4 ;
        RECT  36.528 86.208 36.72 86.232 ;
    END
  END dq[499]
  PIN dq[49]
    DIRECTION OUTPUT ;
    USE SIGNAL ;
    PORT
      LAYER M4 ;
        RECT  36.528 12.432 36.72 12.456 ;
    END
  END dq[49]
  PIN dq[4]
    DIRECTION OUTPUT ;
    USE SIGNAL ;
    PORT
      LAYER M4 ;
        RECT  36.528 5.088 36.72 5.112 ;
    END
  END dq[4]
  PIN dq[500]
    DIRECTION OUTPUT ;
    USE SIGNAL ;
    PORT
      LAYER M4 ;
        RECT  36.528 86.352 36.72 86.376 ;
    END
  END dq[500]
  PIN dq[501]
    DIRECTION OUTPUT ;
    USE SIGNAL ;
    PORT
      LAYER M4 ;
        RECT  36.528 86.544 36.72 86.568 ;
    END
  END dq[501]
  PIN dq[502]
    DIRECTION OUTPUT ;
    USE SIGNAL ;
    PORT
      LAYER M4 ;
        RECT  36.528 86.688 36.72 86.712 ;
    END
  END dq[502]
  PIN dq[503]
    DIRECTION OUTPUT ;
    USE SIGNAL ;
    PORT
      LAYER M4 ;
        RECT  36.528 86.832 36.72 86.856 ;
    END
  END dq[503]
  PIN dq[504]
    DIRECTION OUTPUT ;
    USE SIGNAL ;
    PORT
      LAYER M4 ;
        RECT  36.528 87.024 36.72 87.048 ;
    END
  END dq[504]
  PIN dq[505]
    DIRECTION OUTPUT ;
    USE SIGNAL ;
    PORT
      LAYER M4 ;
        RECT  36.528 87.168 36.72 87.192 ;
    END
  END dq[505]
  PIN dq[506]
    DIRECTION OUTPUT ;
    USE SIGNAL ;
    PORT
      LAYER M4 ;
        RECT  36.528 87.36 36.72 87.384 ;
    END
  END dq[506]
  PIN dq[507]
    DIRECTION OUTPUT ;
    USE SIGNAL ;
    PORT
      LAYER M4 ;
        RECT  36.528 87.504 36.72 87.528 ;
    END
  END dq[507]
  PIN dq[508]
    DIRECTION OUTPUT ;
    USE SIGNAL ;
    PORT
      LAYER M4 ;
        RECT  36.528 87.648 36.72 87.672 ;
    END
  END dq[508]
  PIN dq[509]
    DIRECTION OUTPUT ;
    USE SIGNAL ;
    PORT
      LAYER M4 ;
        RECT  36.528 87.84 36.72 87.864 ;
    END
  END dq[509]
  PIN dq[50]
    DIRECTION OUTPUT ;
    USE SIGNAL ;
    PORT
      LAYER M4 ;
        RECT  36.528 12.624 36.72 12.648 ;
    END
  END dq[50]
  PIN dq[510]
    DIRECTION OUTPUT ;
    USE SIGNAL ;
    PORT
      LAYER M4 ;
        RECT  36.528 87.984 36.72 88.008 ;
    END
  END dq[510]
  PIN dq[511]
    DIRECTION OUTPUT ;
    USE SIGNAL ;
    PORT
      LAYER M4 ;
        RECT  36.528 88.176 36.72 88.2 ;
    END
  END dq[511]
  PIN dq[512]
    DIRECTION OUTPUT ;
    USE SIGNAL ;
    PORT
      LAYER M4 ;
        RECT  36.528 88.32 36.72 88.344 ;
    END
  END dq[512]
  PIN dq[513]
    DIRECTION OUTPUT ;
    USE SIGNAL ;
    PORT
      LAYER M4 ;
        RECT  36.528 88.512 36.72 88.536 ;
    END
  END dq[513]
  PIN dq[51]
    DIRECTION OUTPUT ;
    USE SIGNAL ;
    PORT
      LAYER M4 ;
        RECT  36.528 12.768 36.72 12.792 ;
    END
  END dq[51]
  PIN dq[52]
    DIRECTION OUTPUT ;
    USE SIGNAL ;
    PORT
      LAYER M4 ;
        RECT  36.528 12.96 36.72 12.984 ;
    END
  END dq[52]
  PIN dq[53]
    DIRECTION OUTPUT ;
    USE SIGNAL ;
    PORT
      LAYER M4 ;
        RECT  36.528 13.104 36.72 13.128 ;
    END
  END dq[53]
  PIN dq[54]
    DIRECTION OUTPUT ;
    USE SIGNAL ;
    PORT
      LAYER M4 ;
        RECT  36.528 13.248 36.72 13.272 ;
    END
  END dq[54]
  PIN dq[55]
    DIRECTION OUTPUT ;
    USE SIGNAL ;
    PORT
      LAYER M4 ;
        RECT  36.528 13.44 36.72 13.464 ;
    END
  END dq[55]
  PIN dq[56]
    DIRECTION OUTPUT ;
    USE SIGNAL ;
    PORT
      LAYER M4 ;
        RECT  36.528 13.584 36.72 13.608 ;
    END
  END dq[56]
  PIN dq[57]
    DIRECTION OUTPUT ;
    USE SIGNAL ;
    PORT
      LAYER M4 ;
        RECT  36.528 13.776 36.72 13.8 ;
    END
  END dq[57]
  PIN dq[58]
    DIRECTION OUTPUT ;
    USE SIGNAL ;
    PORT
      LAYER M4 ;
        RECT  36.528 13.92 36.72 13.944 ;
    END
  END dq[58]
  PIN dq[59]
    DIRECTION OUTPUT ;
    USE SIGNAL ;
    PORT
      LAYER M4 ;
        RECT  36.528 14.064 36.72 14.088 ;
    END
  END dq[59]
  PIN dq[5]
    DIRECTION OUTPUT ;
    USE SIGNAL ;
    PORT
      LAYER M4 ;
        RECT  36.528 5.232 36.72 5.256 ;
    END
  END dq[5]
  PIN dq[60]
    DIRECTION OUTPUT ;
    USE SIGNAL ;
    PORT
      LAYER M4 ;
        RECT  36.528 14.256 36.72 14.28 ;
    END
  END dq[60]
  PIN dq[61]
    DIRECTION OUTPUT ;
    USE SIGNAL ;
    PORT
      LAYER M4 ;
        RECT  36.528 14.4 36.72 14.424 ;
    END
  END dq[61]
  PIN dq[62]
    DIRECTION OUTPUT ;
    USE SIGNAL ;
    PORT
      LAYER M4 ;
        RECT  36.528 14.592 36.72 14.616 ;
    END
  END dq[62]
  PIN dq[63]
    DIRECTION OUTPUT ;
    USE SIGNAL ;
    PORT
      LAYER M4 ;
        RECT  36.528 14.736 36.72 14.76 ;
    END
  END dq[63]
  PIN dq[64]
    DIRECTION OUTPUT ;
    USE SIGNAL ;
    PORT
      LAYER M4 ;
        RECT  36.528 14.88 36.72 14.904 ;
    END
  END dq[64]
  PIN dq[65]
    DIRECTION OUTPUT ;
    USE SIGNAL ;
    PORT
      LAYER M4 ;
        RECT  36.528 15.072 36.72 15.096 ;
    END
  END dq[65]
  PIN dq[66]
    DIRECTION OUTPUT ;
    USE SIGNAL ;
    PORT
      LAYER M4 ;
        RECT  36.528 15.216 36.72 15.24 ;
    END
  END dq[66]
  PIN dq[67]
    DIRECTION OUTPUT ;
    USE SIGNAL ;
    PORT
      LAYER M4 ;
        RECT  36.528 15.408 36.72 15.432 ;
    END
  END dq[67]
  PIN dq[68]
    DIRECTION OUTPUT ;
    USE SIGNAL ;
    PORT
      LAYER M4 ;
        RECT  36.528 15.552 36.72 15.576 ;
    END
  END dq[68]
  PIN dq[69]
    DIRECTION OUTPUT ;
    USE SIGNAL ;
    PORT
      LAYER M4 ;
        RECT  36.528 15.744 36.72 15.768 ;
    END
  END dq[69]
  PIN dq[6]
    DIRECTION OUTPUT ;
    USE SIGNAL ;
    PORT
      LAYER M4 ;
        RECT  36.528 5.376 36.72 5.4 ;
    END
  END dq[6]
  PIN dq[70]
    DIRECTION OUTPUT ;
    USE SIGNAL ;
    PORT
      LAYER M4 ;
        RECT  36.528 15.888 36.72 15.912 ;
    END
  END dq[70]
  PIN dq[71]
    DIRECTION OUTPUT ;
    USE SIGNAL ;
    PORT
      LAYER M4 ;
        RECT  36.528 16.032 36.72 16.056 ;
    END
  END dq[71]
  PIN dq[72]
    DIRECTION OUTPUT ;
    USE SIGNAL ;
    PORT
      LAYER M4 ;
        RECT  36.528 16.224 36.72 16.248 ;
    END
  END dq[72]
  PIN dq[73]
    DIRECTION OUTPUT ;
    USE SIGNAL ;
    PORT
      LAYER M4 ;
        RECT  36.528 16.368 36.72 16.392 ;
    END
  END dq[73]
  PIN dq[74]
    DIRECTION OUTPUT ;
    USE SIGNAL ;
    PORT
      LAYER M4 ;
        RECT  36.528 16.56 36.72 16.584 ;
    END
  END dq[74]
  PIN dq[75]
    DIRECTION OUTPUT ;
    USE SIGNAL ;
    PORT
      LAYER M4 ;
        RECT  36.528 16.704 36.72 16.728 ;
    END
  END dq[75]
  PIN dq[76]
    DIRECTION OUTPUT ;
    USE SIGNAL ;
    PORT
      LAYER M4 ;
        RECT  36.528 16.848 36.72 16.872 ;
    END
  END dq[76]
  PIN dq[77]
    DIRECTION OUTPUT ;
    USE SIGNAL ;
    PORT
      LAYER M4 ;
        RECT  36.528 17.04 36.72 17.064 ;
    END
  END dq[77]
  PIN dq[78]
    DIRECTION OUTPUT ;
    USE SIGNAL ;
    PORT
      LAYER M4 ;
        RECT  36.528 17.184 36.72 17.208 ;
    END
  END dq[78]
  PIN dq[79]
    DIRECTION OUTPUT ;
    USE SIGNAL ;
    PORT
      LAYER M4 ;
        RECT  36.528 17.376 36.72 17.4 ;
    END
  END dq[79]
  PIN dq[7]
    DIRECTION OUTPUT ;
    USE SIGNAL ;
    PORT
      LAYER M4 ;
        RECT  36.528 5.568 36.72 5.592 ;
    END
  END dq[7]
  PIN dq[80]
    DIRECTION OUTPUT ;
    USE SIGNAL ;
    PORT
      LAYER M4 ;
        RECT  36.528 17.52 36.72 17.544 ;
    END
  END dq[80]
  PIN dq[81]
    DIRECTION OUTPUT ;
    USE SIGNAL ;
    PORT
      LAYER M4 ;
        RECT  36.528 17.712 36.72 17.736 ;
    END
  END dq[81]
  PIN dq[82]
    DIRECTION OUTPUT ;
    USE SIGNAL ;
    PORT
      LAYER M4 ;
        RECT  36.528 17.856 36.72 17.88 ;
    END
  END dq[82]
  PIN dq[83]
    DIRECTION OUTPUT ;
    USE SIGNAL ;
    PORT
      LAYER M4 ;
        RECT  36.528 18 36.72 18.024 ;
    END
  END dq[83]
  PIN dq[84]
    DIRECTION OUTPUT ;
    USE SIGNAL ;
    PORT
      LAYER M4 ;
        RECT  36.528 18.192 36.72 18.216 ;
    END
  END dq[84]
  PIN dq[85]
    DIRECTION OUTPUT ;
    USE SIGNAL ;
    PORT
      LAYER M4 ;
        RECT  36.528 18.336 36.72 18.36 ;
    END
  END dq[85]
  PIN dq[86]
    DIRECTION OUTPUT ;
    USE SIGNAL ;
    PORT
      LAYER M4 ;
        RECT  36.528 18.528 36.72 18.552 ;
    END
  END dq[86]
  PIN dq[87]
    DIRECTION OUTPUT ;
    USE SIGNAL ;
    PORT
      LAYER M4 ;
        RECT  36.528 18.672 36.72 18.696 ;
    END
  END dq[87]
  PIN dq[88]
    DIRECTION OUTPUT ;
    USE SIGNAL ;
    PORT
      LAYER M4 ;
        RECT  36.528 18.816 36.72 18.84 ;
    END
  END dq[88]
  PIN dq[89]
    DIRECTION OUTPUT ;
    USE SIGNAL ;
    PORT
      LAYER M4 ;
        RECT  36.528 19.008 36.72 19.032 ;
    END
  END dq[89]
  PIN dq[8]
    DIRECTION OUTPUT ;
    USE SIGNAL ;
    PORT
      LAYER M4 ;
        RECT  36.528 5.712 36.72 5.736 ;
    END
  END dq[8]
  PIN dq[90]
    DIRECTION OUTPUT ;
    USE SIGNAL ;
    PORT
      LAYER M4 ;
        RECT  36.528 19.152 36.72 19.176 ;
    END
  END dq[90]
  PIN dq[91]
    DIRECTION OUTPUT ;
    USE SIGNAL ;
    PORT
      LAYER M4 ;
        RECT  36.528 19.344 36.72 19.368 ;
    END
  END dq[91]
  PIN dq[92]
    DIRECTION OUTPUT ;
    USE SIGNAL ;
    PORT
      LAYER M4 ;
        RECT  36.528 19.488 36.72 19.512 ;
    END
  END dq[92]
  PIN dq[93]
    DIRECTION OUTPUT ;
    USE SIGNAL ;
    PORT
      LAYER M4 ;
        RECT  36.528 19.632 36.72 19.656 ;
    END
  END dq[93]
  PIN dq[94]
    DIRECTION OUTPUT ;
    USE SIGNAL ;
    PORT
      LAYER M4 ;
        RECT  36.528 19.824 36.72 19.848 ;
    END
  END dq[94]
  PIN dq[95]
    DIRECTION OUTPUT ;
    USE SIGNAL ;
    PORT
      LAYER M4 ;
        RECT  36.528 19.968 36.72 19.992 ;
    END
  END dq[95]
  PIN dq[96]
    DIRECTION OUTPUT ;
    USE SIGNAL ;
    PORT
      LAYER M4 ;
        RECT  36.528 20.16 36.72 20.184 ;
    END
  END dq[96]
  PIN dq[97]
    DIRECTION OUTPUT ;
    USE SIGNAL ;
    PORT
      LAYER M4 ;
        RECT  36.528 20.304 36.72 20.328 ;
    END
  END dq[97]
  PIN dq[98]
    DIRECTION OUTPUT ;
    USE SIGNAL ;
    PORT
      LAYER M4 ;
        RECT  36.528 20.496 36.72 20.52 ;
    END
  END dq[98]
  PIN dq[99]
    DIRECTION OUTPUT ;
    USE SIGNAL ;
    PORT
      LAYER M4 ;
        RECT  36.528 20.64 36.72 20.664 ;
    END
  END dq[99]
  PIN dq[9]
    DIRECTION OUTPUT ;
    USE SIGNAL ;
    PORT
      LAYER M4 ;
        RECT  36.528 5.904 36.72 5.928 ;
    END
  END dq[9]
  PIN VDD
    DIRECTION INOUT ;
    USE POWER ;
    PORT
      LAYER M5 ;
        RECT  32.292 2.151 32.412 90.729 ;
        RECT  29.592 2.151 29.712 90.729 ;
        RECT  26.892 2.151 27.012 90.729 ;
        RECT  24.192 2.151 24.312 90.729 ;
        RECT  21.492 2.151 21.612 90.729 ;
        RECT  18.792 2.151 18.912 90.729 ;
        RECT  16.092 2.151 16.212 90.729 ;
        RECT  13.392 2.151 13.512 90.729 ;
        RECT  10.692 2.151 10.812 90.729 ;
        RECT  7.992 2.151 8.112 90.729 ;
        RECT  5.292 2.151 5.412 90.729 ;
        RECT  2.592 2.151 2.712 90.729 ;
    END
  END VDD
  PIN VSS
    DIRECTION INOUT ;
    USE GROUND ;
    PORT
      LAYER M5 ;
        RECT  32.1 2.137 32.22 90.743 ;
        RECT  29.4 2.137 29.52 90.743 ;
        RECT  26.7 2.137 26.82 90.743 ;
        RECT  24 2.137 24.12 90.743 ;
        RECT  21.3 2.137 21.42 90.743 ;
        RECT  18.6 2.137 18.72 90.743 ;
        RECT  15.9 2.137 16.02 90.743 ;
        RECT  13.2 2.137 13.32 90.743 ;
        RECT  10.5 2.137 10.62 90.743 ;
        RECT  7.8 2.137 7.92 90.743 ;
        RECT  5.1 2.137 5.22 90.743 ;
        RECT  2.4 2.137 2.52 90.743 ;
    END
  END VSS
  # OT_OBS_CLOSED layer=M5 d_um=1.536 added=98
  OBS
    LAYER RVTN ;
     RECT  2.16 2.16 34.56 2.295 ;
     RECT  2.16 2.565 34.56 2.835 ;
     RECT  2.16 3.105 34.56 3.375 ;
     RECT  2.16 3.645 34.56 3.915 ;
     RECT  2.16 4.185 34.56 4.455 ;
     RECT  2.16 4.725 34.56 4.995 ;
     RECT  2.16 5.265 34.56 5.535 ;
     RECT  2.16 5.805 34.56 6.075 ;
     RECT  2.16 6.345 34.56 6.615 ;
     RECT  2.16 6.885 34.56 7.155 ;
     RECT  2.16 7.425 34.56 7.695 ;
     RECT  2.16 7.965 34.56 8.235 ;
     RECT  2.16 8.505 34.56 8.775 ;
     RECT  2.16 9.045 34.56 9.315 ;
     RECT  2.16 9.585 34.56 9.855 ;
     RECT  2.16 10.125 34.56 10.395 ;
     RECT  2.16 10.665 34.56 10.935 ;
     RECT  2.16 11.205 34.56 11.475 ;
     RECT  2.16 11.745 34.56 12.015 ;
     RECT  2.16 12.285 34.56 12.555 ;
     RECT  2.16 12.825 34.56 13.095 ;
     RECT  2.16 13.365 34.56 13.635 ;
     RECT  2.16 13.905 34.56 14.175 ;
     RECT  2.16 14.445 34.56 14.715 ;
     RECT  2.16 14.985 34.56 15.255 ;
     RECT  2.16 15.525 34.56 15.795 ;
     RECT  2.16 16.065 34.56 16.335 ;
     RECT  2.16 16.605 34.56 16.875 ;
     RECT  2.16 17.145 34.56 17.415 ;
     RECT  2.16 17.685 34.56 17.955 ;
     RECT  2.16 18.225 34.56 18.495 ;
     RECT  2.16 18.765 34.56 19.035 ;
     RECT  2.16 19.305 34.56 19.575 ;
     RECT  2.16 19.845 34.56 20.115 ;
     RECT  2.16 20.385 34.56 20.655 ;
     RECT  2.16 20.925 34.56 21.195 ;
     RECT  2.16 21.465 34.56 21.735 ;
     RECT  2.16 22.005 34.56 22.275 ;
     RECT  2.16 22.545 34.56 22.815 ;
     RECT  2.16 23.085 34.56 23.355 ;
     RECT  2.16 23.625 34.56 23.895 ;
     RECT  2.16 24.165 34.56 24.435 ;
     RECT  2.16 24.705 34.56 24.975 ;
     RECT  2.16 25.245 34.56 25.515 ;
     RECT  2.16 25.785 34.56 26.055 ;
     RECT  2.16 26.325 34.56 26.595 ;
     RECT  2.16 26.865 34.56 27.135 ;
     RECT  2.16 27.405 34.56 27.675 ;
     RECT  2.16 27.945 34.56 28.215 ;
     RECT  2.16 28.485 34.56 28.755 ;
     RECT  2.16 29.025 34.56 29.295 ;
     RECT  2.16 29.565 34.56 29.835 ;
     RECT  2.16 30.105 34.56 30.375 ;
     RECT  2.16 30.645 34.56 30.915 ;
     RECT  2.16 31.185 34.56 31.455 ;
     RECT  2.16 31.725 34.56 31.995 ;
     RECT  2.16 32.265 34.56 32.535 ;
     RECT  2.16 32.805 34.56 33.075 ;
     RECT  2.16 33.345 34.56 33.615 ;
     RECT  2.16 33.885 34.56 34.155 ;
     RECT  2.16 34.425 34.56 34.695 ;
     RECT  2.16 34.965 34.56 35.235 ;
     RECT  2.16 35.505 34.56 35.775 ;
     RECT  2.16 36.045 34.56 36.315 ;
     RECT  2.16 36.585 34.56 36.855 ;
     RECT  2.16 37.125 34.56 37.395 ;
     RECT  2.16 37.665 34.56 37.935 ;
     RECT  2.16 38.205 34.56 38.475 ;
     RECT  2.16 38.745 34.56 39.015 ;
     RECT  2.16 39.285 34.56 39.555 ;
     RECT  2.16 39.825 34.56 40.095 ;
     RECT  2.16 40.365 34.56 40.635 ;
     RECT  2.16 40.905 34.56 41.175 ;
     RECT  2.16 41.445 34.56 41.715 ;
     RECT  2.16 41.985 34.56 42.255 ;
     RECT  2.16 42.525 34.56 42.795 ;
     RECT  2.16 43.065 34.56 43.335 ;
     RECT  2.16 43.605 34.56 43.875 ;
     RECT  2.16 44.145 34.56 44.415 ;
     RECT  2.16 44.685 34.56 44.955 ;
     RECT  2.16 45.225 34.56 45.495 ;
     RECT  2.16 45.765 34.56 46.035 ;
     RECT  2.16 46.305 34.56 46.575 ;
     RECT  2.16 46.845 34.56 47.115 ;
     RECT  2.16 47.385 34.56 47.655 ;
     RECT  2.16 47.925 34.56 48.195 ;
     RECT  2.16 48.465 34.56 48.735 ;
     RECT  2.16 49.005 34.56 49.275 ;
     RECT  2.16 49.545 34.56 49.815 ;
     RECT  2.16 50.085 34.56 50.355 ;
     RECT  2.16 50.625 34.56 50.895 ;
     RECT  2.16 51.165 34.56 51.435 ;
     RECT  2.16 51.705 34.56 51.975 ;
     RECT  2.16 52.245 34.56 52.515 ;
     RECT  2.16 52.785 34.56 53.055 ;
     RECT  2.16 53.325 34.56 53.595 ;
     RECT  2.16 53.865 34.56 54.135 ;
     RECT  2.16 54.405 34.56 54.675 ;
     RECT  2.16 54.945 34.56 55.215 ;
     RECT  2.16 55.485 34.56 55.755 ;
     RECT  2.16 56.025 34.56 56.295 ;
     RECT  2.16 56.565 34.56 56.835 ;
     RECT  2.16 57.105 34.56 57.375 ;
     RECT  2.16 57.645 34.56 57.915 ;
     RECT  2.16 58.185 34.56 58.455 ;
     RECT  2.16 58.725 34.56 58.995 ;
     RECT  2.16 59.265 34.56 59.535 ;
     RECT  2.16 59.805 34.56 60.075 ;
     RECT  2.16 60.345 34.56 60.615 ;
     RECT  2.16 60.885 34.56 61.155 ;
     RECT  2.16 61.425 34.56 61.695 ;
     RECT  2.16 61.965 34.56 62.235 ;
     RECT  2.16 62.505 34.56 62.775 ;
     RECT  2.16 63.045 34.56 63.315 ;
     RECT  2.16 63.585 34.56 63.855 ;
     RECT  2.16 64.125 34.56 64.395 ;
     RECT  2.16 64.665 34.56 64.935 ;
     RECT  2.16 65.205 34.56 65.475 ;
     RECT  2.16 65.745 34.56 66.015 ;
     RECT  2.16 66.285 34.56 66.555 ;
     RECT  2.16 66.825 34.56 67.095 ;
     RECT  2.16 67.365 34.56 67.635 ;
     RECT  2.16 67.905 34.56 68.175 ;
     RECT  2.16 68.445 34.56 68.715 ;
     RECT  2.16 68.985 34.56 69.255 ;
     RECT  2.16 69.525 34.56 69.795 ;
     RECT  2.16 70.065 34.56 70.335 ;
     RECT  2.16 70.605 34.56 70.875 ;
     RECT  2.16 71.145 34.56 71.415 ;
     RECT  2.16 71.685 34.56 71.955 ;
     RECT  2.16 72.225 34.56 72.495 ;
     RECT  2.16 72.765 34.56 73.035 ;
     RECT  2.16 73.305 34.56 73.575 ;
     RECT  2.16 73.845 34.56 74.115 ;
     RECT  2.16 74.385 34.56 74.655 ;
     RECT  2.16 74.925 34.56 75.195 ;
     RECT  2.16 75.465 34.56 75.735 ;
     RECT  2.16 76.005 34.56 76.275 ;
     RECT  2.16 76.545 34.56 76.815 ;
     RECT  2.16 77.085 34.56 77.355 ;
     RECT  2.16 77.625 34.56 77.895 ;
     RECT  2.16 78.165 34.56 78.435 ;
     RECT  2.16 78.705 34.56 78.975 ;
     RECT  2.16 79.245 34.56 79.515 ;
     RECT  2.16 79.785 34.56 80.055 ;
     RECT  2.16 80.325 34.56 80.595 ;
     RECT  2.16 80.865 34.56 81.135 ;
     RECT  2.16 81.405 34.56 81.675 ;
     RECT  2.16 81.945 34.56 82.215 ;
     RECT  2.16 82.485 34.56 82.755 ;
     RECT  2.16 83.025 34.56 83.295 ;
     RECT  2.16 83.565 34.56 83.835 ;
     RECT  2.16 84.105 34.56 84.375 ;
     RECT  2.16 84.645 34.56 84.915 ;
     RECT  2.16 85.185 34.56 85.455 ;
     RECT  2.16 85.725 34.56 85.995 ;
     RECT  2.16 86.265 34.56 86.535 ;
     RECT  2.16 86.805 34.56 87.075 ;
     RECT  2.16 87.345 34.56 87.615 ;
     RECT  2.16 87.885 34.56 88.155 ;
     RECT  2.16 88.425 34.56 88.695 ;
     RECT  2.16 88.965 34.56 89.235 ;
     RECT  2.16 89.505 34.56 89.775 ;
     RECT  2.16 90.045 34.56 90.315 ;
     RECT  2.16 90.585 34.56 90.72 ;
    LAYER RVTP ;
     RECT  2.16 2.295 34.56 2.565 ;
     RECT  2.16 2.835 34.56 3.105 ;
     RECT  2.16 3.375 34.56 3.645 ;
     RECT  2.16 3.915 34.56 4.185 ;
     RECT  2.16 4.455 34.56 4.725 ;
     RECT  2.16 4.995 34.56 5.265 ;
     RECT  2.16 5.535 34.56 5.805 ;
     RECT  2.16 6.075 34.56 6.345 ;
     RECT  2.16 6.615 34.56 6.885 ;
     RECT  2.16 7.155 34.56 7.425 ;
     RECT  2.16 7.695 34.56 7.965 ;
     RECT  2.16 8.235 34.56 8.505 ;
     RECT  2.16 8.775 34.56 9.045 ;
     RECT  2.16 9.315 34.56 9.585 ;
     RECT  2.16 9.855 34.56 10.125 ;
     RECT  2.16 10.395 34.56 10.665 ;
     RECT  2.16 10.935 34.56 11.205 ;
     RECT  2.16 11.475 34.56 11.745 ;
     RECT  2.16 12.015 34.56 12.285 ;
     RECT  2.16 12.555 34.56 12.825 ;
     RECT  2.16 13.095 34.56 13.365 ;
     RECT  2.16 13.635 34.56 13.905 ;
     RECT  2.16 14.175 34.56 14.445 ;
     RECT  2.16 14.715 34.56 14.985 ;
     RECT  2.16 15.255 34.56 15.525 ;
     RECT  2.16 15.795 34.56 16.065 ;
     RECT  2.16 16.335 34.56 16.605 ;
     RECT  2.16 16.875 34.56 17.145 ;
     RECT  2.16 17.415 34.56 17.685 ;
     RECT  2.16 17.955 34.56 18.225 ;
     RECT  2.16 18.495 34.56 18.765 ;
     RECT  2.16 19.035 34.56 19.305 ;
     RECT  2.16 19.575 34.56 19.845 ;
     RECT  2.16 20.115 34.56 20.385 ;
     RECT  2.16 20.655 34.56 20.925 ;
     RECT  2.16 21.195 34.56 21.465 ;
     RECT  2.16 21.735 34.56 22.005 ;
     RECT  2.16 22.275 34.56 22.545 ;
     RECT  2.16 22.815 34.56 23.085 ;
     RECT  2.16 23.355 34.56 23.625 ;
     RECT  2.16 23.895 34.56 24.165 ;
     RECT  2.16 24.435 34.56 24.705 ;
     RECT  2.16 24.975 34.56 25.245 ;
     RECT  2.16 25.515 34.56 25.785 ;
     RECT  2.16 26.055 34.56 26.325 ;
     RECT  2.16 26.595 34.56 26.865 ;
     RECT  2.16 27.135 34.56 27.405 ;
     RECT  2.16 27.675 34.56 27.945 ;
     RECT  2.16 28.215 34.56 28.485 ;
     RECT  2.16 28.755 34.56 29.025 ;
     RECT  2.16 29.295 34.56 29.565 ;
     RECT  2.16 29.835 34.56 30.105 ;
     RECT  2.16 30.375 34.56 30.645 ;
     RECT  2.16 30.915 34.56 31.185 ;
     RECT  2.16 31.455 34.56 31.725 ;
     RECT  2.16 31.995 34.56 32.265 ;
     RECT  2.16 32.535 34.56 32.805 ;
     RECT  2.16 33.075 34.56 33.345 ;
     RECT  2.16 33.615 34.56 33.885 ;
     RECT  2.16 34.155 34.56 34.425 ;
     RECT  2.16 34.695 34.56 34.965 ;
     RECT  2.16 35.235 34.56 35.505 ;
     RECT  2.16 35.775 34.56 36.045 ;
     RECT  2.16 36.315 34.56 36.585 ;
     RECT  2.16 36.855 34.56 37.125 ;
     RECT  2.16 37.395 34.56 37.665 ;
     RECT  2.16 37.935 34.56 38.205 ;
     RECT  2.16 38.475 34.56 38.745 ;
     RECT  2.16 39.015 34.56 39.285 ;
     RECT  2.16 39.555 34.56 39.825 ;
     RECT  2.16 40.095 34.56 40.365 ;
     RECT  2.16 40.635 34.56 40.905 ;
     RECT  2.16 41.175 34.56 41.445 ;
     RECT  2.16 41.715 34.56 41.985 ;
     RECT  2.16 42.255 34.56 42.525 ;
     RECT  2.16 42.795 34.56 43.065 ;
     RECT  2.16 43.335 34.56 43.605 ;
     RECT  2.16 43.875 34.56 44.145 ;
     RECT  2.16 44.415 34.56 44.685 ;
     RECT  2.16 44.955 34.56 45.225 ;
     RECT  2.16 45.495 34.56 45.765 ;
     RECT  2.16 46.035 34.56 46.305 ;
     RECT  2.16 46.575 34.56 46.845 ;
     RECT  2.16 47.115 34.56 47.385 ;
     RECT  2.16 47.655 34.56 47.925 ;
     RECT  2.16 48.195 34.56 48.465 ;
     RECT  2.16 48.735 34.56 49.005 ;
     RECT  2.16 49.275 34.56 49.545 ;
     RECT  2.16 49.815 34.56 50.085 ;
     RECT  2.16 50.355 34.56 50.625 ;
     RECT  2.16 50.895 34.56 51.165 ;
     RECT  2.16 51.435 34.56 51.705 ;
     RECT  2.16 51.975 34.56 52.245 ;
     RECT  2.16 52.515 34.56 52.785 ;
     RECT  2.16 53.055 34.56 53.325 ;
     RECT  2.16 53.595 34.56 53.865 ;
     RECT  2.16 54.135 34.56 54.405 ;
     RECT  2.16 54.675 34.56 54.945 ;
     RECT  2.16 55.215 34.56 55.485 ;
     RECT  2.16 55.755 34.56 56.025 ;
     RECT  2.16 56.295 34.56 56.565 ;
     RECT  2.16 56.835 34.56 57.105 ;
     RECT  2.16 57.375 34.56 57.645 ;
     RECT  2.16 57.915 34.56 58.185 ;
     RECT  2.16 58.455 34.56 58.725 ;
     RECT  2.16 58.995 34.56 59.265 ;
     RECT  2.16 59.535 34.56 59.805 ;
     RECT  2.16 60.075 34.56 60.345 ;
     RECT  2.16 60.615 34.56 60.885 ;
     RECT  2.16 61.155 34.56 61.425 ;
     RECT  2.16 61.695 34.56 61.965 ;
     RECT  2.16 62.235 34.56 62.505 ;
     RECT  2.16 62.775 34.56 63.045 ;
     RECT  2.16 63.315 34.56 63.585 ;
     RECT  2.16 63.855 34.56 64.125 ;
     RECT  2.16 64.395 34.56 64.665 ;
     RECT  2.16 64.935 34.56 65.205 ;
     RECT  2.16 65.475 34.56 65.745 ;
     RECT  2.16 66.015 34.56 66.285 ;
     RECT  2.16 66.555 34.56 66.825 ;
     RECT  2.16 67.095 34.56 67.365 ;
     RECT  2.16 67.635 34.56 67.905 ;
     RECT  2.16 68.175 34.56 68.445 ;
     RECT  2.16 68.715 34.56 68.985 ;
     RECT  2.16 69.255 34.56 69.525 ;
     RECT  2.16 69.795 34.56 70.065 ;
     RECT  2.16 70.335 34.56 70.605 ;
     RECT  2.16 70.875 34.56 71.145 ;
     RECT  2.16 71.415 34.56 71.685 ;
     RECT  2.16 71.955 34.56 72.225 ;
     RECT  2.16 72.495 34.56 72.765 ;
     RECT  2.16 73.035 34.56 73.305 ;
     RECT  2.16 73.575 34.56 73.845 ;
     RECT  2.16 74.115 34.56 74.385 ;
     RECT  2.16 74.655 34.56 74.925 ;
     RECT  2.16 75.195 34.56 75.465 ;
     RECT  2.16 75.735 34.56 76.005 ;
     RECT  2.16 76.275 34.56 76.545 ;
     RECT  2.16 76.815 34.56 77.085 ;
     RECT  2.16 77.355 34.56 77.625 ;
     RECT  2.16 77.895 34.56 78.165 ;
     RECT  2.16 78.435 34.56 78.705 ;
     RECT  2.16 78.975 34.56 79.245 ;
     RECT  2.16 79.515 34.56 79.785 ;
     RECT  2.16 80.055 34.56 80.325 ;
     RECT  2.16 80.595 34.56 80.865 ;
     RECT  2.16 81.135 34.56 81.405 ;
     RECT  2.16 81.675 34.56 81.945 ;
     RECT  2.16 82.215 34.56 82.485 ;
     RECT  2.16 82.755 34.56 83.025 ;
     RECT  2.16 83.295 34.56 83.565 ;
     RECT  2.16 83.835 34.56 84.105 ;
     RECT  2.16 84.375 34.56 84.645 ;
     RECT  2.16 84.915 34.56 85.185 ;
     RECT  2.16 85.455 34.56 85.725 ;
     RECT  2.16 85.995 34.56 86.265 ;
     RECT  2.16 86.535 34.56 86.805 ;
     RECT  2.16 87.075 34.56 87.345 ;
     RECT  2.16 87.615 34.56 87.885 ;
     RECT  2.16 88.155 34.56 88.425 ;
     RECT  2.16 88.695 34.56 88.965 ;
     RECT  2.16 89.235 34.56 89.505 ;
     RECT  2.16 89.775 34.56 90.045 ;
     RECT  2.16 90.315 34.56 90.585 ;
    LAYER M1 ;
     RECT  2.16 2.151 34.56 90.729 ;
    LAYER M2 ;
     RECT  0.535 8.82 2.16 8.838 ;
     RECT  0.535 15.3 2.16 15.318 ;
     RECT  0.211 27.342 2.16 27.36 ;
     RECT  0.535 48.942 2.16 49.572 ;
     RECT  0.535 52.866 2.16 52.884 ;
     RECT  18.175 92.718 18.383 92.736 ;
     RECT  2.16 2.151 34.56 90.729 ;
     RECT  34.56 3.726 34.763 12.654 ;
     RECT  34.56 13.446 34.763 24.534 ;
     RECT  34.56 25.326 34.763 35.064 ;
     RECT  34.56 36.054 34.763 65.502 ;
     RECT  34.56 66.366 34.763 90.234 ;
     RECT  34.763 13.446 34.799 17.874 ;
     RECT  34.763 25.326 34.799 33.678 ;
     RECT  34.763 52.866 34.799 65.502 ;
     RECT  34.763 66.366 34.799 72.018 ;
     RECT  34.763 79.866 34.799 82.278 ;
     RECT  34.763 83.106 34.799 90.234 ;
     RECT  34.763 36.054 34.835 52.074 ;
     RECT  34.799 79.866 34.871 80.658 ;
     RECT  34.799 83.106 35.339 87.408 ;
     RECT  34.763 3.726 35.375 11.304 ;
     RECT  34.763 12.186 35.375 12.654 ;
     RECT  34.799 13.716 35.375 17.748 ;
     RECT  34.763 18.774 35.375 24.534 ;
     RECT  34.799 27.684 35.375 33.678 ;
     RECT  34.763 34.434 35.375 35.064 ;
     RECT  34.835 36.054 35.375 38.538 ;
     RECT  34.835 39.366 35.375 47.214 ;
     RECT  34.835 48.204 35.375 52.074 ;
     RECT  34.799 61.668 35.375 65.502 ;
     RECT  34.799 66.366 35.375 68.004 ;
     RECT  34.799 69.066 35.375 72.018 ;
     RECT  34.763 72.936 35.375 79.074 ;
     RECT  34.871 79.866 35.375 80.622 ;
     RECT  34.799 81.486 35.375 82.278 ;
     RECT  35.339 83.916 35.375 87.408 ;
     RECT  34.799 88.506 35.375 90.234 ;
     RECT  35.375 3.726 35.411 4.284 ;
     RECT  35.375 5.076 35.411 5.094 ;
     RECT  35.375 7.47 35.411 8.064 ;
     RECT  35.375 10.296 35.411 11.304 ;
     RECT  35.375 12.366 35.411 12.654 ;
     RECT  35.375 15.804 35.411 17.748 ;
     RECT  35.375 43.686 35.411 45.324 ;
     RECT  34.799 56.304 35.411 60.606 ;
     RECT  35.375 70.038 35.411 72.018 ;
     RECT  35.375 81.486 35.411 82.242 ;
     RECT  35.375 83.916 35.411 85.284 ;
     RECT  35.375 89.676 35.411 90.234 ;
     RECT  35.411 15.876 35.447 17.748 ;
     RECT  35.375 36.396 35.447 36.954 ;
     RECT  35.375 49.896 35.447 52.038 ;
     RECT  35.411 81.648 35.447 81.936 ;
     RECT  35.411 3.726 35.483 4.104 ;
     RECT  35.447 16.146 35.483 17.748 ;
     RECT  35.375 19.476 35.915 23.652 ;
     RECT  35.375 24.48 35.915 24.534 ;
     RECT  35.375 34.506 35.915 35.064 ;
     RECT  35.375 37.746 35.915 38.268 ;
     RECT  34.799 52.866 35.915 55.548 ;
     RECT  35.483 3.852 35.951 4.104 ;
     RECT  35.411 7.47 35.951 7.488 ;
     RECT  35.411 10.944 35.951 11.304 ;
     RECT  35.411 12.564 35.951 12.654 ;
     RECT  35.375 13.716 35.951 15.012 ;
     RECT  35.483 16.308 35.951 17.748 ;
     RECT  35.915 19.584 35.951 23.652 ;
     RECT  35.915 24.48 35.951 24.498 ;
     RECT  34.799 25.326 35.951 26.784 ;
     RECT  35.375 28.224 35.951 32.328 ;
     RECT  35.375 33.12 35.951 33.678 ;
     RECT  35.915 34.506 35.951 34.794 ;
     RECT  35.447 36.594 35.951 36.954 ;
     RECT  35.915 37.746 35.951 38.232 ;
     RECT  35.375 39.366 35.951 42.894 ;
     RECT  35.411 43.956 35.951 45.324 ;
     RECT  35.375 46.314 35.951 47.178 ;
     RECT  35.375 48.204 35.951 48.996 ;
     RECT  35.447 49.896 35.951 49.914 ;
     RECT  35.447 50.94 35.951 52.038 ;
     RECT  35.915 52.866 35.951 54.504 ;
     RECT  35.915 55.296 35.951 55.548 ;
     RECT  35.411 56.304 35.951 56.322 ;
     RECT  35.411 57.114 35.951 60.606 ;
     RECT  35.375 61.668 35.951 65.304 ;
     RECT  35.375 66.366 35.951 67.662 ;
     RECT  35.375 69.066 35.951 69.282 ;
     RECT  35.411 70.038 35.951 70.056 ;
     RECT  35.411 70.884 35.951 72.018 ;
     RECT  35.375 73.35 35.951 79.074 ;
     RECT  35.375 79.866 35.951 80.154 ;
     RECT  35.447 81.918 35.951 81.936 ;
     RECT  35.339 83.106 35.951 83.124 ;
     RECT  35.411 84.114 35.951 84.474 ;
     RECT  35.411 85.266 35.951 85.284 ;
     RECT  35.375 86.076 35.951 87.408 ;
     RECT  35.411 89.856 35.951 90.234 ;
     RECT  35.951 4.086 35.987 4.104 ;
     RECT  35.951 13.986 35.987 14.004 ;
     RECT  35.951 16.308 35.987 16.434 ;
     RECT  35.951 17.19 35.987 17.244 ;
     RECT  35.951 20.124 35.987 21.258 ;
     RECT  35.951 22.356 35.987 23.076 ;
     RECT  35.951 25.83 35.987 26.694 ;
     RECT  35.951 28.566 35.987 31.68 ;
     RECT  35.951 36.63 35.987 36.954 ;
     RECT  35.951 39.366 35.987 39.924 ;
     RECT  35.951 41.724 35.987 41.742 ;
     RECT  35.951 44.388 35.987 44.406 ;
     RECT  35.951 48.474 35.987 48.69 ;
     RECT  35.951 50.94 35.987 51.732 ;
     RECT  35.951 53.136 35.987 54.504 ;
     RECT  35.951 55.53 35.987 55.548 ;
     RECT  35.951 57.186 35.987 57.708 ;
     RECT  35.951 59.004 35.987 59.022 ;
     RECT  35.951 62.208 35.987 63.846 ;
     RECT  35.951 64.674 35.987 65.304 ;
     RECT  35.951 70.956 35.987 70.974 ;
     RECT  35.951 72 35.987 72.018 ;
     RECT  35.951 75.204 35.987 75.294 ;
     RECT  35.951 76.086 35.987 76.104 ;
     RECT  35.951 77.058 35.987 78.264 ;
     RECT  35.951 80.136 35.987 80.154 ;
     RECT  35.951 84.456 35.987 84.474 ;
     RECT  35.951 86.076 35.987 86.094 ;
     RECT  35.951 86.886 35.987 87.408 ;
     RECT  35.375 88.506 35.987 88.524 ;
     RECT  35.987 16.416 36.023 16.434 ;
     RECT  35.987 20.664 36.023 21.258 ;
     RECT  35.987 26.298 36.023 26.316 ;
     RECT  35.987 29.646 36.023 29.862 ;
     RECT  35.987 31.662 36.023 31.68 ;
     RECT  35.951 33.12 36.023 33.138 ;
     RECT  35.987 36.63 36.023 36.648 ;
     RECT  35.951 46.35 36.023 47.106 ;
     RECT  35.987 48.474 36.023 48.492 ;
     RECT  35.987 51.444 36.023 51.462 ;
     RECT  35.987 54.486 36.023 54.504 ;
     RECT  35.987 57.69 36.023 57.708 ;
     RECT  35.987 62.55 36.023 62.568 ;
     RECT  35.987 63.324 36.023 63.342 ;
     RECT  35.987 65.016 36.023 65.304 ;
     RECT  35.951 67.068 36.023 67.428 ;
     RECT  35.951 73.35 36.023 73.872 ;
     RECT  35.987 75.204 36.023 75.222 ;
     RECT  35.987 77.94 36.023 77.958 ;
     RECT  35.951 89.856 36.023 89.874 ;
     RECT  35.987 17.19 36.059 17.208 ;
     RECT  36.023 20.736 36.059 21.258 ;
     RECT  36.023 29.646 36.059 29.664 ;
     RECT  36.023 65.286 36.059 65.304 ;
     RECT  36.023 73.35 36.059 73.368 ;
     RECT  36.059 21.24 36.095 21.258 ;
     RECT  36.023 67.068 36.131 67.086 ;
    LAYER M3 ;
     RECT  2.415 2.143 2.505 2.413 ;
     RECT  5.115 2.143 5.205 2.413 ;
     RECT  7.815 2.143 7.905 2.413 ;
     RECT  10.515 2.143 10.605 2.413 ;
     RECT  13.215 2.143 13.305 2.413 ;
     RECT  15.915 2.143 16.005 2.413 ;
     RECT  18.615 2.143 18.705 2.413 ;
     RECT  21.315 2.143 21.405 2.413 ;
     RECT  24.015 2.143 24.105 2.413 ;
     RECT  26.715 2.143 26.805 2.413 ;
     RECT  29.415 2.143 29.505 2.413 ;
     RECT  32.115 2.143 32.205 2.413 ;
     RECT  32.115 2.413 32.397 3.685 ;
     RECT  35.46 3.721 35.478 3.847 ;
     RECT  35.46 3.847 35.946 3.919 ;
     RECT  33.912 3.811 33.93 3.955 ;
     RECT  33.804 3.955 34.218 4.081 ;
     RECT  35.424 3.919 35.946 4.081 ;
     RECT  2.415 2.413 2.697 4.225 ;
     RECT  32.115 3.685 32.85 4.225 ;
     RECT  33.588 4.081 34.218 4.225 ;
     RECT  3.816 4.081 3.834 4.261 ;
     RECT  35.424 4.081 35.982 4.261 ;
     RECT  3.528 4.261 4.014 4.415 ;
     RECT  3.996 4.415 4.014 4.531 ;
     RECT  5.115 2.413 5.397 4.531 ;
     RECT  35.388 4.261 35.982 4.531 ;
     RECT  2.415 4.225 2.754 4.555 ;
     RECT  4.932 4.531 5.397 4.801 ;
     RECT  32.115 4.225 34.254 4.801 ;
     RECT  2.304 4.555 2.754 4.999 ;
     RECT  3.996 4.531 4.086 5.035 ;
     RECT  4.824 4.801 5.778 5.035 ;
     RECT  6.84 4.927 6.858 5.035 ;
     RECT  7.815 2.413 8.097 5.035 ;
     RECT  3.996 5.035 5.778 5.071 ;
     RECT  6.84 5.035 8.097 5.071 ;
     RECT  6.84 5.071 8.586 5.072 ;
     RECT  2.304 4.999 2.934 5.099 ;
     RECT  6.84 5.072 6.858 5.099 ;
     RECT  35.352 4.531 35.982 5.117 ;
     RECT  7.815 5.072 8.586 5.189 ;
     RECT  10.515 2.413 10.797 5.197 ;
     RECT  30.78 4.657 30.798 5.197 ;
     RECT  3.996 5.071 5.85 5.341 ;
     RECT  10.515 5.197 10.926 5.369 ;
     RECT  35.352 5.117 35.478 5.405 ;
     RECT  3.852 5.341 5.85 5.431 ;
     RECT  30.78 5.197 30.87 5.531 ;
     RECT  35.352 5.405 35.406 5.597 ;
     RECT  7.815 5.189 8.226 5.741 ;
     RECT  3.852 5.431 5.994 5.971 ;
     RECT  6.84 5.881 6.858 6.007 ;
     RECT  2.304 5.099 2.718 6.043 ;
     RECT  32.115 4.801 34.434 6.115 ;
     RECT  2.304 6.043 2.862 6.151 ;
     RECT  3.78 5.971 5.994 6.151 ;
     RECT  6.84 6.007 6.93 6.151 ;
     RECT  10.515 5.369 10.797 6.151 ;
     RECT  32.04 6.115 34.434 6.151 ;
     RECT  35.352 5.597 35.37 6.151 ;
     RECT  2.304 6.151 6.93 6.269 ;
     RECT  10.515 6.151 10.854 6.269 ;
     RECT  30.852 5.531 30.87 6.349 ;
     RECT  3.996 6.269 6.93 6.385 ;
     RECT  2.304 6.269 2.862 6.413 ;
     RECT  3.996 6.385 6.966 6.461 ;
     RECT  7.815 5.741 8.118 6.539 ;
     RECT  30.78 6.349 30.87 6.683 ;
     RECT  32.04 6.151 35.37 6.817 ;
     RECT  31.788 6.817 35.37 7.187 ;
     RECT  3.996 6.461 6.822 7.231 ;
     RECT  9.468 7.231 9.594 7.321 ;
     RECT  9.468 7.321 9.666 7.421 ;
     RECT  35.928 7.339 35.946 7.493 ;
     RECT  2.304 6.413 2.697 7.501 ;
     RECT  2.268 7.501 2.697 7.565 ;
     RECT  3.528 7.231 6.822 7.627 ;
     RECT  31.788 7.187 34.83 7.655 ;
     RECT  3.456 7.627 6.822 7.699 ;
     RECT  30.852 7.501 30.87 7.727 ;
     RECT  3.456 7.699 6.858 7.735 ;
     RECT  2.304 7.565 2.697 7.771 ;
     RECT  3.456 7.735 7.038 7.771 ;
     RECT  7.815 6.539 8.097 7.867 ;
     RECT  30.78 7.735 30.798 7.889 ;
     RECT  7.815 7.867 8.478 7.925 ;
     RECT  7.815 7.925 8.334 8.033 ;
     RECT  31.824 7.655 34.83 8.041 ;
     RECT  2.304 7.771 7.038 8.159 ;
     RECT  9.36 8.041 9.378 8.159 ;
     RECT  7.815 8.033 8.262 8.195 ;
     RECT  3.456 8.159 7.038 8.311 ;
     RECT  7.815 8.195 8.097 8.311 ;
     RECT  31.824 8.041 35.406 8.339 ;
     RECT  32.04 8.339 35.406 8.525 ;
     RECT  2.304 8.159 2.697 8.941 ;
     RECT  3.456 8.311 8.097 8.941 ;
     RECT  32.04 8.525 35.37 9.053 ;
     RECT  2.304 8.941 8.097 9.121 ;
     RECT  0.54 8.815 0.558 9.197 ;
     RECT  2.304 9.121 8.118 9.239 ;
     RECT  10.515 6.269 10.797 9.247 ;
     RECT  10.515 9.247 10.818 9.383 ;
     RECT  6.408 9.239 8.118 9.419 ;
     RECT  35.352 9.053 35.37 9.643 ;
     RECT  7.38 9.419 8.118 9.661 ;
     RECT  2.304 9.239 5.67 9.677 ;
     RECT  7.38 9.661 8.406 9.689 ;
     RECT  7.74 9.689 8.406 9.851 ;
     RECT  32.04 9.053 34.326 10.123 ;
     RECT  35.352 9.643 35.406 10.123 ;
     RECT  32.04 10.123 35.406 10.165 ;
     RECT  6.408 9.419 6.57 10.201 ;
     RECT  31.932 10.165 35.406 10.319 ;
     RECT  30.78 9.247 30.798 10.363 ;
     RECT  2.304 9.677 5.397 10.471 ;
     RECT  6.228 10.201 6.642 10.471 ;
     RECT  2.304 10.471 6.642 10.669 ;
     RECT  32.112 10.319 35.406 10.697 ;
     RECT  32.112 10.697 34.866 10.733 ;
     RECT  7.74 9.851 8.37 10.831 ;
     RECT  2.304 10.669 6.93 10.867 ;
     RECT  7.74 10.831 8.874 10.867 ;
     RECT  2.304 10.867 8.946 10.931 ;
     RECT  8.928 10.931 8.946 11.039 ;
     RECT  30.78 10.363 30.87 11.039 ;
     RECT  0.252 11.179 0.27 11.309 ;
     RECT  30.78 11.039 30.798 11.309 ;
     RECT  35.928 10.795 35.946 11.315 ;
     RECT  2.304 10.931 8.19 11.435 ;
     RECT  3.42 11.435 8.19 11.669 ;
     RECT  32.115 10.733 34.866 11.785 ;
     RECT  2.304 11.435 2.697 11.803 ;
     RECT  32.04 11.785 34.866 11.849 ;
     RECT  9 11.443 9.234 12.019 ;
     RECT  7.056 11.669 8.19 12.055 ;
     RECT  7.056 12.055 8.226 12.091 ;
     RECT  9 12.019 9.27 12.091 ;
     RECT  32.04 11.849 34.218 12.091 ;
     RECT  35.352 11.947 35.37 12.091 ;
     RECT  2.268 11.803 2.697 12.181 ;
     RECT  3.42 11.669 6.21 12.181 ;
     RECT  2.268 12.181 6.21 12.209 ;
     RECT  7.056 12.091 9.27 12.209 ;
     RECT  35.352 12.091 35.406 12.283 ;
     RECT  2.268 12.209 6.03 12.461 ;
     RECT  35.352 12.283 35.946 12.461 ;
     RECT  7.056 12.209 8.097 12.631 ;
     RECT  35.928 12.461 35.946 12.659 ;
     RECT  31.896 12.091 34.218 12.763 ;
     RECT  2.304 12.461 6.03 12.929 ;
     RECT  31.896 12.763 34.794 13.019 ;
     RECT  30.78 12.757 30.798 13.091 ;
     RECT  32.115 13.019 34.794 13.243 ;
     RECT  3.96 12.929 6.03 13.405 ;
     RECT  6.804 12.631 8.097 13.405 ;
     RECT  32.115 13.243 35.37 13.435 ;
     RECT  32.115 13.435 35.946 13.469 ;
     RECT  3.96 13.405 8.097 13.559 ;
     RECT  9.036 13.171 9.054 13.559 ;
     RECT  34.956 13.469 35.946 13.579 ;
     RECT  3.96 13.559 6.21 13.595 ;
     RECT  4.032 13.595 6.21 13.631 ;
     RECT  2.304 12.929 2.862 13.771 ;
     RECT  4.392 13.631 6.21 13.829 ;
     RECT  34.956 13.579 35.982 13.829 ;
     RECT  30.852 13.531 30.87 13.873 ;
     RECT  2.304 13.771 3.15 13.981 ;
     RECT  32.115 13.469 34.218 13.981 ;
     RECT  35.928 13.829 35.982 14.009 ;
     RECT  2.304 13.981 3.294 14.059 ;
     RECT  2.268 14.059 3.294 14.099 ;
     RECT  30.78 13.873 30.87 14.243 ;
     RECT  32.076 13.981 34.218 14.251 ;
     RECT  34.956 13.829 34.974 14.251 ;
     RECT  32.076 14.251 34.974 14.341 ;
     RECT  30.78 14.243 30.798 14.369 ;
     RECT  2.268 14.099 3.186 14.405 ;
     RECT  7.02 13.559 8.097 14.485 ;
     RECT  4.392 13.829 6.102 14.521 ;
     RECT  7.02 14.485 8.118 14.521 ;
     RECT  32.04 14.341 34.974 14.587 ;
     RECT  35.928 14.009 35.946 14.587 ;
     RECT  32.04 14.587 35.946 14.611 ;
     RECT  8.964 14.521 8.982 14.639 ;
     RECT  6.876 14.521 8.118 14.711 ;
     RECT  31.716 14.611 35.946 14.711 ;
     RECT  6.876 14.711 6.894 14.819 ;
     RECT  4.068 14.521 6.102 14.875 ;
     RECT  2.304 14.405 3.186 14.881 ;
     RECT  4.068 14.875 6.822 14.881 ;
     RECT  2.304 14.881 6.822 14.915 ;
     RECT  32.04 14.711 35.946 15.017 ;
     RECT  7.74 14.711 8.118 15.061 ;
     RECT  32.04 15.017 35.442 15.179 ;
     RECT  9.108 15.025 9.126 15.287 ;
     RECT  30.78 15.223 30.798 15.323 ;
     RECT  32.076 15.179 35.442 15.359 ;
     RECT  0.54 15.295 0.558 15.437 ;
     RECT  2.304 14.915 6.642 15.557 ;
     RECT  7.74 15.061 8.19 15.691 ;
     RECT  35.352 15.359 35.442 15.739 ;
     RECT  7.38 15.691 8.19 15.869 ;
     RECT  6.624 15.557 6.642 15.871 ;
     RECT  7.38 15.869 8.097 15.871 ;
     RECT  31.032 15.727 31.05 15.997 ;
     RECT  32.076 15.359 34.254 15.997 ;
     RECT  2.304 15.557 5.814 16.303 ;
     RECT  6.624 15.871 8.097 16.303 ;
     RECT  35.352 15.739 35.478 16.303 ;
     RECT  0.252 16.219 0.27 16.349 ;
     RECT  35.352 16.303 35.982 16.411 ;
     RECT  35.352 16.411 36.018 16.529 ;
     RECT  2.304 16.303 8.097 16.681 ;
     RECT  2.268 16.681 8.097 16.733 ;
     RECT  8.928 16.411 8.946 16.799 ;
     RECT  29.415 2.413 29.697 16.807 ;
     RECT  31.032 15.997 34.254 16.915 ;
     RECT  31.032 16.915 34.83 17.069 ;
     RECT  35.928 16.529 36.018 17.185 ;
     RECT  2.304 16.733 8.097 17.221 ;
     RECT  10.515 9.383 10.797 17.221 ;
     RECT  29.415 16.807 30.222 17.311 ;
     RECT  2.304 17.221 8.298 17.339 ;
     RECT  10.515 17.221 10.854 17.447 ;
     RECT  35.928 17.185 36.054 17.549 ;
     RECT  29.415 17.311 30.87 17.609 ;
     RECT  0.216 17.515 0.234 17.645 ;
     RECT  2.304 17.339 8.097 17.645 ;
     RECT  30.78 17.609 30.87 17.681 ;
     RECT  31.608 17.069 34.83 17.689 ;
     RECT  35.928 17.549 35.946 17.689 ;
     RECT  2.304 17.645 6.642 17.753 ;
     RECT  31.608 17.689 35.946 17.753 ;
     RECT  2.304 17.753 5.397 17.879 ;
     RECT  9.432 17.581 9.45 17.879 ;
     RECT  30.852 17.681 30.87 17.887 ;
     RECT  31.608 17.753 35.37 17.887 ;
     RECT  30.852 17.887 35.37 18.023 ;
     RECT  31.284 18.023 35.37 18.059 ;
     RECT  6.192 17.753 6.642 18.149 ;
     RECT  9.036 18.031 9.054 18.149 ;
     RECT  2.304 17.879 3.258 18.221 ;
     RECT  6.192 18.149 6.282 18.419 ;
     RECT  31.284 18.059 34.29 18.419 ;
     RECT  32.004 18.419 34.29 18.455 ;
     RECT  4.104 17.879 5.397 18.571 ;
     RECT  35.352 18.059 35.37 18.667 ;
     RECT  7.524 17.645 8.097 18.841 ;
     RECT  4.104 18.571 6.03 18.931 ;
     RECT  30.852 18.841 30.87 18.967 ;
     RECT  32.115 18.455 34.29 19.003 ;
     RECT  35.352 18.667 35.91 19.003 ;
     RECT  30.78 18.967 30.87 19.031 ;
     RECT  32.115 19.003 35.91 19.067 ;
     RECT  7.488 18.841 8.097 19.088 ;
     RECT  35.352 19.067 35.91 19.339 ;
     RECT  32.115 19.067 34.29 19.345 ;
     RECT  35.352 19.339 35.946 19.373 ;
     RECT  3.888 18.931 6.03 19.387 ;
     RECT  7.02 19.088 8.097 19.387 ;
     RECT  2.304 18.221 3.114 19.471 ;
     RECT  3.888 19.387 8.097 19.471 ;
     RECT  9.504 19.381 9.522 19.499 ;
     RECT  31.716 19.345 34.29 19.499 ;
     RECT  35.856 19.373 35.946 19.571 ;
     RECT  0.252 19.483 0.27 19.613 ;
     RECT  2.304 19.471 8.097 19.651 ;
     RECT  31.752 19.499 34.29 19.813 ;
     RECT  2.304 19.651 8.226 19.877 ;
     RECT  7.815 19.877 8.226 19.921 ;
     RECT  35.928 19.571 35.946 19.963 ;
     RECT  10.515 17.447 10.797 20.011 ;
     RECT  31.752 19.813 34.326 20.039 ;
     RECT  7.815 19.921 8.694 20.047 ;
     RECT  10.515 20.011 10.854 20.111 ;
     RECT  35.928 19.963 35.982 20.146 ;
     RECT  30.78 19.031 30.798 20.191 ;
     RECT  7.815 20.047 8.838 20.309 ;
     RECT  31.752 20.039 34.29 20.309 ;
     RECT  7.815 20.309 8.334 20.345 ;
     RECT  31.752 20.309 34.254 20.381 ;
     RECT  35.928 20.146 36.018 20.491 ;
     RECT  2.304 19.877 6.75 20.579 ;
     RECT  7.815 20.345 8.262 20.579 ;
     RECT  35.928 20.491 36.054 20.635 ;
     RECT  29.415 17.609 29.697 20.731 ;
     RECT  30.78 20.191 30.87 20.731 ;
     RECT  31.752 20.381 34.146 20.731 ;
     RECT  35.928 20.635 36.09 20.821 ;
     RECT  7.815 20.579 8.097 20.929 ;
     RECT  2.304 20.579 6.354 20.993 ;
     RECT  35.352 20.821 36.09 21.263 ;
     RECT  29.415 20.731 29.754 21.299 ;
     RECT  30.78 20.731 34.146 21.307 ;
     RECT  35.352 21.263 35.982 21.307 ;
     RECT  7.164 20.929 8.097 21.361 ;
     RECT  6.84 21.361 8.097 21.389 ;
     RECT  30.78 21.307 35.982 21.425 ;
     RECT  6.84 21.389 7.074 21.497 ;
     RECT  30.78 21.425 30.942 21.497 ;
     RECT  32.076 21.425 35.982 21.497 ;
     RECT  32.076 21.497 34.794 21.533 ;
     RECT  7.815 21.389 8.097 21.541 ;
     RECT  6.84 21.497 6.93 21.659 ;
     RECT  7.815 21.541 8.514 21.659 ;
     RECT  32.076 21.533 34.254 22.037 ;
     RECT  30.852 21.497 30.942 22.073 ;
     RECT  7.815 21.659 8.097 22.123 ;
     RECT  2.304 20.993 5.85 22.235 ;
     RECT  6.84 21.659 6.858 22.469 ;
     RECT  30.852 22.073 30.87 22.477 ;
     RECT  30.78 22.477 30.87 22.613 ;
     RECT  30.78 22.613 30.798 22.649 ;
     RECT  34.776 22.459 34.794 22.741 ;
     RECT  35.928 21.497 35.982 22.741 ;
     RECT  32.076 22.037 33.93 22.855 ;
     RECT  34.776 22.741 35.982 22.855 ;
     RECT  7.704 22.123 8.097 22.891 ;
     RECT  32.076 22.855 35.982 22.891 ;
     RECT  7.092 22.891 8.097 23.009 ;
     RECT  31.824 22.891 35.982 23.009 ;
     RECT  32.04 23.009 35.982 23.081 ;
     RECT  2.304 22.235 5.742 23.125 ;
     RECT  2.304 23.125 6.03 23.275 ;
     RECT  2.304 23.275 6.426 23.315 ;
     RECT  7.38 23.009 8.097 23.351 ;
     RECT  7.416 23.351 8.097 23.431 ;
     RECT  7.416 23.431 8.766 23.549 ;
     RECT  7.815 23.549 8.766 23.729 ;
     RECT  32.04 23.081 35.946 23.971 ;
     RECT  7.815 23.729 8.19 24.089 ;
     RECT  10.515 20.111 10.797 24.097 ;
     RECT  10.515 24.097 10.818 24.197 ;
     RECT  32.004 23.971 35.946 24.269 ;
     RECT  35.352 24.269 35.946 24.359 ;
     RECT  2.304 23.315 6.246 24.503 ;
     RECT  35.892 24.359 35.946 24.539 ;
     RECT  30.78 24.097 30.798 24.601 ;
     RECT  32.004 24.269 34.218 24.637 ;
     RECT  2.304 24.503 6.39 24.667 ;
     RECT  2.304 24.667 6.75 24.715 ;
     RECT  30.78 24.601 30.87 24.809 ;
     RECT  2.304 24.715 6.822 24.899 ;
     RECT  31.932 24.637 34.218 24.899 ;
     RECT  3.96 24.899 6.822 24.943 ;
     RECT  7.815 24.089 8.097 24.943 ;
     RECT  3.96 24.943 8.097 25.043 ;
     RECT  32.112 24.899 34.218 25.051 ;
     RECT  4.032 25.043 8.097 25.079 ;
     RECT  8.892 25.051 8.91 25.169 ;
     RECT  35.928 24.539 35.946 25.243 ;
     RECT  32.112 25.051 34.254 25.313 ;
     RECT  30.78 24.809 30.798 25.349 ;
     RECT  2.304 24.899 3.222 25.387 ;
     RECT  2.268 25.387 3.222 25.475 ;
     RECT  32.112 25.313 34.218 25.619 ;
     RECT  32.112 25.619 34.182 25.709 ;
     RECT  35.928 25.243 35.982 25.723 ;
     RECT  35.352 25.723 35.982 25.817 ;
     RECT  4.032 25.079 7.038 25.825 ;
     RECT  35.928 25.817 35.982 25.852 ;
     RECT  2.304 25.475 3.222 25.861 ;
     RECT  4.032 25.825 7.074 25.861 ;
     RECT  9.648 25.825 9.666 25.987 ;
     RECT  0.252 25.867 0.27 26.045 ;
     RECT  30.852 25.753 30.906 26.051 ;
     RECT  8.928 25.987 9.666 26.159 ;
     RECT  30.888 26.051 30.906 26.159 ;
     RECT  2.304 25.861 7.074 26.221 ;
     RECT  7.815 25.079 8.097 26.221 ;
     RECT  35.928 25.852 36.018 26.321 ;
     RECT  2.304 26.221 8.097 26.329 ;
     RECT  8.928 26.159 9.306 26.329 ;
     RECT  33.912 25.709 34.182 26.347 ;
     RECT  10.515 24.197 10.797 26.401 ;
     RECT  10.515 26.401 10.818 26.519 ;
     RECT  32.115 25.709 33.174 26.527 ;
     RECT  33.912 26.347 34.758 26.527 ;
     RECT  32.115 26.527 34.758 26.599 ;
     RECT  35.928 26.321 35.982 26.599 ;
     RECT  32.076 26.599 35.982 26.699 ;
     RECT  32.076 26.699 35.946 26.717 ;
     RECT  2.304 26.329 9.306 26.789 ;
     RECT  35.928 26.717 35.946 26.789 ;
     RECT  32.076 26.717 34.794 26.905 ;
     RECT  32.004 26.905 34.794 26.969 ;
     RECT  2.304 26.789 8.766 27.019 ;
     RECT  29.415 21.299 29.697 27.301 ;
     RECT  30.78 27.103 30.798 27.301 ;
     RECT  2.268 27.019 8.766 27.329 ;
     RECT  2.268 27.329 4.374 27.337 ;
     RECT  5.112 27.329 6.966 27.365 ;
     RECT  0.216 27.337 0.234 27.389 ;
     RECT  2.232 27.337 4.374 27.437 ;
     RECT  5.112 27.365 6.858 27.473 ;
     RECT  29.415 27.301 30.798 27.509 ;
     RECT  7.815 27.329 8.766 27.599 ;
     RECT  5.112 27.473 6.066 27.707 ;
     RECT  35.352 27.499 35.37 27.707 ;
     RECT  32.004 26.969 34.326 27.715 ;
     RECT  31.572 27.715 34.326 27.905 ;
     RECT  9.504 27.949 9.522 28.021 ;
     RECT  30.78 27.509 30.798 28.021 ;
     RECT  32.115 27.905 34.326 28.027 ;
     RECT  6.84 27.473 6.858 28.111 ;
     RECT  7.815 27.599 8.622 28.111 ;
     RECT  6.84 28.111 8.622 28.139 ;
     RECT  30.78 28.021 30.942 28.139 ;
     RECT  35.928 27.835 35.946 28.171 ;
     RECT  9.396 28.021 9.522 28.255 ;
     RECT  30.78 28.139 30.87 28.283 ;
     RECT  6.84 28.139 8.478 28.301 ;
     RECT  6.84 28.301 8.19 28.319 ;
     RECT  32.115 28.027 34.794 28.319 ;
     RECT  2.304 27.437 4.374 28.409 ;
     RECT  7.164 28.319 8.19 28.409 ;
     RECT  9.396 28.255 9.738 28.409 ;
     RECT  2.304 28.409 3.798 28.561 ;
     RECT  35.928 28.171 35.982 28.645 ;
     RECT  5.115 27.707 6.066 28.651 ;
     RECT  7.2 28.409 8.19 28.679 ;
     RECT  2.268 28.561 3.798 28.685 ;
     RECT  35.352 28.645 35.982 28.685 ;
     RECT  4.572 28.651 6.066 28.831 ;
     RECT  32.115 28.319 34.218 28.831 ;
     RECT  4.572 28.831 6.21 28.949 ;
     RECT  30.78 28.283 30.798 29.057 ;
     RECT  35.928 28.685 35.982 29.179 ;
     RECT  35.928 29.179 36.018 29.323 ;
     RECT  31.896 28.831 34.218 29.335 ;
     RECT  2.304 28.685 3.798 29.461 ;
     RECT  4.572 28.949 6.03 29.461 ;
     RECT  7.38 28.679 8.097 29.605 ;
     RECT  31.896 29.335 34.434 29.605 ;
     RECT  7.2 29.605 8.097 29.641 ;
     RECT  35.928 29.323 36.054 29.669 ;
     RECT  7.2 29.641 8.406 29.759 ;
     RECT  10.515 26.519 10.797 29.767 ;
     RECT  35.928 29.669 36.018 29.797 ;
     RECT  35.352 29.797 36.018 29.837 ;
     RECT  10.515 29.767 10.818 29.867 ;
     RECT  35.928 29.837 36.018 29.867 ;
     RECT  2.304 29.461 6.03 29.911 ;
     RECT  2.304 29.911 6.426 29.992 ;
     RECT  7.2 29.759 8.097 29.992 ;
     RECT  30.96 29.605 34.434 29.995 ;
     RECT  2.304 29.992 8.097 30.029 ;
     RECT  30.96 29.995 34.83 30.307 ;
     RECT  30.852 30.307 34.83 30.317 ;
     RECT  2.304 30.029 5.742 30.365 ;
     RECT  2.304 30.365 5.526 30.479 ;
     RECT  30.852 30.317 34.794 30.577 ;
     RECT  2.304 30.479 5.49 30.641 ;
     RECT  30.78 30.577 34.794 30.677 ;
     RECT  30.852 30.677 34.794 30.713 ;
     RECT  6.624 30.029 8.097 31.109 ;
     RECT  6.624 31.109 6.642 31.253 ;
     RECT  30.852 30.713 30.906 31.289 ;
     RECT  2.304 30.641 2.754 31.291 ;
     RECT  35.928 29.867 35.982 31.291 ;
     RECT  3.924 30.641 5.49 31.339 ;
     RECT  32.04 30.713 34.794 31.435 ;
     RECT  35.928 31.291 36.018 31.435 ;
     RECT  2.268 31.291 2.754 31.495 ;
     RECT  32.04 31.435 36.018 31.495 ;
     RECT  2.268 31.495 3.114 31.621 ;
     RECT  3.924 31.339 5.598 31.621 ;
     RECT  2.268 31.621 5.886 31.657 ;
     RECT  31.716 31.495 36.018 31.657 ;
     RECT  2.268 31.657 6.246 31.685 ;
     RECT  31.608 31.657 36.018 31.685 ;
     RECT  31.608 31.685 35.946 31.709 ;
     RECT  30.852 31.289 30.87 31.721 ;
     RECT  9.648 31.531 9.666 31.765 ;
     RECT  8.928 31.765 9.666 31.801 ;
     RECT  2.304 31.685 6.246 31.919 ;
     RECT  8.928 31.801 9.738 31.919 ;
     RECT  31.824 31.709 35.946 31.919 ;
     RECT  3.852 31.919 6.246 32.099 ;
     RECT  31.932 31.919 35.946 32.297 ;
     RECT  3.924 32.099 6.246 32.341 ;
     RECT  3.924 32.341 6.858 32.611 ;
     RECT  7.596 31.109 8.097 32.611 ;
     RECT  2.304 31.919 2.934 32.845 ;
     RECT  3.924 32.611 8.097 32.845 ;
     RECT  31.932 32.297 34.254 32.845 ;
     RECT  30.852 32.773 30.87 32.873 ;
     RECT  35.352 32.297 35.946 32.923 ;
     RECT  31.788 32.845 34.254 33.071 ;
     RECT  35.352 32.923 36.018 33.143 ;
     RECT  30.78 33.241 30.798 33.377 ;
     RECT  2.304 32.845 8.097 33.403 ;
     RECT  31.968 33.071 34.254 33.413 ;
     RECT  35.352 33.143 35.946 33.413 ;
     RECT  10.515 29.867 10.797 33.421 ;
     RECT  2.268 33.403 8.097 33.449 ;
     RECT  32.04 33.413 34.254 33.539 ;
     RECT  35.388 33.413 35.946 33.539 ;
     RECT  2.304 33.449 8.097 33.583 ;
     RECT  32.115 33.539 34.254 33.583 ;
     RECT  2.304 33.583 8.586 33.809 ;
     RECT  2.304 33.809 6.246 33.845 ;
     RECT  3.636 33.845 6.246 33.881 ;
     RECT  9.468 33.961 9.486 34.079 ;
     RECT  10.515 33.421 10.818 34.087 ;
     RECT  6.984 33.809 8.586 34.123 ;
     RECT  10.515 34.087 10.854 34.187 ;
     RECT  32.115 33.583 34.326 34.219 ;
     RECT  32.115 34.219 34.758 34.259 ;
     RECT  6.984 34.123 8.694 34.349 ;
     RECT  32.115 34.259 34.326 34.357 ;
     RECT  35.928 33.539 35.946 34.411 ;
     RECT  32.076 34.357 34.326 34.429 ;
     RECT  35.892 34.411 35.946 34.429 ;
     RECT  30.852 34.321 30.87 34.501 ;
     RECT  3.744 33.881 6.246 34.619 ;
     RECT  6.984 34.349 8.154 34.619 ;
     RECT  31.752 34.429 34.326 34.619 ;
     RECT  3.744 34.619 5.49 34.655 ;
     RECT  2.304 33.845 2.697 34.747 ;
     RECT  6.48 34.663 6.966 34.763 ;
     RECT  30.78 34.501 30.87 34.763 ;
     RECT  35.352 34.429 35.946 34.799 ;
     RECT  2.304 34.747 2.862 35.041 ;
     RECT  35.352 34.799 35.91 35.069 ;
     RECT  31.824 34.619 34.326 35.159 ;
     RECT  30.852 34.763 30.87 35.303 ;
     RECT  2.304 35.041 3.006 35.311 ;
     RECT  3.744 34.655 4.23 35.311 ;
     RECT  5.04 34.655 5.49 35.339 ;
     RECT  7.704 34.619 8.154 35.339 ;
     RECT  6.48 34.763 6.534 35.545 ;
     RECT  2.304 35.311 4.23 35.581 ;
     RECT  6.48 35.545 6.894 35.581 ;
     RECT  35.352 35.069 35.406 35.899 ;
     RECT  7.815 35.339 8.154 35.947 ;
     RECT  6.264 35.581 6.894 35.969 ;
     RECT  31.968 35.159 34.326 35.969 ;
     RECT  2.304 35.581 4.302 36.043 ;
     RECT  5.04 35.339 5.397 36.043 ;
     RECT  35.352 35.899 35.442 36.043 ;
     RECT  2.304 36.043 5.397 36.085 ;
     RECT  6.624 35.969 6.894 36.085 ;
     RECT  7.815 35.947 8.262 36.085 ;
     RECT  9.108 36.049 9.126 36.085 ;
     RECT  7.815 36.085 9.27 36.149 ;
     RECT  35.352 36.043 35.946 36.187 ;
     RECT  2.268 36.085 5.397 36.221 ;
     RECT  7.815 36.149 8.406 36.239 ;
     RECT  2.304 36.221 5.397 36.319 ;
     RECT  31.968 35.969 34.29 36.355 ;
     RECT  9.18 36.149 9.27 36.419 ;
     RECT  31.932 36.355 34.29 36.581 ;
     RECT  6.624 36.085 6.966 36.625 ;
     RECT  7.815 36.239 8.097 36.625 ;
     RECT  35.352 36.187 36.018 36.653 ;
     RECT  31.932 36.581 33.714 36.661 ;
     RECT  35.352 36.653 35.982 36.715 ;
     RECT  31.824 36.661 33.714 36.779 ;
     RECT  0.252 36.715 0.27 36.845 ;
     RECT  6.624 36.625 8.097 36.887 ;
     RECT  34.704 36.715 35.982 36.896 ;
     RECT  34.74 36.896 35.982 36.959 ;
     RECT  7.416 36.887 8.097 37.021 ;
     RECT  8.892 36.931 8.91 37.021 ;
     RECT  30.78 35.743 30.798 37.049 ;
     RECT  34.74 36.959 35.946 37.049 ;
     RECT  2.304 36.319 5.778 37.201 ;
     RECT  7.416 37.021 8.91 37.201 ;
     RECT  32.004 36.779 33.714 37.327 ;
     RECT  7.416 37.201 8.982 37.499 ;
     RECT  0.216 37.435 0.234 37.565 ;
     RECT  7.416 37.499 8.586 37.589 ;
     RECT  32.004 37.327 33.75 37.597 ;
     RECT  31.932 37.597 33.75 37.675 ;
     RECT  34.74 37.049 34.758 37.675 ;
     RECT  2.304 37.201 6.39 37.741 ;
     RECT  7.416 37.589 8.37 37.741 ;
     RECT  10.515 34.187 10.797 37.741 ;
     RECT  2.304 37.741 8.37 37.819 ;
     RECT  31.932 37.675 34.758 37.819 ;
     RECT  35.928 37.049 35.946 37.819 ;
     RECT  2.268 37.819 8.37 37.859 ;
     RECT  10.515 37.741 10.818 37.931 ;
     RECT  2.268 37.859 7.074 38.003 ;
     RECT  30.78 37.903 30.798 38.003 ;
     RECT  31.932 37.819 35.946 38.101 ;
     RECT  2.304 38.003 7.074 38.129 ;
     RECT  7.815 37.859 8.37 38.201 ;
     RECT  31.824 38.101 35.946 38.237 ;
     RECT  31.932 38.237 35.91 38.309 ;
     RECT  32.004 38.309 35.91 38.381 ;
     RECT  2.304 38.129 6.858 38.435 ;
     RECT  9.36 38.011 9.378 38.551 ;
     RECT  9.36 38.551 9.486 38.669 ;
     RECT  30.852 38.785 30.87 38.821 ;
     RECT  9.108 38.821 9.198 38.939 ;
     RECT  30.78 38.821 30.87 39.083 ;
     RECT  3.6 38.435 6.858 39.091 ;
     RECT  7.815 38.201 8.154 39.091 ;
     RECT  30.816 39.083 30.87 39.119 ;
     RECT  3.6 39.091 8.154 39.181 ;
     RECT  2.304 38.435 2.697 39.307 ;
     RECT  3.6 39.181 8.586 39.307 ;
     RECT  32.004 38.381 35.37 39.307 ;
     RECT  30.816 39.119 30.834 39.317 ;
     RECT  32.004 39.307 35.946 39.361 ;
     RECT  31.824 39.361 35.982 39.479 ;
     RECT  2.304 39.307 8.586 39.515 ;
     RECT  3.96 39.515 8.586 39.749 ;
     RECT  3.96 39.749 8.154 39.869 ;
     RECT  9.468 39.865 9.486 39.901 ;
     RECT  31.968 39.479 35.982 39.929 ;
     RECT  9.468 39.901 9.558 40.019 ;
     RECT  3.96 39.869 6.93 40.091 ;
     RECT  30.852 40.063 30.87 40.171 ;
     RECT  9.468 40.019 9.486 40.199 ;
     RECT  31.968 39.929 35.946 40.199 ;
     RECT  7.74 39.869 8.154 40.289 ;
     RECT  2.304 39.515 3.222 40.333 ;
     RECT  3.96 40.091 5.397 40.333 ;
     RECT  6.588 40.091 6.93 40.397 ;
     RECT  2.304 40.333 5.397 40.459 ;
     RECT  2.268 40.459 5.397 40.559 ;
     RECT  2.268 40.559 3.222 40.631 ;
     RECT  6.588 40.397 6.894 40.733 ;
     RECT  6.876 40.733 6.894 40.829 ;
     RECT  30.78 40.171 30.87 40.837 ;
     RECT  2.268 40.631 2.97 40.865 ;
     RECT  3.96 40.559 5.397 40.865 ;
     RECT  30.78 40.837 30.906 40.937 ;
     RECT  3.996 40.865 5.397 41.035 ;
     RECT  35.388 40.199 35.946 41.099 ;
     RECT  35.928 41.099 35.946 41.131 ;
     RECT  7.74 40.289 8.097 41.179 ;
     RECT  9.252 40.711 9.27 41.179 ;
     RECT  31.968 40.199 34.362 41.179 ;
     RECT  9.252 41.179 9.306 41.251 ;
     RECT  31.968 41.179 34.434 41.251 ;
     RECT  9.216 41.251 9.306 41.279 ;
     RECT  6.984 41.179 8.097 41.369 ;
     RECT  7.815 41.369 8.097 41.467 ;
     RECT  6.984 41.369 7.074 41.477 ;
     RECT  9.216 41.279 9.234 41.477 ;
     RECT  2.304 40.865 2.97 41.611 ;
     RECT  3.996 41.035 6.066 41.611 ;
     RECT  30.78 40.937 30.798 41.683 ;
     RECT  35.928 41.131 35.982 41.747 ;
     RECT  31.968 41.251 34.83 41.755 ;
     RECT  6.984 41.477 7.002 41.791 ;
     RECT  2.268 41.611 6.066 42.025 ;
     RECT  6.84 41.791 7.002 42.025 ;
     RECT  7.815 41.467 8.262 42.061 ;
     RECT  30.78 41.683 30.87 42.089 ;
     RECT  7.815 42.061 8.298 42.151 ;
     RECT  7.776 42.151 8.37 42.251 ;
     RECT  31.68 41.755 34.83 42.421 ;
     RECT  35.928 41.747 35.946 42.421 ;
     RECT  2.268 42.025 7.002 42.565 ;
     RECT  31.68 42.421 35.946 42.941 ;
     RECT  31.68 42.941 34.29 42.997 ;
     RECT  7.815 42.251 8.097 43.105 ;
     RECT  7.815 43.105 8.514 43.259 ;
     RECT  31.068 42.997 34.29 43.259 ;
     RECT  2.268 42.565 7.074 43.277 ;
     RECT  2.304 43.277 7.074 43.411 ;
     RECT  7.815 43.259 8.097 43.411 ;
     RECT  2.304 43.411 8.097 43.529 ;
     RECT  32.004 43.259 34.29 43.915 ;
     RECT  35.352 42.941 35.946 43.915 ;
     RECT  32.004 43.915 35.946 44.069 ;
     RECT  35.928 44.069 35.946 44.383 ;
     RECT  32.004 44.069 34.758 44.411 ;
     RECT  32.004 44.411 34.218 44.455 ;
     RECT  35.928 44.383 35.982 44.573 ;
     RECT  2.304 43.529 2.934 44.581 ;
     RECT  3.708 43.529 8.097 44.581 ;
     RECT  2.304 44.581 8.097 44.681 ;
     RECT  6.984 44.681 8.097 44.689 ;
     RECT  30.78 43.681 30.798 44.789 ;
     RECT  31.932 44.455 34.218 44.879 ;
     RECT  6.984 44.689 8.694 45.185 ;
     RECT  32.115 44.879 34.218 45.211 ;
     RECT  7.56 45.185 8.694 45.301 ;
     RECT  35.928 44.573 35.946 45.403 ;
     RECT  32.115 45.211 34.254 45.535 ;
     RECT  35.352 45.403 35.946 45.535 ;
     RECT  32.115 45.535 35.946 45.689 ;
     RECT  2.304 44.681 6.102 45.725 ;
     RECT  3.42 45.725 6.102 45.769 ;
     RECT  30.852 45.463 30.87 45.805 ;
     RECT  7.56 45.301 8.73 45.841 ;
     RECT  30.852 45.805 30.906 45.841 ;
     RECT  2.304 45.725 2.697 45.883 ;
     RECT  7.56 45.841 8.982 45.959 ;
     RECT  35.928 45.689 35.946 46.027 ;
     RECT  7.56 45.959 8.694 46.139 ;
     RECT  30.78 45.841 30.906 46.139 ;
     RECT  3.42 45.769 6.786 46.171 ;
     RECT  32.115 45.689 34.722 46.253 ;
     RECT  32.115 46.253 34.254 46.345 ;
     RECT  35.928 46.027 36.018 46.363 ;
     RECT  3.42 46.171 6.822 46.471 ;
     RECT  7.56 46.139 8.097 46.471 ;
     RECT  31.824 46.345 34.254 46.499 ;
     RECT  2.268 45.883 2.697 46.507 ;
     RECT  3.42 46.471 8.097 46.507 ;
     RECT  35.928 46.363 36.09 46.603 ;
     RECT  2.268 46.507 8.097 46.607 ;
     RECT  35.928 46.603 36.198 46.733 ;
     RECT  35.928 46.733 36.018 46.843 ;
     RECT  30.78 46.139 30.798 46.913 ;
     RECT  31.932 46.499 34.254 47.035 ;
     RECT  35.352 46.843 36.018 47.035 ;
     RECT  31.932 47.035 36.018 47.111 ;
     RECT  9.072 47.083 9.09 47.191 ;
     RECT  2.304 46.607 8.097 47.309 ;
     RECT  9.072 47.191 9.162 47.309 ;
     RECT  31.932 47.111 35.946 47.461 ;
     RECT  2.304 47.309 2.697 47.515 ;
     RECT  9.576 47.461 9.594 47.759 ;
     RECT  31.824 47.461 35.946 47.849 ;
     RECT  35.352 47.849 35.946 47.995 ;
     RECT  2.268 47.515 2.697 48.029 ;
     RECT  31.32 47.857 31.338 48.091 ;
     RECT  2.304 48.029 2.697 48.187 ;
     RECT  3.528 47.309 8.097 48.187 ;
     RECT  35.352 47.995 35.982 48.187 ;
     RECT  31.176 48.091 31.338 48.227 ;
     RECT  31.176 48.227 31.194 48.235 ;
     RECT  30.492 48.235 31.194 48.389 ;
     RECT  31.176 48.389 31.194 48.425 ;
     RECT  35.352 48.187 36.018 48.497 ;
     RECT  2.304 48.187 8.097 48.569 ;
     RECT  32.115 47.849 34.254 48.667 ;
     RECT  35.352 48.497 35.982 48.667 ;
     RECT  2.304 48.569 6.858 48.695 ;
     RECT  32.115 48.667 35.982 48.695 ;
     RECT  32.115 48.695 35.946 48.811 ;
     RECT  3.492 48.695 6.858 48.989 ;
     RECT  32.004 48.811 35.946 49.001 ;
     RECT  8.964 48.811 8.982 49.009 ;
     RECT  32.004 49.001 35.406 49.009 ;
     RECT  8.964 49.009 9.054 49.073 ;
     RECT  3.492 48.989 6.75 49.109 ;
     RECT  2.304 48.695 2.754 49.147 ;
     RECT  3.492 49.109 6.354 49.199 ;
     RECT  9.036 49.073 9.054 49.199 ;
     RECT  2.268 49.147 2.754 49.307 ;
     RECT  31.896 49.009 35.406 49.379 ;
     RECT  3.492 49.199 6.102 49.469 ;
     RECT  30.78 49.243 30.798 49.621 ;
     RECT  31.896 49.379 34.254 49.621 ;
     RECT  30.78 49.621 34.254 49.739 ;
     RECT  2.304 49.307 2.754 49.819 ;
     RECT  3.492 49.469 6.066 49.819 ;
     RECT  35.352 49.379 35.406 49.819 ;
     RECT  0.54 48.937 0.558 49.997 ;
     RECT  7.02 49.891 7.038 50.009 ;
     RECT  2.304 49.819 6.066 50.251 ;
     RECT  35.352 49.819 35.946 50.279 ;
     RECT  35.424 50.279 35.946 50.299 ;
     RECT  2.304 50.251 6.858 50.315 ;
     RECT  35.424 50.299 35.982 50.387 ;
     RECT  7.815 48.569 8.097 50.431 ;
     RECT  9.432 50.287 9.45 50.431 ;
     RECT  7.74 50.431 8.097 50.549 ;
     RECT  9.144 50.431 9.45 50.549 ;
     RECT  32.04 49.739 34.254 50.549 ;
     RECT  9.288 50.549 9.45 50.629 ;
     RECT  9.288 50.629 9.486 50.729 ;
     RECT  32.115 50.549 34.254 50.791 ;
     RECT  35.928 50.387 35.982 50.962 ;
     RECT  3.6 50.315 6.858 51.097 ;
     RECT  30.78 49.739 30.87 51.161 ;
     RECT  3.6 51.097 6.894 51.169 ;
     RECT  9.288 50.729 9.306 51.197 ;
     RECT  7.815 50.549 8.097 51.205 ;
     RECT  7.815 51.205 8.298 51.245 ;
     RECT  32.115 50.791 34.362 51.331 ;
     RECT  3.456 51.169 6.894 51.431 ;
     RECT  35.928 50.962 36.018 51.467 ;
     RECT  2.304 50.315 2.697 51.475 ;
     RECT  3.456 51.431 5.85 51.475 ;
     RECT  32.076 51.331 34.362 51.475 ;
     RECT  31.608 51.475 34.362 51.595 ;
     RECT  31.608 51.595 34.794 51.629 ;
     RECT  35.928 51.467 35.982 51.737 ;
     RECT  2.304 51.475 5.85 51.772 ;
     RECT  6.732 51.431 6.894 51.781 ;
     RECT  2.268 51.772 5.85 51.869 ;
     RECT  6.732 51.781 7.074 51.883 ;
     RECT  7.815 51.245 8.19 51.883 ;
     RECT  30.78 51.161 30.798 51.907 ;
     RECT  9.252 51.871 9.27 51.943 ;
     RECT  2.268 51.869 5.778 52.043 ;
     RECT  31.932 51.629 34.794 52.051 ;
     RECT  35.928 51.737 35.946 52.051 ;
     RECT  9.144 51.943 9.27 52.052 ;
     RECT  6.732 51.883 8.19 52.061 ;
     RECT  9.18 52.052 9.27 52.079 ;
     RECT  9.18 52.079 9.198 52.277 ;
     RECT  30.78 51.907 30.87 52.313 ;
     RECT  6.804 52.061 8.19 52.321 ;
     RECT  6.804 52.321 8.298 52.439 ;
     RECT  31.932 52.051 35.946 52.519 ;
     RECT  31.608 52.519 35.946 52.781 ;
     RECT  30.852 52.313 30.87 52.825 ;
     RECT  31.608 52.781 34.326 52.825 ;
     RECT  2.304 52.043 5.778 52.861 ;
     RECT  6.804 52.439 6.966 52.861 ;
     RECT  0.54 52.861 0.558 53.117 ;
     RECT  35.352 52.781 35.946 53.131 ;
     RECT  7.815 52.439 8.226 53.159 ;
     RECT  7.815 53.159 8.154 53.249 ;
     RECT  30.852 52.825 34.326 53.257 ;
     RECT  2.304 52.861 6.966 53.365 ;
     RECT  7.815 53.249 8.097 53.365 ;
     RECT  9.144 53.257 9.162 53.429 ;
     RECT  2.304 53.365 8.097 53.519 ;
     RECT  30.78 53.257 34.326 53.557 ;
     RECT  35.352 53.131 35.982 53.557 ;
     RECT  30.78 53.557 35.982 53.597 ;
     RECT  3.672 53.519 8.097 53.699 ;
     RECT  35.352 53.597 35.982 54.091 ;
     RECT  3.672 53.699 7.038 54.329 ;
     RECT  35.352 54.091 36.018 54.329 ;
     RECT  30.78 53.597 34.218 54.379 ;
     RECT  30.78 54.379 34.758 54.437 ;
     RECT  2.304 53.519 2.862 54.481 ;
     RECT  3.672 54.329 5.67 54.481 ;
     RECT  35.892 54.329 36.018 54.509 ;
     RECT  6.66 54.329 7.038 54.859 ;
     RECT  7.815 53.699 8.097 54.859 ;
     RECT  6.66 54.859 8.097 54.905 ;
     RECT  9.684 54.445 9.702 55.049 ;
     RECT  31.068 54.437 34.254 55.139 ;
     RECT  35.892 54.509 35.982 55.139 ;
     RECT  2.304 54.481 5.67 55.147 ;
     RECT  6.66 54.905 7.074 55.147 ;
     RECT  32.115 55.139 34.254 55.387 ;
     RECT  32.115 55.387 34.794 55.531 ;
     RECT  35.928 55.139 35.982 55.553 ;
     RECT  7.815 54.905 8.097 55.561 ;
     RECT  7.815 55.561 8.226 55.831 ;
     RECT  32.115 55.531 34.866 56.011 ;
     RECT  35.928 55.553 35.946 56.011 ;
     RECT  30.888 56.029 30.906 56.191 ;
     RECT  2.304 55.147 7.074 56.203 ;
     RECT  7.815 55.831 8.514 56.203 ;
     RECT  32.115 56.011 35.946 56.335 ;
     RECT  32.076 56.335 35.946 56.347 ;
     RECT  30.78 56.191 30.906 56.399 ;
     RECT  32.076 56.347 35.982 56.533 ;
     RECT  2.304 56.203 8.514 56.569 ;
     RECT  2.304 56.569 8.802 56.641 ;
     RECT  30.924 56.533 35.982 56.717 ;
     RECT  35.388 56.717 35.982 56.759 ;
     RECT  35.928 56.759 35.982 57.019 ;
     RECT  30.924 56.717 34.254 57.029 ;
     RECT  2.304 56.641 8.874 57.181 ;
     RECT  31.824 57.029 34.254 57.299 ;
     RECT  2.304 57.181 9.126 57.371 ;
     RECT  30.852 57.343 30.87 57.451 ;
     RECT  30.78 57.451 30.87 57.479 ;
     RECT  30.78 57.479 30.798 57.569 ;
     RECT  31.86 57.299 34.254 57.677 ;
     RECT  32.076 57.677 34.254 57.685 ;
     RECT  32.076 57.685 34.722 57.691 ;
     RECT  35.928 57.019 36.018 57.691 ;
     RECT  32.076 57.691 36.018 57.713 ;
     RECT  2.304 57.371 8.586 57.749 ;
     RECT  32.076 57.713 35.946 57.947 ;
     RECT  35.352 57.947 35.946 58.019 ;
     RECT  6.588 57.749 8.586 58.109 ;
     RECT  9.468 57.955 9.594 58.109 ;
     RECT  6.768 58.109 8.586 58.145 ;
     RECT  2.304 57.749 5.814 58.315 ;
     RECT  2.268 58.315 5.814 58.415 ;
     RECT  7.815 58.145 8.586 58.649 ;
     RECT  9.396 58.495 9.414 58.649 ;
     RECT  32.076 57.947 34.29 58.649 ;
     RECT  2.304 58.415 5.814 58.657 ;
     RECT  32.076 58.649 34.254 58.657 ;
     RECT  32.04 58.657 34.254 58.801 ;
     RECT  9.108 58.729 9.27 58.829 ;
     RECT  6.768 58.145 6.93 58.891 ;
     RECT  7.815 58.649 8.097 58.891 ;
     RECT  31.824 58.801 34.254 58.919 ;
     RECT  35.892 58.019 35.946 58.987 ;
     RECT  30.78 58.927 30.798 59.027 ;
     RECT  35.892 58.987 35.982 59.027 ;
     RECT  9.108 58.829 9.198 59.099 ;
     RECT  9.108 59.099 9.126 59.189 ;
     RECT  35.892 59.027 35.946 59.189 ;
     RECT  2.304 58.657 5.85 59.269 ;
     RECT  6.768 58.891 8.097 59.269 ;
     RECT  2.304 59.269 8.097 59.323 ;
     RECT  31.968 58.919 34.254 59.467 ;
     RECT  2.268 59.323 8.097 59.531 ;
     RECT  3.888 59.531 8.097 59.575 ;
     RECT  31.968 59.467 34.794 59.611 ;
     RECT  3.888 59.575 8.37 59.645 ;
     RECT  3.96 59.645 8.37 59.701 ;
     RECT  31.968 59.611 34.83 59.845 ;
     RECT  31.932 59.845 34.83 59.999 ;
     RECT  2.268 59.531 2.934 60.385 ;
     RECT  3.96 59.701 8.586 60.385 ;
     RECT  31.968 59.999 34.83 60.421 ;
     RECT  35.928 59.189 35.946 60.421 ;
     RECT  2.268 60.385 8.586 60.539 ;
     RECT  2.268 60.539 6.246 60.575 ;
     RECT  31.968 60.421 35.946 60.611 ;
     RECT  30.78 60.043 30.798 60.691 ;
     RECT  7.128 60.539 8.586 60.781 ;
     RECT  9.684 60.691 9.702 60.809 ;
     RECT  7.128 60.781 8.622 60.845 ;
     RECT  9.252 60.889 9.594 60.989 ;
     RECT  30.78 60.691 30.87 60.989 ;
     RECT  4.284 60.575 6.246 61.321 ;
     RECT  7.128 60.845 8.097 61.321 ;
     RECT  30.852 60.989 30.87 61.349 ;
     RECT  31.968 60.611 35.37 61.349 ;
     RECT  31.968 61.349 34.362 61.357 ;
     RECT  35.352 61.349 35.37 61.435 ;
     RECT  2.304 60.575 3.51 61.501 ;
     RECT  4.284 61.321 8.097 61.501 ;
     RECT  2.304 61.501 8.097 61.517 ;
     RECT  2.304 61.517 5.958 61.529 ;
     RECT  6.804 61.517 8.097 61.619 ;
     RECT  9.576 60.989 9.594 61.619 ;
     RECT  0.396 61.771 0.414 61.915 ;
     RECT  35.352 61.435 35.946 61.915 ;
     RECT  0.216 61.915 0.414 61.949 ;
     RECT  0.216 61.949 0.234 62.045 ;
     RECT  31.608 61.357 34.362 62.069 ;
     RECT  31.86 62.069 34.362 62.189 ;
     RECT  35.352 61.915 35.982 62.251 ;
     RECT  6.912 61.619 8.097 62.275 ;
     RECT  6.912 62.275 8.226 62.311 ;
     RECT  6.912 62.311 8.406 62.401 ;
     RECT  30.78 62.275 30.798 62.437 ;
     RECT  6.912 62.401 8.586 62.465 ;
     RECT  35.352 62.251 36.018 62.477 ;
     RECT  31.968 62.189 34.362 62.509 ;
     RECT  2.304 61.529 5.886 62.545 ;
     RECT  35.928 62.477 36.018 62.573 ;
     RECT  6.948 62.465 8.586 62.609 ;
     RECT  2.304 62.545 6.138 62.671 ;
     RECT  31.968 62.509 34.434 62.671 ;
     RECT  31.968 62.671 34.506 62.807 ;
     RECT  32.115 62.807 34.506 62.923 ;
     RECT  30.78 62.437 30.87 63.149 ;
     RECT  35.928 62.573 35.982 63.319 ;
     RECT  2.304 62.671 6.21 63.391 ;
     RECT  7.236 62.609 8.097 63.391 ;
     RECT  2.304 63.391 8.097 63.629 ;
     RECT  6.48 63.629 8.097 63.661 ;
     RECT  0.252 63.547 0.27 63.773 ;
     RECT  35.928 63.319 36.018 63.773 ;
     RECT  32.115 62.923 34.794 63.823 ;
     RECT  6.48 63.661 8.298 63.931 ;
     RECT  6.48 63.931 8.406 64.049 ;
     RECT  31.932 63.823 34.794 64.049 ;
     RECT  30.78 63.895 30.798 64.093 ;
     RECT  2.304 63.629 5.598 64.219 ;
     RECT  31.932 64.049 34.758 64.253 ;
     RECT  2.268 64.219 5.598 64.435 ;
     RECT  2.268 64.435 5.742 64.625 ;
     RECT  6.48 64.049 8.262 64.625 ;
     RECT  30.78 64.093 30.87 64.669 ;
     RECT  35.928 63.773 35.982 64.696 ;
     RECT  30.78 64.669 30.978 64.705 ;
     RECT  31.932 64.253 34.326 64.705 ;
     RECT  10.515 37.931 10.797 64.741 ;
     RECT  10.515 64.741 10.818 64.859 ;
     RECT  30.78 64.705 34.326 64.859 ;
     RECT  2.304 64.625 5.742 64.867 ;
     RECT  35.928 64.696 36.018 64.891 ;
     RECT  30.78 64.859 30.978 64.967 ;
     RECT  31.932 64.859 34.326 65.209 ;
     RECT  31.932 65.209 34.758 65.227 ;
     RECT  35.928 64.891 36.054 65.227 ;
     RECT  31.932 65.227 36.054 65.309 ;
     RECT  2.304 64.867 6.102 65.371 ;
     RECT  6.876 64.625 8.262 65.371 ;
     RECT  2.268 65.371 8.262 65.435 ;
     RECT  31.932 65.309 35.946 65.507 ;
     RECT  2.304 65.435 8.262 65.821 ;
     RECT  0.216 65.851 0.234 65.981 ;
     RECT  2.304 65.821 8.622 66.011 ;
     RECT  2.304 66.011 8.097 66.077 ;
     RECT  31.932 65.507 34.29 66.119 ;
     RECT  30.78 64.967 30.798 66.181 ;
     RECT  32.115 66.119 34.29 66.353 ;
     RECT  35.856 65.507 35.946 66.379 ;
     RECT  10.515 64.859 10.797 66.451 ;
     RECT  30.78 66.181 30.87 66.479 ;
     RECT  32.115 66.353 34.254 66.479 ;
     RECT  21.315 2.413 21.597 66.487 ;
     RECT  30.78 66.479 30.798 66.587 ;
     RECT  10.515 66.451 10.926 66.659 ;
     RECT  35.856 66.379 36.018 66.667 ;
     RECT  21.096 66.487 21.597 66.785 ;
     RECT  6.804 66.077 8.097 66.829 ;
     RECT  6.804 66.829 8.37 66.857 ;
     RECT  2.304 66.077 6.03 66.901 ;
     RECT  6.804 66.857 6.894 66.901 ;
     RECT  7.815 66.857 8.37 66.901 ;
     RECT  2.304 66.901 6.894 67.019 ;
     RECT  2.304 67.019 6.498 67.055 ;
     RECT  35.856 66.667 36.126 67.091 ;
     RECT  7.815 66.901 8.91 67.289 ;
     RECT  35.856 67.091 36.018 67.339 ;
     RECT  35.352 67.339 36.018 67.433 ;
     RECT  30.852 67.297 30.87 67.441 ;
     RECT  32.115 66.479 34.218 67.531 ;
     RECT  35.352 67.433 35.946 67.531 ;
     RECT  3.744 67.055 6.498 67.559 ;
     RECT  30.852 67.441 30.978 67.603 ;
     RECT  30.816 67.603 30.978 67.631 ;
     RECT  30.816 67.631 30.942 67.703 ;
     RECT  32.076 67.531 35.946 67.709 ;
     RECT  30.816 67.703 30.87 67.711 ;
     RECT  7.815 67.289 8.298 67.739 ;
     RECT  30.78 67.711 30.87 67.739 ;
     RECT  32.076 67.709 35.37 67.981 ;
     RECT  2.304 67.055 2.718 68.155 ;
     RECT  32.04 67.981 35.37 68.189 ;
     RECT  3.744 67.559 6.426 68.341 ;
     RECT  7.815 67.739 8.097 68.341 ;
     RECT  9.144 68.251 9.162 68.369 ;
     RECT  2.304 68.155 2.754 68.377 ;
     RECT  3.744 68.341 6.75 68.377 ;
     RECT  2.304 68.377 6.75 68.381 ;
     RECT  32.04 68.189 34.794 68.405 ;
     RECT  2.304 68.381 6.714 68.525 ;
     RECT  32.04 68.405 34.758 68.647 ;
     RECT  30.78 67.739 30.798 68.683 ;
     RECT  30.78 68.683 30.834 68.783 ;
     RECT  2.304 68.525 6.57 68.909 ;
     RECT  31.68 68.647 34.758 68.909 ;
     RECT  0.252 68.827 0.27 68.957 ;
     RECT  6.552 68.909 6.57 68.981 ;
     RECT  2.304 68.909 5.742 69.163 ;
     RECT  31.932 68.909 34.758 69.163 ;
     RECT  2.268 69.163 5.742 69.215 ;
     RECT  31.932 69.163 34.866 69.251 ;
     RECT  7.56 68.341 8.097 69.259 ;
     RECT  6.66 69.331 6.678 69.403 ;
     RECT  7.488 69.259 8.097 69.403 ;
     RECT  31.932 69.251 34.254 69.521 ;
     RECT  6.66 69.403 8.097 69.529 ;
     RECT  9 69.457 9.018 69.529 ;
     RECT  6.66 69.529 9.018 69.565 ;
     RECT  35.928 68.635 35.946 69.643 ;
     RECT  6.66 69.565 9.09 69.791 ;
     RECT  30.78 68.783 30.798 69.835 ;
     RECT  31.932 69.521 33.966 69.835 ;
     RECT  30.78 69.835 33.966 69.989 ;
     RECT  3.672 69.215 5.742 70.025 ;
     RECT  2.304 69.215 2.934 70.097 ;
     RECT  2.304 70.097 2.862 70.123 ;
     RECT  3.78 70.025 5.742 70.141 ;
     RECT  6.66 69.791 8.19 70.141 ;
     RECT  2.268 70.123 2.862 70.169 ;
     RECT  3.78 70.141 8.19 70.259 ;
     RECT  9.108 70.141 9.126 70.339 ;
     RECT  31.788 69.989 33.966 70.375 ;
     RECT  9.108 70.339 9.234 70.529 ;
     RECT  31.788 70.375 34.326 70.529 ;
     RECT  35.352 69.643 35.946 70.603 ;
     RECT  9.216 70.529 9.234 70.637 ;
     RECT  30.78 69.989 31.014 70.637 ;
     RECT  30.78 70.637 30.906 70.673 ;
     RECT  3.78 70.259 8.097 70.871 ;
     RECT  3.78 70.871 6.966 70.915 ;
     RECT  2.304 70.169 2.862 70.951 ;
     RECT  3.6 70.915 6.966 70.951 ;
     RECT  10.515 66.659 10.797 70.951 ;
     RECT  10.515 70.951 10.854 71.069 ;
     RECT  31.86 70.529 34.326 71.131 ;
     RECT  35.352 70.603 35.982 71.131 ;
     RECT  31.86 71.131 35.982 71.141 ;
     RECT  31.932 71.141 35.982 71.177 ;
     RECT  2.304 70.951 6.966 71.213 ;
     RECT  30.78 70.673 30.834 71.249 ;
     RECT  30.78 71.249 30.798 71.519 ;
     RECT  35.352 71.177 35.982 71.609 ;
     RECT  7.815 70.871 8.097 71.761 ;
     RECT  2.304 71.213 6.57 71.933 ;
     RECT  4.392 71.933 6.57 71.995 ;
     RECT  35.928 71.609 35.982 72.023 ;
     RECT  2.304 71.933 3.654 72.185 ;
     RECT  30.852 71.995 30.87 72.221 ;
     RECT  4.392 71.995 6.858 72.229 ;
     RECT  7.596 71.761 8.097 72.229 ;
     RECT  31.932 71.177 34.362 72.283 ;
     RECT  31.932 72.283 34.758 72.301 ;
     RECT  0.216 72.187 0.234 72.317 ;
     RECT  4.392 72.229 8.097 72.329 ;
     RECT  9.756 72.229 9.774 72.329 ;
     RECT  29.415 27.509 29.697 72.661 ;
     RECT  31.788 72.301 34.758 72.769 ;
     RECT  2.34 72.185 3.654 72.841 ;
     RECT  4.392 72.329 6.462 72.841 ;
     RECT  31.392 72.769 34.758 72.869 ;
     RECT  35.928 72.023 35.946 72.907 ;
     RECT  0.252 72.811 0.27 72.941 ;
     RECT  2.34 72.841 6.462 72.959 ;
     RECT  35.352 72.907 35.946 72.959 ;
     RECT  31.392 72.869 34.29 72.995 ;
     RECT  7.2 72.329 8.097 73.075 ;
     RECT  2.34 72.959 5.994 73.099 ;
     RECT  35.928 72.959 35.946 73.099 ;
     RECT  29.415 72.661 29.754 73.103 ;
     RECT  7.2 73.075 8.19 73.229 ;
     RECT  10.515 71.069 10.797 73.237 ;
     RECT  35.928 73.099 35.982 73.243 ;
     RECT  30.78 73.039 30.87 73.337 ;
     RECT  35.928 73.243 36.018 73.345 ;
     RECT  10.515 73.237 10.926 73.409 ;
     RECT  7.815 73.229 8.19 73.507 ;
     RECT  35.928 73.345 36.054 73.613 ;
     RECT  2.304 73.099 5.994 73.877 ;
     RECT  35.928 73.613 36.018 73.877 ;
     RECT  31.932 72.995 34.29 73.885 ;
     RECT  6.948 73.615 6.966 73.921 ;
     RECT  7.815 73.507 8.442 73.921 ;
     RECT  6.696 73.921 6.966 74.039 ;
     RECT  31.752 73.885 34.29 74.039 ;
     RECT  6.804 74.039 6.966 74.047 ;
     RECT  7.815 73.921 8.514 74.309 ;
     RECT  10.515 73.409 10.797 74.317 ;
     RECT  30.78 73.337 30.798 74.317 ;
     RECT  30.78 74.317 30.87 74.417 ;
     RECT  10.515 74.317 10.926 74.489 ;
     RECT  35.928 73.877 35.946 74.539 ;
     RECT  2.304 73.877 5.778 74.623 ;
     RECT  6.804 74.047 7.074 74.695 ;
     RECT  7.815 74.309 8.262 74.695 ;
     RECT  30.78 74.417 30.798 74.849 ;
     RECT  35.892 74.539 35.946 74.875 ;
     RECT  6.804 74.695 8.262 75.001 ;
     RECT  31.968 74.039 34.29 75.001 ;
     RECT  35.892 74.875 35.982 75.067 ;
     RECT  31.824 75.001 34.722 75.091 ;
     RECT  35.892 75.067 36.018 75.119 ;
     RECT  2.304 74.623 5.886 75.127 ;
     RECT  6.696 75.001 8.262 75.127 ;
     RECT  2.304 75.127 8.262 75.191 ;
     RECT  0.252 75.067 0.27 75.197 ;
     RECT  35.928 75.119 36.018 75.227 ;
     RECT  31.644 75.091 34.722 75.691 ;
     RECT  31.644 75.691 34.758 75.767 ;
     RECT  30.852 75.703 30.87 75.803 ;
     RECT  35.928 75.227 35.982 75.883 ;
     RECT  2.304 75.191 8.097 76.081 ;
     RECT  2.304 76.081 8.802 76.199 ;
     RECT  35.352 75.883 35.982 76.199 ;
     RECT  0.216 76.171 0.234 76.301 ;
     RECT  30.78 76.081 30.798 76.307 ;
     RECT  31.644 75.767 34.29 76.504 ;
     RECT  31.644 76.504 34.758 76.541 ;
     RECT  7.02 76.199 8.802 76.621 ;
     RECT  2.304 76.199 6.174 76.699 ;
     RECT  31.644 76.541 34.29 76.739 ;
     RECT  2.268 76.699 6.174 76.811 ;
     RECT  2.268 76.811 5.634 76.847 ;
     RECT  7.02 76.621 8.838 76.939 ;
     RECT  6.408 76.939 8.838 77.153 ;
     RECT  6.408 77.153 6.93 77.315 ;
     RECT  7.815 77.153 8.838 77.315 ;
     RECT  32.115 76.739 34.254 77.515 ;
     RECT  2.304 76.847 5.634 77.701 ;
     RECT  6.408 77.315 6.822 77.701 ;
     RECT  9.036 77.395 9.054 77.899 ;
     RECT  32.115 77.515 34.794 77.935 ;
     RECT  35.928 76.199 35.982 77.935 ;
     RECT  0.252 77.179 0.27 78.029 ;
     RECT  35.928 77.935 36.018 78.029 ;
     RECT  2.304 77.701 6.822 78.061 ;
     RECT  7.815 77.315 8.097 78.061 ;
     RECT  9.036 77.899 9.09 78.089 ;
     RECT  31.788 77.935 34.794 78.125 ;
     RECT  2.304 78.061 8.097 78.139 ;
     RECT  35.928 78.029 35.982 78.269 ;
     RECT  2.304 78.139 8.37 78.331 ;
     RECT  31.932 78.125 34.794 78.331 ;
     RECT  2.268 78.331 8.37 78.395 ;
     RECT  2.268 78.395 8.097 78.467 ;
     RECT  2.304 78.467 8.097 78.629 ;
     RECT  9.288 78.241 9.45 78.665 ;
     RECT  31.932 78.331 34.902 78.899 ;
     RECT  30.852 78.709 30.87 78.907 ;
     RECT  30.78 78.907 30.87 79.079 ;
     RECT  32.004 78.899 34.902 79.147 ;
     RECT  35.928 78.269 35.946 79.147 ;
     RECT  32.004 79.147 35.946 79.169 ;
     RECT  6.984 78.629 8.097 79.321 ;
     RECT  8.856 79.249 8.874 79.321 ;
     RECT  6.984 79.321 8.874 79.349 ;
     RECT  2.304 78.629 6.246 79.447 ;
     RECT  6.984 79.349 8.802 79.447 ;
     RECT  32.076 79.169 35.946 79.511 ;
     RECT  30.78 79.079 30.798 79.583 ;
     RECT  2.304 79.447 8.802 79.619 ;
     RECT  34.74 79.511 35.946 79.661 ;
     RECT  2.304 79.619 8.73 79.709 ;
     RECT  34.776 79.661 35.946 79.819 ;
     RECT  2.304 79.709 3.15 79.963 ;
     RECT  7.815 79.709 8.73 79.979 ;
     RECT  2.268 79.963 3.15 80.087 ;
     RECT  32.076 79.511 33.822 80.095 ;
     RECT  34.776 79.819 35.982 80.159 ;
     RECT  30.852 79.951 30.87 80.357 ;
     RECT  31.932 80.095 33.822 80.401 ;
     RECT  34.776 80.159 35.37 80.401 ;
     RECT  2.304 80.087 3.15 80.671 ;
     RECT  3.96 79.709 7.002 80.671 ;
     RECT  2.304 80.671 3.222 80.761 ;
     RECT  3.96 80.671 7.074 80.761 ;
     RECT  2.304 80.761 7.074 80.869 ;
     RECT  7.815 79.979 8.298 80.869 ;
     RECT  2.304 80.869 8.298 80.905 ;
     RECT  2.304 80.905 8.406 81.239 ;
     RECT  31.932 80.401 35.37 81.259 ;
     RECT  31.932 81.259 35.406 81.329 ;
     RECT  34.812 81.329 35.406 81.451 ;
     RECT  31.932 81.329 34.074 81.481 ;
     RECT  31.86 81.481 34.074 81.599 ;
     RECT  30.78 80.365 30.798 81.643 ;
     RECT  2.304 81.239 8.334 81.779 ;
     RECT  34.812 81.451 35.442 81.913 ;
     RECT  6.804 81.779 8.334 82.021 ;
     RECT  6.804 82.021 8.838 82.139 ;
     RECT  31.968 81.599 34.074 82.267 ;
     RECT  34.812 81.913 35.946 82.267 ;
     RECT  30.78 81.643 30.87 82.319 ;
     RECT  2.304 81.779 5.958 82.561 ;
     RECT  6.804 82.139 8.262 82.561 ;
     RECT  2.304 82.561 8.262 82.921 ;
     RECT  31.968 82.267 35.946 82.949 ;
     RECT  30.852 82.319 30.87 83.057 ;
     RECT  2.304 82.921 8.37 83.083 ;
     RECT  2.268 83.083 8.37 83.129 ;
     RECT  32.076 82.949 35.946 83.129 ;
     RECT  9.396 83.101 9.414 83.219 ;
     RECT  2.268 83.129 8.154 83.255 ;
     RECT  32.076 83.129 35.37 83.255 ;
     RECT  30.78 83.101 30.798 83.489 ;
     RECT  32.115 83.255 35.37 83.899 ;
     RECT  2.304 83.255 8.097 84.001 ;
     RECT  2.304 84.001 8.55 84.029 ;
     RECT  32.115 83.899 35.946 84.037 ;
     RECT  32.004 84.037 35.946 84.043 ;
     RECT  3.78 84.029 8.55 84.335 ;
     RECT  32.004 84.043 35.982 84.479 ;
     RECT  32.004 84.479 35.946 84.613 ;
     RECT  3.924 84.335 8.55 84.713 ;
     RECT  31.932 84.613 35.946 84.749 ;
     RECT  2.304 84.029 2.862 84.811 ;
     RECT  31.932 84.749 34.254 84.847 ;
     RECT  2.304 84.811 3.186 85.351 ;
     RECT  3.924 84.713 8.478 85.351 ;
     RECT  31.896 84.847 34.254 85.387 ;
     RECT  31.356 85.387 34.254 85.675 ;
     RECT  35.316 84.749 35.946 85.675 ;
     RECT  31.356 85.675 35.946 85.721 ;
     RECT  2.304 85.351 8.478 85.765 ;
     RECT  2.304 85.765 8.55 85.927 ;
     RECT  2.304 85.927 8.766 85.955 ;
     RECT  31.356 85.721 34.506 85.963 ;
     RECT  35.316 85.721 35.946 86.011 ;
     RECT  2.415 85.955 8.766 86.099 ;
     RECT  31.068 85.963 34.506 86.233 ;
     RECT  30.852 86.233 34.506 86.341 ;
     RECT  10.515 74.489 10.797 86.503 ;
     RECT  0.252 85.867 0.27 86.525 ;
     RECT  30.78 86.341 34.506 86.539 ;
     RECT  35.316 86.011 35.982 86.539 ;
     RECT  10.515 86.503 10.926 86.603 ;
     RECT  2.415 86.099 8.262 86.683 ;
     RECT  2.304 86.683 8.262 86.729 ;
     RECT  30.78 86.539 35.982 86.729 ;
     RECT  35.928 86.729 35.982 86.827 ;
     RECT  30.78 86.729 30.798 86.909 ;
     RECT  10.515 86.603 10.854 87.413 ;
     RECT  32.004 86.729 34.794 87.511 ;
     RECT  31.968 87.511 34.794 87.619 ;
     RECT  31.932 87.619 34.794 87.835 ;
     RECT  7.056 86.729 8.262 87.931 ;
     RECT  6.804 87.931 8.262 87.961 ;
     RECT  6.804 87.961 9.378 87.965 ;
     RECT  2.304 86.729 5.958 87.979 ;
     RECT  7.596 87.965 9.378 88.079 ;
     RECT  31.932 87.835 34.83 88.171 ;
     RECT  35.928 86.827 36.018 88.171 ;
     RECT  6.804 87.965 6.822 88.231 ;
     RECT  6.732 88.231 6.822 88.349 ;
     RECT  2.268 87.979 5.958 88.385 ;
     RECT  2.304 88.385 5.958 88.393 ;
     RECT  31.932 88.171 36.018 88.465 ;
     RECT  10.515 87.413 10.797 88.501 ;
     RECT  10.515 88.501 10.926 88.619 ;
     RECT  2.304 88.393 6.678 88.655 ;
     RECT  2.304 88.655 2.79 88.691 ;
     RECT  5.115 88.655 6.678 88.727 ;
     RECT  5.115 88.727 5.886 88.763 ;
     RECT  31.896 88.465 36.018 88.771 ;
     RECT  6.624 88.727 6.678 88.799 ;
     RECT  7.815 88.079 8.622 88.889 ;
     RECT  9.468 88.735 9.486 88.889 ;
     RECT  31.464 88.771 36.018 88.889 ;
     RECT  31.464 88.889 34.506 88.897 ;
     RECT  2.34 88.691 2.79 88.925 ;
     RECT  6.66 88.799 6.678 89.033 ;
     RECT  3.6 88.655 4.266 89.159 ;
     RECT  5.115 88.763 5.706 89.159 ;
     RECT  31.392 88.897 34.506 89.159 ;
     RECT  35.352 88.889 36.018 89.159 ;
     RECT  3.6 89.159 4.086 89.195 ;
     RECT  32.115 89.159 34.506 89.339 ;
     RECT  9.576 89.041 9.594 89.429 ;
     RECT  32.115 89.339 34.434 89.609 ;
     RECT  35.388 89.159 36.018 89.699 ;
     RECT  33.408 89.609 34.434 89.735 ;
     RECT  35.928 89.699 36.018 89.879 ;
     RECT  33.948 89.735 34.434 89.969 ;
     RECT  35.928 89.879 35.946 90.239 ;
     RECT  33.948 89.969 34.398 90.275 ;
     RECT  34.38 90.275 34.398 90.419 ;
     RECT  2.415 88.925 2.697 90.467 ;
     RECT  5.115 89.159 5.397 90.467 ;
     RECT  7.815 88.889 8.097 90.467 ;
     RECT  10.515 88.619 10.797 90.467 ;
     RECT  13.215 2.413 13.497 90.467 ;
     RECT  15.915 2.413 16.197 90.467 ;
     RECT  18.615 2.413 18.897 90.467 ;
     RECT  21.315 66.785 21.597 90.467 ;
     RECT  24.015 2.413 24.297 90.467 ;
     RECT  26.715 2.413 26.997 90.467 ;
     RECT  29.415 73.103 29.697 90.467 ;
     RECT  32.115 89.609 32.397 90.467 ;
     RECT  2.415 90.467 2.505 90.737 ;
     RECT  5.115 90.467 5.205 90.737 ;
     RECT  7.815 90.467 7.905 90.737 ;
     RECT  10.515 90.467 10.605 90.737 ;
     RECT  13.215 90.467 13.305 90.737 ;
     RECT  15.915 90.467 16.005 90.737 ;
     RECT  18.615 90.467 18.705 90.737 ;
     RECT  21.315 90.467 21.405 90.737 ;
     RECT  24.015 90.467 24.105 90.737 ;
     RECT  26.715 90.467 26.805 90.737 ;
     RECT  29.415 90.467 29.505 90.737 ;
     RECT  32.115 90.467 32.205 90.737 ;
     RECT  18.18 92.748 18.198 92.765 ;
    LAYER M4 ;
     RECT  0.156 4.416 2.408 88.536 ;
     RECT  2.408 2.148 2.512 90.732 ;
     RECT  2.512 2.418 2.704 90.462 ;
     RECT  2.704 19.584 2.729 21.816 ;
     RECT  2.704 65.952 2.729 70.968 ;
     RECT  2.704 4.416 2.765 4.44 ;
     RECT  2.729 19.92 2.765 21.816 ;
     RECT  2.704 27.744 2.765 29.016 ;
     RECT  2.704 35.952 2.765 43.608 ;
     RECT  2.704 63.552 2.765 64.776 ;
     RECT  2.729 68.16 2.765 70.968 ;
     RECT  2.704 75.12 2.765 78.696 ;
     RECT  2.704 9.312 2.801 9.432 ;
     RECT  2.704 13.776 2.801 14.424 ;
     RECT  2.765 19.92 2.801 21.48 ;
     RECT  2.704 45.552 2.801 49.896 ;
     RECT  2.704 55.728 2.801 62.472 ;
     RECT  2.765 35.952 2.837 43.368 ;
     RECT  2.704 72 2.837 74.088 ;
     RECT  2.704 85.392 2.837 87.528 ;
     RECT  2.801 56.88 2.867 62.472 ;
     RECT  2.704 6.048 2.873 6.072 ;
     RECT  2.704 16.32 2.873 17.64 ;
     RECT  2.704 23.904 2.873 26.088 ;
     RECT  2.704 30.144 2.873 30.84 ;
     RECT  2.704 34.752 2.873 34.776 ;
     RECT  2.801 46.512 2.873 49.896 ;
     RECT  2.704 54.096 2.873 54.12 ;
     RECT  2.704 7.968 2.909 7.992 ;
     RECT  2.873 47.28 2.909 49.896 ;
     RECT  2.867 60.672 2.909 62.472 ;
     RECT  2.704 11.184 2.981 11.208 ;
     RECT  2.837 41.136 2.981 43.368 ;
     RECT  2.837 35.952 3.017 39.816 ;
     RECT  2.765 68.928 3.017 69.624 ;
     RECT  2.765 75.12 3.017 78.648 ;
     RECT  2.704 80.304 3.017 82.296 ;
     RECT  3.017 35.952 3.089 36.84 ;
     RECT  2.981 41.76 3.089 43.368 ;
     RECT  2.873 16.368 3.125 17.64 ;
     RECT  2.801 55.728 3.197 55.752 ;
     RECT  2.873 23.904 3.233 24.456 ;
     RECT  2.765 63.552 3.233 63.576 ;
     RECT  2.837 85.968 3.233 87.528 ;
     RECT  3.125 16.8 3.269 17.64 ;
     RECT  2.909 60.672 3.269 61.944 ;
     RECT  2.873 25.584 3.305 26.088 ;
     RECT  3.233 24.432 3.341 24.456 ;
     RECT  2.837 72 3.341 73.848 ;
     RECT  2.909 47.28 3.443 47.304 ;
     RECT  3.017 75.12 3.443 76.968 ;
     RECT  3.233 86.016 3.443 87.528 ;
     RECT  3.017 38.16 3.457 39.816 ;
     RECT  3.443 86.016 3.521 86.616 ;
     RECT  2.801 13.776 3.539 13.8 ;
     RECT  3.269 16.8 3.539 17.112 ;
     RECT  2.704 33.408 3.539 33.432 ;
     RECT  3.089 35.952 3.539 35.976 ;
     RECT  2.765 27.744 3.635 28.296 ;
     RECT  2.704 88.848 3.701 88.968 ;
     RECT  3.089 42.72 3.769 43.368 ;
     RECT  2.704 12.72 3.805 12.744 ;
     RECT  2.867 56.88 3.836 59.304 ;
     RECT  3.841 46.176 3.877 46.2 ;
     RECT  3.269 60.672 3.877 61.656 ;
     RECT  3.635 27.744 3.884 27.768 ;
     RECT  3.877 53.952 3.884 53.976 ;
     RECT  3.884 27.216 3.913 27.768 ;
     RECT  3.836 44.88 3.923 44.904 ;
     RECT  3.836 56.88 3.949 59.64 ;
     RECT  3.877 60.624 3.949 61.656 ;
     RECT  2.765 70.944 3.949 70.968 ;
     RECT  3.341 72 3.949 72.408 ;
     RECT  2.873 30.816 3.952 30.84 ;
     RECT  2.801 19.92 3.953 20.76 ;
     RECT  3.952 30.816 3.953 30.888 ;
     RECT  3.953 20.736 3.971 20.76 ;
     RECT  3.877 22.128 3.971 22.152 ;
     RECT  3.805 23.136 3.971 23.352 ;
     RECT  3.443 75.552 3.971 76.968 ;
     RECT  2.765 64.752 3.973 64.776 ;
     RECT  2.729 65.952 3.973 66.648 ;
     RECT  3.949 56.88 3.98 61.656 ;
     RECT  3.841 24.48 4.019 24.504 ;
     RECT  3.305 25.584 4.019 25.608 ;
     RECT  3.913 26.64 4.019 27.768 ;
     RECT  3.973 65.952 4.019 67.56 ;
     RECT  3.805 12.48 4.021 12.744 ;
     RECT  3.877 45.984 4.021 46.2 ;
     RECT  3.884 53.568 4.021 53.976 ;
     RECT  3.697 55.056 4.021 55.32 ;
     RECT  3.949 70.944 4.021 72.408 ;
     RECT  3.017 80.928 4.021 82.296 ;
     RECT  4.021 80.784 4.057 82.296 ;
     RECT  2.704 83.76 4.057 83.784 ;
     RECT  4.019 67.536 4.061 67.56 ;
     RECT  4.021 53.568 4.067 55.32 ;
     RECT  4.021 12.48 4.076 13.608 ;
     RECT  2.909 48.912 4.076 49.896 ;
     RECT  3.971 75.792 4.097 76.968 ;
     RECT  3.701 88.944 4.097 88.968 ;
     RECT  4.021 45.024 4.105 46.2 ;
     RECT  4.067 54.864 4.108 55.32 ;
     RECT  4.076 48.816 4.117 49.896 ;
     RECT  3.98 51.504 4.117 51.528 ;
     RECT  3.953 30.864 4.133 30.888 ;
     RECT  4.124 29.76 4.165 29.784 ;
     RECT  3.985 32.448 4.165 32.856 ;
     RECT  3.98 56.448 4.268 61.656 ;
     RECT  4.117 7.92 4.273 7.944 ;
     RECT  4.019 26.64 4.309 26.664 ;
     RECT  4.057 80.784 4.357 84.36 ;
     RECT  3.769 42.72 4.417 43.896 ;
     RECT  4.108 55.056 4.453 55.32 ;
     RECT  4.268 56.4 4.453 61.656 ;
     RECT  3.017 78.624 4.453 78.648 ;
     RECT  4.417 42.576 4.489 43.896 ;
     RECT  4.453 78.528 4.501 78.648 ;
     RECT  4.453 79.776 4.501 79.8 ;
     RECT  4.357 6.24 4.508 6.264 ;
     RECT  2.801 9.408 4.508 9.432 ;
     RECT  4.273 7.92 4.517 7.992 ;
     RECT  4.508 9.408 4.517 10.008 ;
     RECT  4.117 48.816 4.525 51.528 ;
     RECT  4.508 6.192 4.549 6.264 ;
     RECT  4.517 7.92 4.549 10.008 ;
     RECT  4.417 19.248 4.556 19.272 ;
     RECT  4.076 11.904 4.561 13.608 ;
     RECT  3.539 17.088 4.597 17.112 ;
     RECT  4.561 87.12 4.604 87.144 ;
     RECT  4.357 80.784 4.633 84.936 ;
     RECT  3.521 86.016 4.633 86.04 ;
     RECT  4.105 45.984 4.669 46.2 ;
     RECT  3.973 64.752 4.669 64.92 ;
     RECT  4.165 29.04 4.7 29.784 ;
     RECT  4.561 11.904 4.741 14.232 ;
     RECT  4.525 48.816 4.741 52.488 ;
     RECT  4.7 63.168 4.777 63.192 ;
     RECT  3.017 69.504 4.813 69.624 ;
     RECT  4.021 70.704 4.813 72.408 ;
     RECT  3.457 38.16 4.849 38.712 ;
     RECT  4.021 39.888 4.849 39.912 ;
     RECT  4.489 42.336 4.94 43.896 ;
     RECT  4.94 42.336 4.949 44.328 ;
     RECT  4.849 38.16 4.981 39.912 ;
     RECT  4.669 45.984 4.981 46.92 ;
     RECT  4.453 55.056 4.981 61.656 ;
     RECT  4.777 62.64 4.981 63.192 ;
     RECT  4.813 69.504 4.981 72.408 ;
     RECT  3.341 73.488 4.981 73.848 ;
     RECT  4.097 75.792 4.981 76.776 ;
     RECT  4.7 28.896 4.993 29.784 ;
     RECT  4.981 69.504 4.993 73.848 ;
     RECT  3.985 4.512 5.108 4.536 ;
     RECT  4.549 6.192 5.108 10.008 ;
     RECT  4.741 11.376 5.108 14.232 ;
     RECT  4.597 16.272 5.108 17.112 ;
     RECT  4.556 18.768 5.108 19.272 ;
     RECT  4.597 20.784 5.108 20.808 ;
     RECT  3.971 23.136 5.108 23.208 ;
     RECT  4.309 25.632 5.108 26.664 ;
     RECT  4.019 27.744 5.108 27.768 ;
     RECT  4.993 28.896 5.108 30.36 ;
     RECT  4.165 31.632 5.108 32.856 ;
     RECT  5.101 34.656 5.108 34.68 ;
     RECT  4.129 36.048 5.108 36.072 ;
     RECT  4.981 38.16 5.108 40.728 ;
     RECT  4.949 42.048 5.108 44.328 ;
     RECT  4.981 45.984 5.108 47.16 ;
     RECT  4.741 48.48 5.108 52.488 ;
     RECT  4.067 53.568 5.108 53.592 ;
     RECT  4.981 55.056 5.108 63.192 ;
     RECT  4.669 64.368 5.108 64.92 ;
     RECT  4.019 65.952 5.108 66.264 ;
     RECT  4.597 68.352 5.108 68.376 ;
     RECT  4.993 69.504 5.108 74.088 ;
     RECT  4.981 75.168 5.108 76.776 ;
     RECT  4.501 78.528 5.108 79.8 ;
     RECT  4.633 80.784 5.108 86.04 ;
     RECT  4.604 87.12 5.108 87.816 ;
     RECT  5.108 2.148 5.212 90.732 ;
     RECT  5.212 2.418 5.404 90.462 ;
     RECT  5.404 79.2 5.555 82.152 ;
     RECT  5.404 83.232 5.555 84.984 ;
     RECT  5.404 31.344 5.644 31.8 ;
     RECT  5.644 31.344 5.653 31.368 ;
     RECT  5.404 9.648 5.681 9.672 ;
     RECT  5.404 56.4 5.681 61.752 ;
     RECT  5.404 69.84 5.681 70.008 ;
     RECT  5.404 10.8 5.699 13.08 ;
     RECT  5.404 14.544 5.699 17.832 ;
     RECT  5.404 18.816 5.699 20.52 ;
     RECT  5.404 53.472 5.699 53.496 ;
     RECT  5.404 54.72 5.699 54.744 ;
     RECT  5.681 56.4 5.699 61.656 ;
     RECT  5.404 71.76 5.699 74.088 ;
     RECT  5.699 14.544 5.753 14.904 ;
     RECT  5.699 19.248 5.753 19.416 ;
     RECT  5.555 83.232 5.753 83.256 ;
     RECT  5.404 87.12 5.753 87.144 ;
     RECT  5.404 7.968 5.789 7.992 ;
     RECT  5.404 51.84 5.789 52.488 ;
     RECT  5.699 59.232 5.789 61.656 ;
     RECT  5.404 22.176 5.795 23.544 ;
     RECT  5.404 32.832 5.825 34.68 ;
     RECT  5.795 23.136 5.861 23.544 ;
     RECT  5.789 51.84 5.861 52.056 ;
     RECT  5.555 79.2 5.891 79.848 ;
     RECT  5.404 28.368 5.933 28.392 ;
     RECT  5.699 13.056 5.939 13.08 ;
     RECT  5.404 63.216 5.987 67.368 ;
     RECT  5.404 42.72 6.041 47.16 ;
     RECT  5.789 59.232 6.041 61.512 ;
     RECT  5.404 75.168 6.041 78.168 ;
     RECT  6.041 75.216 6.083 78.168 ;
     RECT  5.699 71.76 6.113 72.744 ;
     RECT  5.699 10.8 6.121 12.024 ;
     RECT  5.404 37.488 6.131 38.04 ;
     RECT  5.404 41.04 6.131 41.64 ;
     RECT  6.041 60.816 6.131 61.512 ;
     RECT  5.987 63.216 6.131 64.776 ;
     RECT  6.131 60.816 6.221 60.936 ;
     RECT  6.121 11.28 6.275 12.024 ;
     RECT  5.699 56.4 6.275 57.576 ;
     RECT  5.699 16.512 6.323 17.832 ;
     RECT  5.404 49.584 6.323 49.608 ;
     RECT  5.891 79.2 6.323 79.272 ;
     RECT  5.699 20.496 6.329 20.52 ;
     RECT  6.083 75.216 6.371 75.768 ;
     RECT  5.404 68.352 6.38 68.52 ;
     RECT  5.404 39.456 6.383 39.48 ;
     RECT  5.404 24.528 6.419 24.744 ;
     RECT  6.131 37.488 6.421 37.512 ;
     RECT  6.38 68.352 6.421 68.808 ;
     RECT  5.861 23.136 6.437 23.304 ;
     RECT  6.275 57.552 6.437 57.576 ;
     RECT  6.371 75.552 6.437 75.576 ;
     RECT  6.083 76.944 6.437 78.168 ;
     RECT  6.421 37.008 6.467 37.512 ;
     RECT  6.041 42.72 6.467 45.144 ;
     RECT  5.404 30.336 6.469 30.36 ;
     RECT  6.467 42.72 6.541 43.32 ;
     RECT  6.275 11.28 6.545 11.784 ;
     RECT  6.469 34.992 6.563 35.016 ;
     RECT  6.397 9.6 6.581 9.624 ;
     RECT  6.113 71.76 6.581 72.456 ;
     RECT  5.555 80.928 6.581 82.152 ;
     RECT  6.469 30 6.613 30.36 ;
     RECT  5.555 84.288 6.653 84.984 ;
     RECT  5.825 33.072 6.659 33.768 ;
     RECT  6.613 30 6.7 30.984 ;
     RECT  6.437 23.136 6.707 23.16 ;
     RECT  6.421 68.352 6.725 69.576 ;
     RECT  6.7 30 6.733 30.84 ;
     RECT  6.469 55.296 6.755 55.32 ;
     RECT  6.131 63.504 6.755 64.776 ;
     RECT  5.404 5.616 6.757 5.64 ;
     RECT  6.716 7.056 6.757 7.08 ;
     RECT  6.725 68.352 6.761 68.376 ;
     RECT  5.753 14.544 6.793 14.568 ;
     RECT  6.755 63.6 6.796 64.776 ;
     RECT  6.757 5.616 6.803 7.08 ;
     RECT  6.469 8.4 6.803 8.424 ;
     RECT  6.716 35.568 6.803 35.592 ;
     RECT  6.716 40.704 6.803 40.728 ;
     RECT  5.404 48.24 6.829 48.456 ;
     RECT  5.861 52.032 6.829 52.056 ;
     RECT  6.419 24.672 6.833 24.744 ;
     RECT  6.796 63.6 6.833 63.624 ;
     RECT  6.437 77.424 6.833 78.168 ;
     RECT  6.793 26.784 6.901 26.808 ;
     RECT  6.796 64.752 6.956 64.776 ;
     RECT  5.987 65.904 6.956 67.368 ;
     RECT  5.753 19.392 7.009 19.416 ;
     RECT  5.404 86.016 7.009 86.04 ;
     RECT  7.009 86.016 7.045 86.616 ;
     RECT  6.793 87.936 7.045 87.96 ;
     RECT  6.383 39.264 7.081 39.48 ;
     RECT  7.009 19.104 7.117 19.416 ;
     RECT  6.275 56.4 7.153 56.424 ;
     RECT  6.041 59.232 7.153 59.736 ;
     RECT  6.221 60.816 7.153 60.84 ;
     RECT  6.733 30 7.189 30.024 ;
     RECT  6.829 51.984 7.297 52.056 ;
     RECT  6.661 22.128 7.369 22.152 ;
     RECT  6.793 14.544 7.381 14.904 ;
     RECT  6.323 16.512 7.381 17.64 ;
     RECT  7.153 56.208 7.429 56.424 ;
     RECT  6.541 41.904 7.573 43.32 ;
     RECT  6.467 44.448 7.573 45.144 ;
     RECT  6.041 46.176 7.573 47.112 ;
     RECT  6.725 69.408 7.573 69.576 ;
     RECT  6.901 26.784 7.585 27.336 ;
     RECT  6.581 72.432 7.649 72.456 ;
     RECT  7.153 59.232 7.657 60.84 ;
     RECT  7.081 39.264 7.669 39.864 ;
     RECT  7.573 44.448 7.669 47.112 ;
     RECT  6.829 48.24 7.669 48.984 ;
     RECT  6.764 50.448 7.669 50.472 ;
     RECT  7.297 51.888 7.669 52.056 ;
     RECT  7.153 5.04 7.808 5.064 ;
     RECT  6.803 6.432 7.808 6.456 ;
     RECT  6.545 11.76 7.808 11.784 ;
     RECT  7.081 13.056 7.808 13.08 ;
     RECT  7.381 14.544 7.808 17.64 ;
     RECT  7.117 19.104 7.808 19.8 ;
     RECT  7.369 22.128 7.808 23.016 ;
     RECT  6.833 24.672 7.808 24.696 ;
     RECT  7.585 26.256 7.808 27.336 ;
     RECT  7.189 29.616 7.808 30.024 ;
     RECT  7.585 32.208 7.808 32.232 ;
     RECT  6.659 33.552 7.808 33.768 ;
     RECT  6.467 37.008 7.808 37.032 ;
     RECT  7.669 38.736 7.808 39.864 ;
     RECT  7.573 41.472 7.808 43.32 ;
     RECT  7.669 44.448 7.808 49.368 ;
     RECT  7.669 50.448 7.808 52.056 ;
     RECT  6.793 54.528 7.808 54.888 ;
     RECT  7.429 56.208 7.808 56.52 ;
     RECT  7.153 57.6 7.808 57.624 ;
     RECT  7.657 58.896 7.808 60.84 ;
     RECT  6.956 64.752 7.808 67.368 ;
     RECT  7.573 69.408 7.808 70.008 ;
     RECT  7.649 72.288 7.808 72.456 ;
     RECT  7.649 75.84 7.808 75.864 ;
     RECT  6.833 78.096 7.808 78.168 ;
     RECT  6.323 79.248 7.808 79.272 ;
     RECT  6.581 81.888 7.808 82.152 ;
     RECT  7.261 83.232 7.808 83.256 ;
     RECT  6.653 84.288 7.808 84.408 ;
     RECT  7.045 86.016 7.808 87.96 ;
     RECT  7.808 2.148 7.912 90.732 ;
     RECT  7.912 2.418 8.104 90.462 ;
     RECT  8.104 11.76 8.201 11.784 ;
     RECT  8.104 15.84 8.201 15.864 ;
     RECT  8.104 19.776 8.237 19.8 ;
     RECT  8.104 5.04 8.243 5.736 ;
     RECT  8.104 41.472 8.273 41.496 ;
     RECT  8.243 5.712 8.281 5.736 ;
     RECT  8.104 31.488 8.291 32.232 ;
     RECT  8.104 35.952 8.291 35.976 ;
     RECT  8.104 51.216 8.309 51.24 ;
     RECT  8.104 10.56 8.381 10.584 ;
     RECT  8.104 37.824 8.381 37.848 ;
     RECT  8.104 78.144 8.381 78.168 ;
     RECT  8.104 84.384 8.381 84.408 ;
     RECT  8.104 27.072 8.483 27.096 ;
     RECT  8.291 31.488 8.483 31.512 ;
     RECT  8.104 7.872 8.489 7.896 ;
     RECT  8.104 60.576 8.489 60.84 ;
     RECT  8.104 28.272 8.524 28.296 ;
     RECT  8.489 60.816 8.633 60.84 ;
     RECT  8.104 44.448 10.508 44.472 ;
     RECT  8.104 47.088 10.508 47.112 ;
     RECT  8.104 67.344 10.508 67.368 ;
     RECT  8.104 72.432 10.508 72.456 ;
     RECT  10.508 2.148 10.612 90.732 ;
     RECT  10.612 2.418 10.804 90.462 ;
     RECT  10.804 44.448 13.208 44.472 ;
     RECT  10.804 47.088 13.208 47.112 ;
     RECT  10.804 67.344 13.208 67.368 ;
     RECT  10.804 72.432 13.208 72.456 ;
     RECT  13.208 2.148 13.312 90.732 ;
     RECT  13.312 2.418 13.504 90.462 ;
     RECT  13.504 44.448 15.908 44.472 ;
     RECT  13.504 47.088 15.908 47.112 ;
     RECT  13.504 67.344 15.908 67.368 ;
     RECT  13.504 72.432 15.908 72.456 ;
     RECT  15.908 2.148 16.012 90.732 ;
     RECT  16.012 2.418 16.204 90.462 ;
     RECT  5.749 92.736 18.209 92.76 ;
     RECT  16.204 44.448 18.608 44.472 ;
     RECT  16.204 47.088 18.608 47.112 ;
     RECT  16.204 67.344 18.608 67.368 ;
     RECT  16.204 72.432 18.608 72.456 ;
     RECT  18.608 2.148 18.712 90.732 ;
     RECT  18.712 2.418 18.904 90.462 ;
     RECT  18.904 44.448 21.308 44.472 ;
     RECT  18.904 47.088 21.308 47.112 ;
     RECT  18.904 67.344 21.308 67.368 ;
     RECT  18.904 72.432 21.308 72.456 ;
     RECT  21.308 2.148 21.412 90.732 ;
     RECT  21.412 2.418 21.604 90.462 ;
     RECT  21.604 44.448 24.008 44.472 ;
     RECT  21.604 47.088 24.008 47.112 ;
     RECT  21.604 67.344 24.008 67.368 ;
     RECT  21.604 72.432 24.008 72.456 ;
     RECT  24.008 2.148 24.112 90.732 ;
     RECT  24.112 2.418 24.304 90.462 ;
     RECT  24.304 44.448 26.708 44.472 ;
     RECT  24.304 47.088 26.708 47.112 ;
     RECT  24.304 67.344 26.708 67.368 ;
     RECT  24.304 72.432 26.708 72.456 ;
     RECT  26.708 2.148 26.812 90.732 ;
     RECT  26.812 2.418 27.004 90.462 ;
     RECT  27.004 44.448 29.408 44.472 ;
     RECT  27.004 47.088 29.408 47.112 ;
     RECT  27.004 67.344 29.408 67.368 ;
     RECT  27.004 72.432 29.408 72.456 ;
     RECT  29.408 2.148 29.512 90.732 ;
     RECT  29.512 2.418 29.704 90.462 ;
     RECT  29.704 67.344 30.805 67.368 ;
     RECT  30.769 28.032 30.953 28.056 ;
     RECT  30.805 67.344 30.953 67.656 ;
     RECT  29.704 47.088 31.993 47.112 ;
     RECT  30.953 67.344 32.065 67.368 ;
     RECT  32.101 10.704 32.108 10.728 ;
     RECT  32.101 14.928 32.108 15.864 ;
     RECT  31.597 31.68 32.108 31.704 ;
     RECT  29.704 44.448 32.108 44.472 ;
     RECT  31.993 47.088 32.108 47.736 ;
     RECT  32.065 57.936 32.108 57.96 ;
     RECT  31.849 62.16 32.108 62.184 ;
     RECT  32.065 64.32 32.108 64.344 ;
     RECT  32.065 67.344 32.108 67.608 ;
     RECT  29.704 72.432 32.108 72.456 ;
     RECT  32.065 84.864 32.108 84.888 ;
     RECT  32.108 2.148 32.212 90.732 ;
     RECT  32.212 2.418 32.404 90.462 ;
     RECT  32.404 14.928 32.573 15.96 ;
     RECT  32.404 6.816 32.609 6.84 ;
     RECT  32.404 69.696 32.609 69.72 ;
     RECT  32.404 84.864 32.717 84.888 ;
     RECT  32.404 38.496 33.005 38.52 ;
     RECT  32.404 17.616 33.149 18.504 ;
     RECT  32.404 44.448 33.149 44.472 ;
     RECT  32.404 34.56 33.221 34.68 ;
     RECT  32.404 63.792 33.257 64.344 ;
     RECT  32.404 65.472 33.329 65.496 ;
     RECT  32.404 71.856 33.365 74.856 ;
     RECT  32.404 21.936 33.397 21.96 ;
     RECT  32.404 81.6 33.469 82.584 ;
     RECT  33.397 21.12 33.541 21.96 ;
     RECT  32.404 23.232 33.545 23.256 ;
     RECT  33.221 34.656 33.653 34.68 ;
     RECT  32.404 62.16 33.653 62.28 ;
     RECT  32.404 10.704 33.689 11.64 ;
     RECT  33.653 62.16 33.761 62.184 ;
     RECT  32.573 15.936 33.833 15.96 ;
     RECT  33.649 60.144 33.865 60.168 ;
     RECT  33.577 27.216 34.153 27.24 ;
     RECT  33.541 21.12 34.157 22.152 ;
     RECT  32.404 7.872 34.189 7.896 ;
     RECT  32.573 14.928 34.189 14.952 ;
     RECT  33.149 18.48 34.189 18.504 ;
     RECT  32.404 25.152 34.189 25.224 ;
     RECT  34.153 26.544 34.189 27.24 ;
     RECT  33.721 28.32 34.189 28.344 ;
     RECT  32.404 29.76 34.189 29.784 ;
     RECT  32.404 32.448 34.189 32.472 ;
     RECT  33.685 37.008 34.189 37.032 ;
     RECT  32.404 40.8 34.189 40.824 ;
     RECT  32.404 43.008 34.189 43.032 ;
     RECT  32.404 47.088 34.189 47.112 ;
     RECT  33.577 50.784 34.189 50.808 ;
     RECT  32.404 52.176 34.189 52.2 ;
     RECT  32.404 57.936 34.189 58.68 ;
     RECT  33.865 60.144 34.189 60.984 ;
     RECT  32.404 66.864 34.189 67.608 ;
     RECT  33.901 70.464 34.189 70.488 ;
     RECT  33.365 71.856 34.189 74.232 ;
     RECT  32.404 77.136 34.189 77.448 ;
     RECT  32.404 78.48 34.189 78.504 ;
     RECT  33.793 80.112 34.189 80.136 ;
     RECT  34.189 7.872 34.225 8.04 ;
     RECT  34.189 35.232 34.225 35.4 ;
     RECT  34.189 55.056 34.225 61.32 ;
     RECT  34.189 65.568 34.225 67.848 ;
     RECT  34.189 68.976 34.225 69 ;
     RECT  33.469 81.6 34.225 83.112 ;
     RECT  34.189 87.168 34.225 87.192 ;
     RECT  34.189 88.32 34.225 88.344 ;
     RECT  33.901 5.712 34.405 5.736 ;
     RECT  34.189 6.864 34.405 6.888 ;
     RECT  34.189 85.056 34.477 85.896 ;
     RECT  34.225 87.168 34.477 88.344 ;
     RECT  34.189 18.336 34.657 19.656 ;
     RECT  34.189 40.656 34.657 40.824 ;
     RECT  34.189 37.008 34.693 37.704 ;
     RECT  34.189 42.096 34.693 45.912 ;
     RECT  34.189 47.088 34.693 47.208 ;
     RECT  33.257 63.792 34.693 63.912 ;
     RECT  34.405 5.712 34.729 6.888 ;
     RECT  34.225 7.872 34.729 8.376 ;
     RECT  34.189 9.504 34.729 10.488 ;
     RECT  33.689 11.616 34.729 11.64 ;
     RECT  34.657 18 34.729 19.656 ;
     RECT  34.157 21.312 34.729 22.152 ;
     RECT  34.189 24.096 34.729 25.416 ;
     RECT  34.189 26.544 34.729 29.784 ;
     RECT  34.189 32.448 34.729 33.96 ;
     RECT  34.693 36.864 34.729 37.704 ;
     RECT  34.657 38.976 34.729 40.824 ;
     RECT  34.693 42.096 34.729 47.208 ;
     RECT  34.189 48.48 34.729 48.504 ;
     RECT  34.189 49.632 34.729 52.632 ;
     RECT  34.225 54.72 34.729 61.32 ;
     RECT  34.693 63.6 34.729 63.912 ;
     RECT  34.225 81.6 34.729 83.784 ;
     RECT  34.477 85.056 34.729 88.344 ;
     RECT  34.729 5.712 34.765 11.832 ;
     RECT  34.189 12.96 34.765 15.576 ;
     RECT  34.729 17.712 34.765 19.656 ;
     RECT  34.729 21.312 34.765 29.784 ;
     RECT  34.729 31.776 34.765 34.248 ;
     RECT  34.729 36.72 34.765 37.704 ;
     RECT  34.729 38.832 34.765 47.4 ;
     RECT  34.729 48.48 34.765 52.776 ;
     RECT  34.729 54.384 34.765 61.32 ;
     RECT  34.729 63.264 34.765 64.248 ;
     RECT  34.225 65.568 34.765 69.336 ;
     RECT  34.189 75.216 34.765 77.448 ;
     RECT  34.189 78.48 34.765 80.472 ;
     RECT  34.765 36.72 34.801 47.4 ;
     RECT  34.765 48.48 34.801 61.32 ;
     RECT  34.765 75.216 34.801 80.472 ;
     RECT  34.729 81.6 34.801 88.344 ;
     RECT  34.765 5.712 35.341 15.576 ;
     RECT  34.765 17.04 35.341 19.656 ;
     RECT  34.765 21.312 35.341 34.248 ;
     RECT  34.225 35.232 35.341 35.592 ;
     RECT  34.801 36.72 35.341 61.32 ;
     RECT  34.765 62.928 35.341 64.248 ;
     RECT  34.765 65.376 35.341 69.336 ;
     RECT  34.189 70.464 35.341 74.232 ;
     RECT  35.341 20.976 35.377 61.32 ;
     RECT  35.341 62.448 35.377 64.248 ;
     RECT  34.801 75.216 35.377 88.344 ;
     RECT  35.341 65.232 35.881 74.232 ;
     RECT  35.377 75.216 35.881 88.536 ;
     RECT  35.341 4.56 35.917 19.656 ;
     RECT  35.377 20.976 35.917 64.248 ;
     RECT  35.881 65.232 35.917 88.536 ;
     RECT  35.917 4.416 36.54 88.536 ;
    LAYER M5 ;
     RECT  2.4 2.137 2.52 2.151 ;
     RECT  5.1 2.137 5.22 2.151 ;
     RECT  7.8 2.137 7.92 2.151 ;
     RECT  10.5 2.137 10.62 2.151 ;
     RECT  13.2 2.137 13.32 2.151 ;
     RECT  15.9 2.137 16.02 2.151 ;
     RECT  18.6 2.137 18.72 2.151 ;
     RECT  21.3 2.137 21.42 2.151 ;
     RECT  24 2.137 24.12 2.151 ;
     RECT  26.7 2.137 26.82 2.151 ;
     RECT  29.4 2.137 29.52 2.151 ;
     RECT  32.1 2.137 32.22 2.151 ;
     RECT  5.1 2.151 5.412 4.501 ;
     RECT  7.8 2.151 8.112 5.029 ;
     RECT  4.368 4.501 5.412 7.909 ;
     RECT  6.768 5.605 6.792 8.435 ;
     RECT  4.128 7.909 5.412 9.637 ;
     RECT  7.8 5.029 8.232 10.595 ;
     RECT  4.128 9.637 5.544 10.789 ;
     RECT  4.128 10.789 6.072 11.269 ;
     RECT  4.128 11.269 6.264 12.035 ;
     RECT  2.4 2.151 2.712 12.709 ;
     RECT  4.128 12.035 5.688 12.709 ;
     RECT  2.4 12.709 5.688 12.755 ;
     RECT  4.752 12.755 5.688 12.995 ;
     RECT  5.1 12.995 5.688 13.045 ;
     RECT  7.8 10.595 8.112 13.045 ;
     RECT  2.4 12.755 3.432 13.765 ;
     RECT  5.1 13.045 5.928 14.197 ;
     RECT  7.392 13.045 8.112 14.533 ;
     RECT  4.608 14.197 5.928 14.579 ;
     RECT  4.608 14.579 5.688 15.731 ;
     RECT  4.608 15.731 5.412 16.307 ;
     RECT  5.1 16.307 5.412 16.837 ;
     RECT  7.008 14.533 8.112 16.933 ;
     RECT  5.1 16.837 5.688 16.981 ;
     RECT  6.672 16.933 8.112 16.981 ;
     RECT  5.1 16.981 8.112 18.757 ;
     RECT  4.608 18.757 8.112 19.139 ;
     RECT  4.608 19.139 6.696 19.427 ;
     RECT  2.4 13.765 3.528 19.955 ;
     RECT  4.608 19.427 5.688 20.339 ;
     RECT  4.608 20.339 5.412 20.725 ;
     RECT  3.936 20.725 5.412 20.819 ;
     RECT  5.1 20.819 5.412 22.165 ;
     RECT  6.672 19.427 6.696 22.165 ;
     RECT  5.1 22.165 6.696 23.171 ;
     RECT  3.936 20.819 3.96 23.173 ;
     RECT  5.1 23.171 6.408 23.173 ;
     RECT  3.936 23.173 6.408 23.363 ;
     RECT  4.32 23.363 6.408 24.469 ;
     RECT  3.984 24.469 6.408 24.563 ;
     RECT  7.68 19.139 8.112 24.661 ;
     RECT  6.96 24.661 8.112 27.061 ;
     RECT  3.984 24.563 5.64 27.205 ;
     RECT  6.96 27.061 8.472 27.301 ;
     RECT  2.4 19.955 2.712 27.733 ;
     RECT  3.936 27.205 5.64 27.733 ;
     RECT  2.4 27.733 5.64 27.779 ;
     RECT  2.4 27.779 3.624 29.029 ;
     RECT  4.752 27.779 5.64 29.029 ;
     RECT  6.912 27.301 8.472 29.989 ;
     RECT  2.4 29.029 5.64 30.851 ;
     RECT  6.672 29.989 8.472 30.949 ;
     RECT  4.176 30.851 5.64 31.379 ;
     RECT  6.624 30.949 8.472 31.523 ;
     RECT  4.176 31.379 5.592 32.195 ;
     RECT  2.4 30.851 2.712 33.397 ;
     RECT  4.464 32.195 5.592 33.397 ;
     RECT  2.4 33.397 5.592 33.589 ;
     RECT  6.624 31.523 8.28 33.589 ;
     RECT  2.4 33.589 8.28 33.779 ;
     RECT  2.4 33.779 6.552 35.027 ;
     RECT  2.4 35.027 5.592 35.987 ;
     RECT  4.464 35.987 5.592 36.997 ;
     RECT  6.768 35.557 6.792 36.997 ;
     RECT  4.464 36.997 6.792 37.043 ;
     RECT  7.8 33.779 8.28 37.859 ;
     RECT  4.464 37.043 6.456 38.149 ;
     RECT  2.4 35.987 2.712 38.677 ;
     RECT  3.888 38.149 6.456 38.677 ;
     RECT  7.8 37.859 8.112 38.725 ;
     RECT  2.4 38.677 6.456 39.253 ;
     RECT  7.68 38.725 8.112 39.253 ;
     RECT  2.4 39.253 8.112 39.395 ;
     RECT  3.888 39.395 8.112 41.075 ;
     RECT  6.768 41.075 8.112 41.939 ;
     RECT  3.888 41.075 5.592 43.237 ;
     RECT  3.888 43.237 5.88 43.379 ;
     RECT  3.936 43.379 5.88 43.475 ;
     RECT  4.032 43.475 5.88 43.861 ;
     RECT  4.032 43.861 6.456 44.869 ;
     RECT  3.888 44.869 6.456 45.109 ;
     RECT  7.584 41.939 8.112 45.109 ;
     RECT  3.888 45.109 8.112 45.155 ;
     RECT  3.888 45.155 5.592 46.019 ;
     RECT  4.272 46.019 5.592 46.211 ;
     RECT  6.816 45.155 8.112 46.211 ;
     RECT  2.4 39.395 2.712 47.269 ;
     RECT  7.8 46.211 8.112 47.845 ;
     RECT  4.992 46.211 5.592 48.421 ;
     RECT  2.4 47.269 3.432 48.805 ;
     RECT  4.992 48.421 6.312 48.805 ;
     RECT  2.4 48.805 6.312 48.947 ;
     RECT  4.128 48.947 6.312 49.619 ;
     RECT  7.68 47.845 8.112 50.437 ;
     RECT  4.128 49.619 5.784 51.493 ;
     RECT  4.032 51.493 5.784 52.021 ;
     RECT  6.816 50.437 8.112 52.021 ;
     RECT  4.032 52.021 8.112 52.067 ;
     RECT  4.032 52.067 6.744 53.557 ;
     RECT  3.936 53.557 6.744 54.517 ;
     RECT  7.8 52.067 8.112 54.517 ;
     RECT  3.936 54.517 8.112 55.331 ;
     RECT  4.032 55.331 5.784 56.389 ;
     RECT  7.44 55.331 8.112 56.531 ;
     RECT  4.032 56.389 6.264 56.965 ;
     RECT  3.936 56.965 6.264 57.059 ;
     RECT  3.936 57.059 5.784 57.541 ;
     RECT  7.8 56.531 8.112 57.589 ;
     RECT  7.68 57.589 8.112 58.931 ;
     RECT  3.84 57.541 5.784 59.173 ;
     RECT  2.4 48.947 2.712 59.221 ;
     RECT  3.792 59.173 5.784 59.221 ;
     RECT  0.288 58.501 0.312 59.315 ;
     RECT  2.4 59.221 5.976 59.315 ;
     RECT  2.4 59.315 3.912 60.659 ;
     RECT  2.4 60.659 3.816 60.707 ;
     RECT  2.4 60.707 3.432 61.139 ;
     RECT  4.992 59.315 5.976 61.477 ;
     RECT  4.992 61.477 6.12 63.157 ;
     RECT  4.752 63.157 6.12 63.493 ;
     RECT  4.752 63.493 6.744 64.403 ;
     RECT  3.696 64.741 3.72 64.885 ;
     RECT  5.1 64.403 6.744 64.933 ;
     RECT  7.8 58.931 8.112 64.933 ;
     RECT  3.696 64.885 4.008 65.987 ;
     RECT  5.1 64.933 8.112 66.515 ;
     RECT  5.1 66.515 6.504 67.283 ;
     RECT  3.984 65.987 4.008 67.571 ;
     RECT  5.1 67.283 5.784 68.773 ;
     RECT  5.1 68.773 6.456 69.493 ;
     RECT  4.032 69.493 6.456 69.587 ;
     RECT  7.584 66.515 8.112 70.019 ;
     RECT  2.4 61.139 2.712 70.933 ;
     RECT  4.032 69.587 5.784 70.933 ;
     RECT  2.4 70.933 5.784 70.979 ;
     RECT  4.992 70.979 5.784 71.219 ;
     RECT  5.1 71.219 5.784 71.749 ;
     RECT  5.1 71.749 6.264 72.419 ;
     RECT  5.1 72.419 5.784 72.709 ;
     RECT  4.992 72.709 5.784 73.571 ;
     RECT  5.1 73.571 5.784 75.157 ;
     RECT  4.992 75.157 5.784 75.205 ;
     RECT  2.4 70.979 3.48 75.541 ;
     RECT  2.4 75.541 3.96 75.781 ;
     RECT  4.992 75.205 6.36 75.781 ;
     RECT  7.68 70.019 8.112 75.875 ;
     RECT  2.4 75.781 6.36 75.971 ;
     RECT  3.936 75.971 6.36 76.787 ;
     RECT  4.608 76.787 6.36 76.979 ;
     RECT  4.608 76.979 6.072 77.459 ;
     RECT  4.608 77.459 5.88 79.045 ;
     RECT  4.512 79.045 5.88 79.189 ;
     RECT  4.512 79.189 6.312 79.811 ;
     RECT  5.1 79.811 6.312 80.963 ;
     RECT  4.08 80.917 4.104 83.267 ;
     RECT  5.1 80.963 5.784 84.325 ;
     RECT  5.1 84.325 6.312 84.901 ;
     RECT  4.368 84.901 6.312 84.995 ;
     RECT  7.8 75.875 8.112 86.005 ;
     RECT  4.368 84.995 5.784 86.051 ;
     RECT  2.4 75.971 2.712 86.581 ;
     RECT  5.1 86.051 5.784 87.109 ;
     RECT  7.056 86.005 8.112 87.251 ;
     RECT  4.656 87.109 5.784 87.827 ;
     RECT  2.4 86.581 3.432 88.883 ;
     RECT  2.4 88.883 2.712 90.729 ;
     RECT  7.8 87.251 8.112 90.729 ;
     RECT  10.5 2.151 10.812 90.729 ;
     RECT  13.2 2.151 13.512 90.729 ;
     RECT  15.9 2.151 16.212 90.729 ;
     RECT  18.6 2.151 18.912 90.729 ;
     RECT  21.3 2.151 21.612 90.729 ;
     RECT  24 2.151 24.312 90.729 ;
     RECT  26.7 2.151 27.012 90.729 ;
     RECT  29.4 2.151 29.712 90.729 ;
     RECT  32.1 2.151 32.412 90.729 ;
     RECT  2.4 90.729 2.52 90.743 ;
     RECT  5.1 87.827 5.784 90.743 ;
     RECT  7.8 90.729 7.92 90.743 ;
     RECT  10.5 90.729 10.62 90.743 ;
     RECT  13.2 90.729 13.32 90.743 ;
     RECT  15.9 90.729 16.02 90.743 ;
     RECT  18.6 90.729 18.72 90.743 ;
     RECT  21.3 90.729 21.42 90.743 ;
     RECT  24 90.729 24.12 90.743 ;
     RECT  26.7 90.729 26.82 90.743 ;
     RECT  29.4 90.729 29.52 90.743 ;
     RECT  32.1 90.729 32.22 90.743 ;
     RECT  5.76 90.743 5.784 92.771 ;
     RECT  5.412 5.605 6.768 8.435 ;
     RECT  6.792 5.605 7.8 8.435 ;
     RECT  2.712 7.909 4.128 12.709 ;
     RECT  5.412 8.435 5.544 9.637 ;
     RECT  5.688 12.035 6.264 13.045 ;
     RECT  3.432 12.755 4.752 12.995 ;
     RECT  3.432 12.995 5.1 13.765 ;
     RECT  5.928 13.045 7.392 14.533 ;
     RECT  3.528 13.765 5.1 14.197 ;
     RECT  3.528 14.197 4.608 16.307 ;
     RECT  5.928 14.533 7.008 14.579 ;
     RECT  5.688 14.579 7.008 15.731 ;
     RECT  5.412 15.731 7.008 16.837 ;
     RECT  5.688 16.837 7.008 16.933 ;
     RECT  5.688 16.933 6.672 16.981 ;
     RECT  3.528 18.757 4.608 19.955 ;
     RECT  6.696 19.139 7.68 23.171 ;
     RECT  5.688 19.427 6.672 20.339 ;
     RECT  2.712 19.955 4.608 20.725 ;
     RECT  5.412 20.339 6.672 22.165 ;
     RECT  2.712 20.725 3.936 23.363 ;
     RECT  3.96 20.819 5.1 23.173 ;
     RECT  6.408 23.171 7.68 24.563 ;
     RECT  2.712 23.363 4.32 24.469 ;
     RECT  2.712 24.469 3.984 27.205 ;
     RECT  5.64 24.563 7.68 24.661 ;
     RECT  5.64 24.661 6.96 27.301 ;
     RECT  2.712 27.205 3.936 27.733 ;
     RECT  5.64 27.301 6.912 29.989 ;
     RECT  3.624 27.779 4.752 29.029 ;
     RECT  5.64 29.989 6.672 30.949 ;
     RECT  2.712 30.851 4.176 32.195 ;
     RECT  5.64 30.949 6.624 31.379 ;
     RECT  5.592 31.379 6.624 33.589 ;
     RECT  2.712 32.195 4.464 33.397 ;
     RECT  6.552 33.779 7.8 35.027 ;
     RECT  5.592 35.027 7.8 35.557 ;
     RECT  5.592 35.557 6.768 36.997 ;
     RECT  6.792 35.557 7.8 37.043 ;
     RECT  6.456 37.043 7.8 38.725 ;
     RECT  2.712 38.149 3.888 38.677 ;
     RECT  6.456 38.725 7.68 39.253 ;
     RECT  2.712 39.395 3.888 43.379 ;
     RECT  5.592 41.075 6.768 41.939 ;
     RECT  5.592 41.939 5.88 43.237 ;
     RECT  2.712 43.379 3.936 43.475 ;
     RECT  2.712 43.475 4.032 44.869 ;
     RECT  6.456 43.861 7.584 45.109 ;
     RECT  2.712 44.869 3.888 46.019 ;
     RECT  5.592 45.155 6.816 46.211 ;
     RECT  2.712 46.019 4.272 46.211 ;
     RECT  2.712 46.211 3.432 47.269 ;
     RECT  6.312 48.421 7.68 49.619 ;
     RECT  2.712 48.947 4.128 51.493 ;
     RECT  5.784 49.619 7.68 50.437 ;
     RECT  5.784 50.437 6.816 52.021 ;
     RECT  2.712 51.493 4.032 53.557 ;
     RECT  6.744 52.067 7.8 54.517 ;
     RECT  2.712 53.557 3.936 55.331 ;
     RECT  2.712 55.331 4.032 56.965 ;
     RECT  5.784 55.331 7.44 56.389 ;
     RECT  6.264 56.389 7.44 56.531 ;
     RECT  6.264 56.531 7.8 57.059 ;
     RECT  2.712 56.965 3.936 57.541 ;
     RECT  7.68 57.059 7.8 57.589 ;
     RECT  2.712 57.541 3.84 59.173 ;
     RECT  2.712 59.173 3.792 59.221 ;
     RECT  3.912 59.315 4.992 60.659 ;
     RECT  3.816 60.659 4.992 60.707 ;
     RECT  6.744 63.493 7.8 64.933 ;
     RECT  4.752 64.403 5.1 64.741 ;
     RECT  2.712 64.741 3.696 65.987 ;
     RECT  3.72 64.741 5.1 64.885 ;
     RECT  4.008 64.885 5.1 67.571 ;
     RECT  2.712 65.987 3.984 67.571 ;
     RECT  6.504 66.515 7.584 67.283 ;
     RECT  5.784 67.283 7.584 68.773 ;
     RECT  6.456 68.773 7.584 69.587 ;
     RECT  2.712 69.493 4.032 70.933 ;
     RECT  3.48 70.979 4.992 71.219 ;
     RECT  3.48 71.219 5.1 72.709 ;
     RECT  6.264 71.749 7.68 72.419 ;
     RECT  3.48 72.709 4.992 73.571 ;
     RECT  3.48 75.157 4.992 75.541 ;
     RECT  6.36 75.205 7.68 75.875 ;
     RECT  3.96 75.541 4.992 75.781 ;
     RECT  6.36 75.875 7.8 76.979 ;
     RECT  2.712 75.971 3.936 76.787 ;
     RECT  6.312 79.189 7.8 80.963 ;
     RECT  4.512 79.811 5.1 80.917 ;
     RECT  2.712 80.917 4.08 83.267 ;
     RECT  4.104 80.917 5.1 83.267 ;
     RECT  6.312 84.325 7.8 84.995 ;
     RECT  5.784 84.995 7.8 86.005 ;
     RECT  5.784 86.005 7.056 87.251 ;
     RECT  4.368 86.051 5.1 86.581 ;
     RECT  3.432 86.581 5.1 87.109 ;
     RECT  3.432 87.109 4.656 87.827 ;
  END
END dsfd_hstnh_514
END LIBRARY
